# Copyright (c) 1993 - 2026 ARM Limited. All Rights Reserved.
# Use of this Software is subject to the terms and conditions of the
# applicable license agreement with ARM Limited.

# PhyVGen V 11.0.0-beta2
# ARM Version r0p0
# Creation Date: Tue Apr  7 18:06:24 2026


# Memory Configuration:
# ~~~~~~~~~~~~~~~~~~~~~
#  -activity_factor 50 -atf off -back_biasing off -bits 128 -bmux off
# -bus_notation on -check_instname on -diodes on -drive 6 -ema on -frequency
# 1.0 -instname rf128x128 -left_bus_delim "[" -mux 2 -mvt BASE -name_case lower
# -power_gating off -power_type otc -pwr_gnd_rename
# vddpe:VDDPE,vddce:VDDCE,vsse:VSSE -rcols 2 -redundancy off -retention on
# -right_bus_delim "]" -rrows 0 -ser none -site_def off -top_layer m5-m10
# -vmin_assist off -words 128 -wp_size 1 -write_mask on -write_thru off
# 

VERSION 5.8 ;
BUSBITCHARS "[]" ;
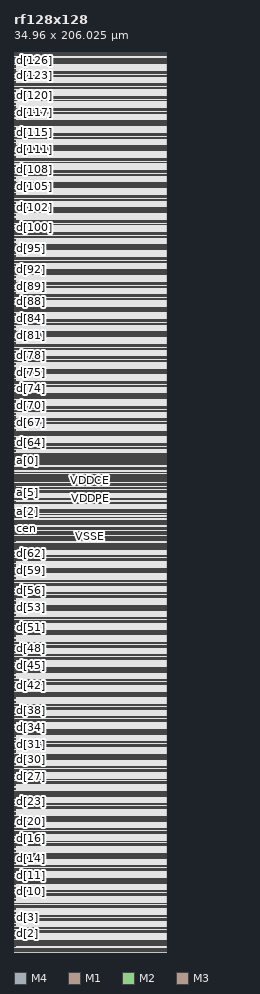
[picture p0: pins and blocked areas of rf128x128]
MACRO rf128x128
	FOREIGN rf128x128 0 0 ;
	SYMMETRY X Y ;
	SIZE 34.96 BY 206.025 ;
	CLASS BLOCK ;
	PIN VDDCE
		USE POWER ;
		DIRECTION INOUT ;
		PORT
			LAYER	M4 ;
			RECT	0 95.965 34.96 96.175 ;
		END

		PORT
			LAYER	M4 ;
			RECT	0 107.815 34.96 108.025 ;
		END

		PORT
			LAYER	M4 ;
			RECT	0 109.675 34.96 109.825 ;
		END

		PORT
			LAYER	M4 ;
			RECT	0 113.28 34.96 113.43 ;
		END

		PORT
			LAYER	M4 ;
			RECT	0 203.925 34.96 204.135 ;
		END

		PORT
			LAYER	M4 ;
			RECT	0 135.765 34.96 135.975 ;
		END

		PORT
			LAYER	M4 ;
			RECT	0 132.925 34.96 133.135 ;
		END

		PORT
			LAYER	M4 ;
			RECT	0 130.085 34.96 130.295 ;
		END

		PORT
			LAYER	M4 ;
			RECT	0 127.245 34.96 127.455 ;
		END

		PORT
			LAYER	M4 ;
			RECT	0 124.405 34.96 124.615 ;
		END

		PORT
			LAYER	M4 ;
			RECT	0 198.245 34.96 198.455 ;
		END

		PORT
			LAYER	M4 ;
			RECT	0 121.565 34.96 121.775 ;
		END

		PORT
			LAYER	M4 ;
			RECT	0 118.725 34.96 118.935 ;
		END

		PORT
			LAYER	M4 ;
			RECT	0 115.885 34.96 116.095 ;
		END

		PORT
			LAYER	M4 ;
			RECT	0 195.405 34.96 195.615 ;
		END

		PORT
			LAYER	M4 ;
			RECT	0 89.93 34.96 90.14 ;
		END

		PORT
			LAYER	M4 ;
			RECT	0 87.09 34.96 87.3 ;
		END

		PORT
			LAYER	M4 ;
			RECT	0 84.25 34.96 84.46 ;
		END

		PORT
			LAYER	M4 ;
			RECT	0 81.41 34.96 81.62 ;
		END

		PORT
			LAYER	M4 ;
			RECT	0 78.57 34.96 78.78 ;
		END

		PORT
			LAYER	M4 ;
			RECT	0 75.73 34.96 75.94 ;
		END

		PORT
			LAYER	M4 ;
			RECT	0 72.89 34.96 73.1 ;
		END

		PORT
			LAYER	M4 ;
			RECT	0 192.565 34.96 192.775 ;
		END

		PORT
			LAYER	M4 ;
			RECT	0 70.05 34.96 70.26 ;
		END

		PORT
			LAYER	M4 ;
			RECT	0 67.21 34.96 67.42 ;
		END

		PORT
			LAYER	M4 ;
			RECT	0 64.37 34.96 64.58 ;
		END

		PORT
			LAYER	M4 ;
			RECT	0 61.53 34.96 61.74 ;
		END

		PORT
			LAYER	M4 ;
			RECT	0 58.69 34.96 58.9 ;
		END

		PORT
			LAYER	M4 ;
			RECT	0 55.85 34.96 56.06 ;
		END

		PORT
			LAYER	M4 ;
			RECT	0 53.01 34.96 53.22 ;
		END

		PORT
			LAYER	M4 ;
			RECT	0 50.17 34.96 50.38 ;
		END

		PORT
			LAYER	M4 ;
			RECT	0 47.33 34.96 47.54 ;
		END

		PORT
			LAYER	M4 ;
			RECT	0 44.49 34.96 44.7 ;
		END

		PORT
			LAYER	M4 ;
			RECT	0 189.725 34.96 189.935 ;
		END

		PORT
			LAYER	M4 ;
			RECT	0 41.65 34.96 41.86 ;
		END

		PORT
			LAYER	M4 ;
			RECT	0 38.81 34.96 39.02 ;
		END

		PORT
			LAYER	M4 ;
			RECT	0 35.97 34.96 36.18 ;
		END

		PORT
			LAYER	M4 ;
			RECT	0 33.13 34.96 33.34 ;
		END

		PORT
			LAYER	M4 ;
			RECT	0 30.29 34.96 30.5 ;
		END

		PORT
			LAYER	M4 ;
			RECT	0 27.45 34.96 27.66 ;
		END

		PORT
			LAYER	M4 ;
			RECT	0 24.61 34.96 24.82 ;
		END

		PORT
			LAYER	M4 ;
			RECT	0 21.77 34.96 21.98 ;
		END

		PORT
			LAYER	M4 ;
			RECT	0 18.93 34.96 19.14 ;
		END

		PORT
			LAYER	M4 ;
			RECT	0 16.09 34.96 16.3 ;
		END

		PORT
			LAYER	M4 ;
			RECT	0 186.885 34.96 187.095 ;
		END

		PORT
			LAYER	M4 ;
			RECT	0 13.25 34.96 13.46 ;
		END

		PORT
			LAYER	M4 ;
			RECT	0 10.41 34.96 10.62 ;
		END

		PORT
			LAYER	M4 ;
			RECT	0 7.57 34.96 7.78 ;
		END

		PORT
			LAYER	M4 ;
			RECT	0 4.73 34.96 4.94 ;
		END

		PORT
			LAYER	M4 ;
			RECT	0 1.89 34.96 2.1 ;
		END

		PORT
			LAYER	M4 ;
			RECT	0 184.045 34.96 184.255 ;
		END

		PORT
			LAYER	M4 ;
			RECT	0 181.205 34.96 181.415 ;
		END

		PORT
			LAYER	M4 ;
			RECT	0 178.365 34.96 178.575 ;
		END

		PORT
			LAYER	M4 ;
			RECT	0 175.525 34.96 175.735 ;
		END

		PORT
			LAYER	M4 ;
			RECT	0 172.685 34.96 172.895 ;
		END

		PORT
			LAYER	M4 ;
			RECT	0 169.845 34.96 170.055 ;
		END

		PORT
			LAYER	M4 ;
			RECT	0 167.005 34.96 167.215 ;
		END

		PORT
			LAYER	M4 ;
			RECT	0 164.165 34.96 164.375 ;
		END

		PORT
			LAYER	M4 ;
			RECT	0 161.325 34.96 161.535 ;
		END

		PORT
			LAYER	M4 ;
			RECT	0 158.485 34.96 158.695 ;
		END

		PORT
			LAYER	M4 ;
			RECT	0 155.645 34.96 155.855 ;
		END

		PORT
			LAYER	M4 ;
			RECT	0 152.805 34.96 153.015 ;
		END

		PORT
			LAYER	M4 ;
			RECT	0 201.085 34.96 201.295 ;
		END

		PORT
			LAYER	M4 ;
			RECT	0 149.965 34.96 150.175 ;
		END

		PORT
			LAYER	M4 ;
			RECT	0 147.125 34.96 147.335 ;
		END

		PORT
			LAYER	M4 ;
			RECT	0 144.285 34.96 144.495 ;
		END

		PORT
			LAYER	M4 ;
			RECT	0 141.445 34.96 141.655 ;
		END

		PORT
			LAYER	M4 ;
			RECT	0 138.605 34.96 138.815 ;
		END

		PORT
			LAYER	M4 ;
			RECT	0 92.235 34.96 92.365 ;
		END

		PORT
			LAYER	M4 ;
			RECT	0 95.665 34.96 95.795 ;
		END

		PORT
			LAYER	M4 ;
			RECT	0 205.205 34.96 205.355 ;
		END

		PORT
			LAYER	M4 ;
			RECT	0 108.195 34.96 108.325 ;
		END

		PORT
			LAYER	M4 ;
			RECT	0 0.67 34.96 0.82 ;
		END

		PORT
			LAYER	M4 ;
			RECT	0 114.07 34.96 114.2 ;
		END

	END VDDCE

	PIN VDDPE
		USE POWER ;
		DIRECTION INOUT ;
		PORT
			LAYER	M4 ;
			RECT	0 94.255 34.96 94.405 ;
		END

		PORT
			LAYER	M4 ;
			RECT	0 94.625 34.96 94.835 ;
		END

		PORT
			LAYER	M4 ;
			RECT	0 98.15 34.96 98.36 ;
		END

		PORT
			LAYER	M4 ;
			RECT	0 98.625 34.96 98.835 ;
		END

		PORT
			LAYER	M4 ;
			RECT	0 100.04 34.96 100.25 ;
		END

		PORT
			LAYER	M4 ;
			RECT	0 101.185 34.96 101.335 ;
		END

		PORT
			LAYER	M4 ;
			RECT	0 103.6 34.96 103.81 ;
		END

		PORT
			LAYER	M4 ;
			RECT	0 105.16 34.96 105.37 ;
		END

		PORT
			LAYER	M4 ;
			RECT	0 106.02 34.96 106.23 ;
		END

		PORT
			LAYER	M4 ;
			RECT	0 109.13 34.96 109.34 ;
		END

		PORT
			LAYER	M4 ;
			RECT	0 112.11 34.96 112.32 ;
		END

		PORT
			LAYER	M4 ;
			RECT	0 112.485 34.96 112.695 ;
		END

		PORT
			LAYER	M4 ;
			RECT	0 203.345 34.96 203.555 ;
		END

		PORT
			LAYER	M4 ;
			RECT	0 135.185 34.96 135.395 ;
		END

		PORT
			LAYER	M4 ;
			RECT	0 132.345 34.96 132.555 ;
		END

		PORT
			LAYER	M4 ;
			RECT	0 129.505 34.96 129.715 ;
		END

		PORT
			LAYER	M4 ;
			RECT	0 126.665 34.96 126.875 ;
		END

		PORT
			LAYER	M4 ;
			RECT	0 123.825 34.96 124.035 ;
		END

		PORT
			LAYER	M4 ;
			RECT	0 120.985 34.96 121.195 ;
		END

		PORT
			LAYER	M4 ;
			RECT	0 118.145 34.96 118.355 ;
		END

		PORT
			LAYER	M4 ;
			RECT	0 115.305 34.96 115.515 ;
		END

		PORT
			LAYER	M4 ;
			RECT	0 197.665 34.96 197.875 ;
		END

		PORT
			LAYER	M4 ;
			RECT	0 194.825 34.96 195.035 ;
		END

		PORT
			LAYER	M4 ;
			RECT	0 90.51 34.96 90.72 ;
		END

		PORT
			LAYER	M4 ;
			RECT	0 87.67 34.96 87.88 ;
		END

		PORT
			LAYER	M4 ;
			RECT	0 84.83 34.96 85.04 ;
		END

		PORT
			LAYER	M4 ;
			RECT	0 81.99 34.96 82.2 ;
		END

		PORT
			LAYER	M4 ;
			RECT	0 79.15 34.96 79.36 ;
		END

		PORT
			LAYER	M4 ;
			RECT	0 76.31 34.96 76.52 ;
		END

		PORT
			LAYER	M4 ;
			RECT	0 73.47 34.96 73.68 ;
		END

		PORT
			LAYER	M4 ;
			RECT	0 70.63 34.96 70.84 ;
		END

		PORT
			LAYER	M4 ;
			RECT	0 67.79 34.96 68 ;
		END

		PORT
			LAYER	M4 ;
			RECT	0 191.985 34.96 192.195 ;
		END

		PORT
			LAYER	M4 ;
			RECT	0 64.95 34.96 65.16 ;
		END

		PORT
			LAYER	M4 ;
			RECT	0 62.11 34.96 62.32 ;
		END

		PORT
			LAYER	M4 ;
			RECT	0 59.27 34.96 59.48 ;
		END

		PORT
			LAYER	M4 ;
			RECT	0 56.43 34.96 56.64 ;
		END

		PORT
			LAYER	M4 ;
			RECT	0 53.59 34.96 53.8 ;
		END

		PORT
			LAYER	M4 ;
			RECT	0 50.75 34.96 50.96 ;
		END

		PORT
			LAYER	M4 ;
			RECT	0 47.91 34.96 48.12 ;
		END

		PORT
			LAYER	M4 ;
			RECT	0 45.07 34.96 45.28 ;
		END

		PORT
			LAYER	M4 ;
			RECT	0 42.23 34.96 42.44 ;
		END

		PORT
			LAYER	M4 ;
			RECT	0 39.39 34.96 39.6 ;
		END

		PORT
			LAYER	M4 ;
			RECT	0 189.145 34.96 189.355 ;
		END

		PORT
			LAYER	M4 ;
			RECT	0 36.55 34.96 36.76 ;
		END

		PORT
			LAYER	M4 ;
			RECT	0 33.71 34.96 33.92 ;
		END

		PORT
			LAYER	M4 ;
			RECT	0 30.87 34.96 31.08 ;
		END

		PORT
			LAYER	M4 ;
			RECT	0 28.03 34.96 28.24 ;
		END

		PORT
			LAYER	M4 ;
			RECT	0 25.19 34.96 25.4 ;
		END

		PORT
			LAYER	M4 ;
			RECT	0 22.35 34.96 22.56 ;
		END

		PORT
			LAYER	M4 ;
			RECT	0 19.51 34.96 19.72 ;
		END

		PORT
			LAYER	M4 ;
			RECT	0 16.67 34.96 16.88 ;
		END

		PORT
			LAYER	M4 ;
			RECT	0 13.83 34.96 14.04 ;
		END

		PORT
			LAYER	M4 ;
			RECT	0 10.99 34.96 11.2 ;
		END

		PORT
			LAYER	M4 ;
			RECT	0 186.305 34.96 186.515 ;
		END

		PORT
			LAYER	M4 ;
			RECT	0 8.15 34.96 8.36 ;
		END

		PORT
			LAYER	M4 ;
			RECT	0 5.31 34.96 5.52 ;
		END

		PORT
			LAYER	M4 ;
			RECT	0 2.47 34.96 2.68 ;
		END

		PORT
			LAYER	M4 ;
			RECT	0 183.465 34.96 183.675 ;
		END

		PORT
			LAYER	M4 ;
			RECT	0 180.625 34.96 180.835 ;
		END

		PORT
			LAYER	M4 ;
			RECT	0 177.785 34.96 177.995 ;
		END

		PORT
			LAYER	M4 ;
			RECT	0 174.945 34.96 175.155 ;
		END

		PORT
			LAYER	M4 ;
			RECT	0 172.105 34.96 172.315 ;
		END

		PORT
			LAYER	M4 ;
			RECT	0 169.265 34.96 169.475 ;
		END

		PORT
			LAYER	M4 ;
			RECT	0 166.425 34.96 166.635 ;
		END

		PORT
			LAYER	M4 ;
			RECT	0 163.585 34.96 163.795 ;
		END

		PORT
			LAYER	M4 ;
			RECT	0 160.745 34.96 160.955 ;
		END

		PORT
			LAYER	M4 ;
			RECT	0 157.905 34.96 158.115 ;
		END

		PORT
			LAYER	M4 ;
			RECT	0 155.065 34.96 155.275 ;
		END

		PORT
			LAYER	M4 ;
			RECT	0 152.225 34.96 152.435 ;
		END

		PORT
			LAYER	M4 ;
			RECT	0 149.385 34.96 149.595 ;
		END

		PORT
			LAYER	M4 ;
			RECT	0 146.545 34.96 146.755 ;
		END

		PORT
			LAYER	M4 ;
			RECT	0 143.705 34.96 143.915 ;
		END

		PORT
			LAYER	M4 ;
			RECT	0 200.505 34.96 200.715 ;
		END

		PORT
			LAYER	M4 ;
			RECT	0 140.865 34.96 141.075 ;
		END

		PORT
			LAYER	M4 ;
			RECT	0 138.025 34.96 138.235 ;
		END

		PORT
			LAYER	M4 ;
			RECT	0 205.705 34.96 205.855 ;
		END

		PORT
			LAYER	M4 ;
			RECT	0 92.655 34.96 92.785 ;
		END

		PORT
			LAYER	M4 ;
			RECT	0 97.125 34.96 97.255 ;
		END

		PORT
			LAYER	M4 ;
			RECT	0 0.17 34.96 0.32 ;
		END

		PORT
			LAYER	M4 ;
			RECT	0 105.5 34.96 105.63 ;
		END

		PORT
			LAYER	M4 ;
			RECT	0 113.65 34.96 113.78 ;
		END

	END VDDPE

	PIN VSSE
		USE GROUND ;
		DIRECTION INOUT ;
		PORT
			LAYER	M4 ;
			RECT	0 92.445 34.96 92.575 ;
		END

		PORT
			LAYER	M4 ;
			RECT	0 205.455 34.96 205.605 ;
		END

		PORT
			LAYER	M4 ;
			RECT	0 99.425 34.96 99.555 ;
		END

		PORT
			LAYER	M4 ;
			RECT	0 0.42 34.96 0.57 ;
		END

		PORT
			LAYER	M4 ;
			RECT	0 106.69 34.96 106.82 ;
		END

		PORT
			LAYER	M4 ;
			RECT	0 110.885 34.96 111.015 ;
		END

		PORT
			LAYER	M4 ;
			RECT	0 113.86 34.96 113.99 ;
		END

		PORT
			LAYER	M4 ;
			RECT	0 92.98 34.96 93.11 ;
		END

		PORT
			LAYER	M4 ;
			RECT	0 93.39 34.96 93.6 ;
		END

		PORT
			LAYER	M4 ;
			RECT	0 94.97 34.96 95.18 ;
		END

		PORT
			LAYER	M4 ;
			RECT	0 96.76 34.96 96.91 ;
		END

		PORT
			LAYER	M4 ;
			RECT	0 97.865 34.96 98.015 ;
		END

		PORT
			LAYER	M4 ;
			RECT	0 100.575 34.96 100.725 ;
		END

		PORT
			LAYER	M4 ;
			RECT	0 100.915 34.96 101.065 ;
		END

		PORT
			LAYER	M4 ;
			RECT	0 102.63 34.96 102.84 ;
		END

		PORT
			LAYER	M4 ;
			RECT	0 107.05 34.96 107.26 ;
		END

		PORT
			LAYER	M4 ;
			RECT	0 108.655 34.96 108.865 ;
		END

		PORT
			LAYER	M4 ;
			RECT	0 110.395 34.96 110.605 ;
		END

		PORT
			LAYER	M4 ;
			RECT	0 111.59 34.96 111.8 ;
		END

		PORT
			LAYER	M4 ;
			RECT	0 112.955 34.96 113.165 ;
		END

		PORT
			LAYER	M4 ;
			RECT	0 204.235 34.96 204.445 ;
		END

		PORT
			LAYER	M4 ;
			RECT	0 133.235 34.96 133.445 ;
		END

		PORT
			LAYER	M4 ;
			RECT	0 130.395 34.96 130.605 ;
		END

		PORT
			LAYER	M4 ;
			RECT	0 198.555 34.96 198.765 ;
		END

		PORT
			LAYER	M4 ;
			RECT	0 127.555 34.96 127.765 ;
		END

		PORT
			LAYER	M4 ;
			RECT	0 124.715 34.96 124.925 ;
		END

		PORT
			LAYER	M4 ;
			RECT	0 121.875 34.96 122.085 ;
		END

		PORT
			LAYER	M4 ;
			RECT	0 119.035 34.96 119.245 ;
		END

		PORT
			LAYER	M4 ;
			RECT	0 116.195 34.96 116.405 ;
		END

		PORT
			LAYER	M4 ;
			RECT	0 195.715 34.96 195.925 ;
		END

		PORT
			LAYER	M4 ;
			RECT	0 89.62 34.96 89.83 ;
		END

		PORT
			LAYER	M4 ;
			RECT	0 86.78 34.96 86.99 ;
		END

		PORT
			LAYER	M4 ;
			RECT	0 83.94 34.96 84.15 ;
		END

		PORT
			LAYER	M4 ;
			RECT	0 81.1 34.96 81.31 ;
		END

		PORT
			LAYER	M4 ;
			RECT	0 192.875 34.96 193.085 ;
		END

		PORT
			LAYER	M4 ;
			RECT	0 78.26 34.96 78.47 ;
		END

		PORT
			LAYER	M4 ;
			RECT	0 75.42 34.96 75.63 ;
		END

		PORT
			LAYER	M4 ;
			RECT	0 72.58 34.96 72.79 ;
		END

		PORT
			LAYER	M4 ;
			RECT	0 69.74 34.96 69.95 ;
		END

		PORT
			LAYER	M4 ;
			RECT	0 66.9 34.96 67.11 ;
		END

		PORT
			LAYER	M4 ;
			RECT	0 64.06 34.96 64.27 ;
		END

		PORT
			LAYER	M4 ;
			RECT	0 61.22 34.96 61.43 ;
		END

		PORT
			LAYER	M4 ;
			RECT	0 58.38 34.96 58.59 ;
		END

		PORT
			LAYER	M4 ;
			RECT	0 55.54 34.96 55.75 ;
		END

		PORT
			LAYER	M4 ;
			RECT	0 52.7 34.96 52.91 ;
		END

		PORT
			LAYER	M4 ;
			RECT	0 190.035 34.96 190.245 ;
		END

		PORT
			LAYER	M4 ;
			RECT	0 49.86 34.96 50.07 ;
		END

		PORT
			LAYER	M4 ;
			RECT	0 47.02 34.96 47.23 ;
		END

		PORT
			LAYER	M4 ;
			RECT	0 44.18 34.96 44.39 ;
		END

		PORT
			LAYER	M4 ;
			RECT	0 41.34 34.96 41.55 ;
		END

		PORT
			LAYER	M4 ;
			RECT	0 38.5 34.96 38.71 ;
		END

		PORT
			LAYER	M4 ;
			RECT	0 35.66 34.96 35.87 ;
		END

		PORT
			LAYER	M4 ;
			RECT	0 32.82 34.96 33.03 ;
		END

		PORT
			LAYER	M4 ;
			RECT	0 29.98 34.96 30.19 ;
		END

		PORT
			LAYER	M4 ;
			RECT	0 27.14 34.96 27.35 ;
		END

		PORT
			LAYER	M4 ;
			RECT	0 24.3 34.96 24.51 ;
		END

		PORT
			LAYER	M4 ;
			RECT	0 187.195 34.96 187.405 ;
		END

		PORT
			LAYER	M4 ;
			RECT	0 21.46 34.96 21.67 ;
		END

		PORT
			LAYER	M4 ;
			RECT	0 18.62 34.96 18.83 ;
		END

		PORT
			LAYER	M4 ;
			RECT	0 15.78 34.96 15.99 ;
		END

		PORT
			LAYER	M4 ;
			RECT	0 12.94 34.96 13.15 ;
		END

		PORT
			LAYER	M4 ;
			RECT	0 10.1 34.96 10.31 ;
		END

		PORT
			LAYER	M4 ;
			RECT	0 7.26 34.96 7.47 ;
		END

		PORT
			LAYER	M4 ;
			RECT	0 4.42 34.96 4.63 ;
		END

		PORT
			LAYER	M4 ;
			RECT	0 1.58 34.96 1.79 ;
		END

		PORT
			LAYER	M4 ;
			RECT	0 184.355 34.96 184.565 ;
		END

		PORT
			LAYER	M4 ;
			RECT	0 181.515 34.96 181.725 ;
		END

		PORT
			LAYER	M4 ;
			RECT	0 178.675 34.96 178.885 ;
		END

		PORT
			LAYER	M4 ;
			RECT	0 175.835 34.96 176.045 ;
		END

		PORT
			LAYER	M4 ;
			RECT	0 172.995 34.96 173.205 ;
		END

		PORT
			LAYER	M4 ;
			RECT	0 170.155 34.96 170.365 ;
		END

		PORT
			LAYER	M4 ;
			RECT	0 167.315 34.96 167.525 ;
		END

		PORT
			LAYER	M4 ;
			RECT	0 164.475 34.96 164.685 ;
		END

		PORT
			LAYER	M4 ;
			RECT	0 161.635 34.96 161.845 ;
		END

		PORT
			LAYER	M4 ;
			RECT	0 158.795 34.96 159.005 ;
		END

		PORT
			LAYER	M4 ;
			RECT	0 201.395 34.96 201.605 ;
		END

		PORT
			LAYER	M4 ;
			RECT	0 155.955 34.96 156.165 ;
		END

		PORT
			LAYER	M4 ;
			RECT	0 153.115 34.96 153.325 ;
		END

		PORT
			LAYER	M4 ;
			RECT	0 150.275 34.96 150.485 ;
		END

		PORT
			LAYER	M4 ;
			RECT	0 147.435 34.96 147.645 ;
		END

		PORT
			LAYER	M4 ;
			RECT	0 144.595 34.96 144.805 ;
		END

		PORT
			LAYER	M4 ;
			RECT	0 141.755 34.96 141.965 ;
		END

		PORT
			LAYER	M4 ;
			RECT	0 138.915 34.96 139.125 ;
		END

		PORT
			LAYER	M4 ;
			RECT	0 136.075 34.96 136.285 ;
		END

	END VSSE

	PIN a[0]
		USE SIGNAL ;
		DIRECTION INPUT ;
		SHAPE ABUTMENT ;
		PORT
			LAYER	M1 ;
			RECT	0 112.385 0.25 112.485 ;
			LAYER	M2 ;
			RECT	0 112.385 0.25 112.485 ;
			LAYER	M3 ;
			RECT	0 112.385 0.25 112.485 ;
		END

		ANTENNAGATEAREA 0.014 ;
		ANTENNADIFFAREA 0.018 ;
		ANTENNAPARTIALMETALAREA 0.025 ;
	END a[0]

	PIN a[1]
		USE SIGNAL ;
		DIRECTION INPUT ;
		SHAPE ABUTMENT ;
		PORT
			LAYER	M1 ;
			RECT	0 100.49 0.25 100.59 ;
			LAYER	M2 ;
			RECT	0 100.49 0.25 100.59 ;
			LAYER	M3 ;
			RECT	0 100.49 0.25 100.59 ;
		END

		ANTENNAGATEAREA 0.014 ;
		ANTENNADIFFAREA 0.018 ;
		ANTENNAPARTIALMETALAREA 0.025 ;
	END a[1]

	PIN a[2]
		USE SIGNAL ;
		DIRECTION INPUT ;
		SHAPE ABUTMENT ;
		PORT
			LAYER	M1 ;
			RECT	0 100.89 0.25 100.99 ;
			LAYER	M2 ;
			RECT	0 100.89 0.25 100.99 ;
			LAYER	M3 ;
			RECT	0 100.89 0.25 100.99 ;
		END

		ANTENNAGATEAREA 0.014 ;
		ANTENNADIFFAREA 0.018 ;
		ANTENNAPARTIALMETALAREA 0.025 ;
	END a[2]

	PIN a[3]
		USE SIGNAL ;
		DIRECTION INPUT ;
		SHAPE ABUTMENT ;
		PORT
			LAYER	M1 ;
			RECT	0 102.8 0.25 102.9 ;
			LAYER	M2 ;
			RECT	0 102.8 0.25 102.9 ;
			LAYER	M3 ;
			RECT	0 102.8 0.25 102.9 ;
		END

		ANTENNAGATEAREA 0.014 ;
		ANTENNADIFFAREA 0.018 ;
		ANTENNAPARTIALMETALAREA 0.025 ;
	END a[3]

	PIN a[4]
		USE SIGNAL ;
		DIRECTION INPUT ;
		SHAPE ABUTMENT ;
		PORT
			LAYER	M1 ;
			RECT	0 103.13 0.25 103.23 ;
			LAYER	M2 ;
			RECT	0 103.13 0.25 103.23 ;
			LAYER	M3 ;
			RECT	0 103.13 0.25 103.23 ;
		END

		ANTENNAGATEAREA 0.014 ;
		ANTENNADIFFAREA 0.018 ;
		ANTENNAPARTIALMETALAREA 0.025 ;
	END a[4]

	PIN a[5]
		USE SIGNAL ;
		DIRECTION INPUT ;
		SHAPE ABUTMENT ;
		PORT
			LAYER	M1 ;
			RECT	0 105.235 0.25 105.335 ;
			LAYER	M2 ;
			RECT	0 105.235 0.25 105.335 ;
			LAYER	M3 ;
			RECT	0 105.235 0.25 105.335 ;
		END

		ANTENNAGATEAREA 0.014 ;
		ANTENNADIFFAREA 0.018 ;
		ANTENNAPARTIALMETALAREA 0.025 ;
	END a[5]

	PIN a[6]
		USE SIGNAL ;
		DIRECTION INPUT ;
		SHAPE ABUTMENT ;
		PORT
			LAYER	M1 ;
			RECT	0 106.505 0.25 106.605 ;
			LAYER	M2 ;
			RECT	0 106.505 0.25 106.605 ;
			LAYER	M3 ;
			RECT	0 106.505 0.25 106.605 ;
		END

		ANTENNAGATEAREA 0.014 ;
		ANTENNADIFFAREA 0.018 ;
		ANTENNAPARTIALMETALAREA 0.025 ;
	END a[6]

	PIN cen
		USE SIGNAL ;
		DIRECTION INPUT ;
		SHAPE ABUTMENT ;
		PORT
			LAYER	M1 ;
			RECT	0 96.9 0.25 97 ;
			LAYER	M2 ;
			RECT	0 96.9 0.25 97 ;
			LAYER	M3 ;
			RECT	0 96.9 0.25 97 ;
		END

		ANTENNAGATEAREA 0.014 ;
		ANTENNADIFFAREA 0.018 ;
		ANTENNAPARTIALMETALAREA 0.025 ;
	END cen

	PIN clk
		USE SIGNAL ;
		DIRECTION INPUT ;
		SHAPE ABUTMENT ;
		PORT
			LAYER	M1 ;
			RECT	0 96.51 0.25 96.61 ;
			LAYER	M2 ;
			RECT	0 96.51 0.25 96.61 ;
			LAYER	M3 ;
			RECT	0 96.51 0.25 96.61 ;
			LAYER	M4 ;
			RECT	0 96.51 0.25 96.61 ;
		END

		ANTENNAGATEAREA 0.014 ;
		ANTENNADIFFAREA 0.018 ;
		ANTENNAPARTIALMETALAREA 0.025 ;
	END clk

	PIN d[0]
		USE SIGNAL ;
		DIRECTION INPUT ;
		SHAPE ABUTMENT ;
		PORT
			LAYER	M1 ;
			RECT	0 1.365 0.25 1.465 ;
			LAYER	M2 ;
			RECT	0 1.365 0.25 1.465 ;
			LAYER	M3 ;
			RECT	0 1.365 0.25 1.465 ;
		END

		ANTENNAGATEAREA 0.014 ;
		ANTENNADIFFAREA 0.018 ;
		ANTENNAPARTIALMETALAREA 0.025 ;
	END d[0]

	PIN d[100]
		USE SIGNAL ;
		DIRECTION INPUT ;
		SHAPE ABUTMENT ;
		PORT
			LAYER	M1 ;
			RECT	0 165.85 0.25 165.95 ;
			LAYER	M2 ;
			RECT	0 165.85 0.25 165.95 ;
			LAYER	M3 ;
			RECT	0 165.85 0.25 165.95 ;
		END

		ANTENNAGATEAREA 0.014 ;
		ANTENNADIFFAREA 0.018 ;
		ANTENNAPARTIALMETALAREA 0.025 ;
	END d[100]

	PIN d[101]
		USE SIGNAL ;
		DIRECTION INPUT ;
		SHAPE ABUTMENT ;
		PORT
			LAYER	M1 ;
			RECT	0 167.64 0.25 167.74 ;
			LAYER	M2 ;
			RECT	0 167.64 0.25 167.74 ;
			LAYER	M3 ;
			RECT	0 167.64 0.25 167.74 ;
		END

		ANTENNAGATEAREA 0.014 ;
		ANTENNADIFFAREA 0.018 ;
		ANTENNAPARTIALMETALAREA 0.025 ;
	END d[101]

	PIN d[102]
		USE SIGNAL ;
		DIRECTION INPUT ;
		SHAPE ABUTMENT ;
		PORT
			LAYER	M1 ;
			RECT	0 168.69 0.25 168.79 ;
			LAYER	M2 ;
			RECT	0 168.69 0.25 168.79 ;
			LAYER	M3 ;
			RECT	0 168.69 0.25 168.79 ;
		END

		ANTENNAGATEAREA 0.014 ;
		ANTENNADIFFAREA 0.018 ;
		ANTENNAPARTIALMETALAREA 0.025 ;
	END d[102]

	PIN d[103]
		USE SIGNAL ;
		DIRECTION INPUT ;
		SHAPE ABUTMENT ;
		PORT
			LAYER	M1 ;
			RECT	0 170.48 0.25 170.58 ;
			LAYER	M2 ;
			RECT	0 170.48 0.25 170.58 ;
			LAYER	M3 ;
			RECT	0 170.48 0.25 170.58 ;
		END

		ANTENNAGATEAREA 0.014 ;
		ANTENNADIFFAREA 0.018 ;
		ANTENNAPARTIALMETALAREA 0.025 ;
	END d[103]

	PIN d[104]
		USE SIGNAL ;
		DIRECTION INPUT ;
		SHAPE ABUTMENT ;
		PORT
			LAYER	M1 ;
			RECT	0 171.53 0.25 171.63 ;
			LAYER	M2 ;
			RECT	0 171.53 0.25 171.63 ;
			LAYER	M3 ;
			RECT	0 171.53 0.25 171.63 ;
		END

		ANTENNAGATEAREA 0.014 ;
		ANTENNADIFFAREA 0.018 ;
		ANTENNAPARTIALMETALAREA 0.025 ;
	END d[104]

	PIN d[105]
		USE SIGNAL ;
		DIRECTION INPUT ;
		SHAPE ABUTMENT ;
		PORT
			LAYER	M1 ;
			RECT	0 173.32 0.25 173.42 ;
			LAYER	M2 ;
			RECT	0 173.32 0.25 173.42 ;
			LAYER	M3 ;
			RECT	0 173.32 0.25 173.42 ;
		END

		ANTENNAGATEAREA 0.014 ;
		ANTENNADIFFAREA 0.018 ;
		ANTENNAPARTIALMETALAREA 0.025 ;
	END d[105]

	PIN d[106]
		USE SIGNAL ;
		DIRECTION INPUT ;
		SHAPE ABUTMENT ;
		PORT
			LAYER	M1 ;
			RECT	0 174.37 0.25 174.47 ;
			LAYER	M2 ;
			RECT	0 174.37 0.25 174.47 ;
			LAYER	M3 ;
			RECT	0 174.37 0.25 174.47 ;
		END

		ANTENNAGATEAREA 0.014 ;
		ANTENNADIFFAREA 0.018 ;
		ANTENNAPARTIALMETALAREA 0.025 ;
	END d[106]

	PIN d[107]
		USE SIGNAL ;
		DIRECTION INPUT ;
		SHAPE ABUTMENT ;
		PORT
			LAYER	M1 ;
			RECT	0 176.16 0.25 176.26 ;
			LAYER	M2 ;
			RECT	0 176.16 0.25 176.26 ;
			LAYER	M3 ;
			RECT	0 176.16 0.25 176.26 ;
		END

		ANTENNAGATEAREA 0.014 ;
		ANTENNADIFFAREA 0.018 ;
		ANTENNAPARTIALMETALAREA 0.025 ;
	END d[107]

	PIN d[108]
		USE SIGNAL ;
		DIRECTION INPUT ;
		SHAPE ABUTMENT ;
		PORT
			LAYER	M1 ;
			RECT	0 177.21 0.25 177.31 ;
			LAYER	M2 ;
			RECT	0 177.21 0.25 177.31 ;
			LAYER	M3 ;
			RECT	0 177.21 0.25 177.31 ;
		END

		ANTENNAGATEAREA 0.014 ;
		ANTENNADIFFAREA 0.018 ;
		ANTENNAPARTIALMETALAREA 0.025 ;
	END d[108]

	PIN d[109]
		USE SIGNAL ;
		DIRECTION INPUT ;
		SHAPE ABUTMENT ;
		PORT
			LAYER	M1 ;
			RECT	0 179 0.25 179.1 ;
			LAYER	M2 ;
			RECT	0 179 0.25 179.1 ;
			LAYER	M3 ;
			RECT	0 179 0.25 179.1 ;
		END

		ANTENNAGATEAREA 0.014 ;
		ANTENNADIFFAREA 0.018 ;
		ANTENNAPARTIALMETALAREA 0.025 ;
	END d[109]

	PIN d[10]
		USE SIGNAL ;
		DIRECTION INPUT ;
		SHAPE ABUTMENT ;
		PORT
			LAYER	M1 ;
			RECT	0 15.565 0.25 15.665 ;
			LAYER	M2 ;
			RECT	0 15.565 0.25 15.665 ;
			LAYER	M3 ;
			RECT	0 15.565 0.25 15.665 ;
		END

		ANTENNAGATEAREA 0.014 ;
		ANTENNADIFFAREA 0.018 ;
		ANTENNAPARTIALMETALAREA 0.025 ;
	END d[10]

	PIN d[110]
		USE SIGNAL ;
		DIRECTION INPUT ;
		SHAPE ABUTMENT ;
		PORT
			LAYER	M1 ;
			RECT	0 180.05 0.25 180.15 ;
			LAYER	M2 ;
			RECT	0 180.05 0.25 180.15 ;
			LAYER	M3 ;
			RECT	0 180.05 0.25 180.15 ;
		END

		ANTENNAGATEAREA 0.014 ;
		ANTENNADIFFAREA 0.018 ;
		ANTENNAPARTIALMETALAREA 0.025 ;
	END d[110]

	PIN d[111]
		USE SIGNAL ;
		DIRECTION INPUT ;
		SHAPE ABUTMENT ;
		PORT
			LAYER	M1 ;
			RECT	0 181.84 0.25 181.94 ;
			LAYER	M2 ;
			RECT	0 181.84 0.25 181.94 ;
			LAYER	M3 ;
			RECT	0 181.84 0.25 181.94 ;
		END

		ANTENNAGATEAREA 0.014 ;
		ANTENNADIFFAREA 0.018 ;
		ANTENNAPARTIALMETALAREA 0.025 ;
	END d[111]

	PIN d[112]
		USE SIGNAL ;
		DIRECTION INPUT ;
		SHAPE ABUTMENT ;
		PORT
			LAYER	M1 ;
			RECT	0 182.89 0.25 182.99 ;
			LAYER	M2 ;
			RECT	0 182.89 0.25 182.99 ;
			LAYER	M3 ;
			RECT	0 182.89 0.25 182.99 ;
		END

		ANTENNAGATEAREA 0.014 ;
		ANTENNADIFFAREA 0.018 ;
		ANTENNAPARTIALMETALAREA 0.025 ;
	END d[112]

	PIN d[113]
		USE SIGNAL ;
		DIRECTION INPUT ;
		SHAPE ABUTMENT ;
		PORT
			LAYER	M1 ;
			RECT	0 184.68 0.25 184.78 ;
			LAYER	M2 ;
			RECT	0 184.68 0.25 184.78 ;
			LAYER	M3 ;
			RECT	0 184.68 0.25 184.78 ;
		END

		ANTENNAGATEAREA 0.014 ;
		ANTENNADIFFAREA 0.018 ;
		ANTENNAPARTIALMETALAREA 0.025 ;
	END d[113]

	PIN d[114]
		USE SIGNAL ;
		DIRECTION INPUT ;
		SHAPE ABUTMENT ;
		PORT
			LAYER	M1 ;
			RECT	0 185.73 0.25 185.83 ;
			LAYER	M2 ;
			RECT	0 185.73 0.25 185.83 ;
			LAYER	M3 ;
			RECT	0 185.73 0.25 185.83 ;
		END

		ANTENNAGATEAREA 0.014 ;
		ANTENNADIFFAREA 0.018 ;
		ANTENNAPARTIALMETALAREA 0.025 ;
	END d[114]

	PIN d[115]
		USE SIGNAL ;
		DIRECTION INPUT ;
		SHAPE ABUTMENT ;
		PORT
			LAYER	M1 ;
			RECT	0 187.52 0.25 187.62 ;
			LAYER	M2 ;
			RECT	0 187.52 0.25 187.62 ;
			LAYER	M3 ;
			RECT	0 187.52 0.25 187.62 ;
		END

		ANTENNAGATEAREA 0.014 ;
		ANTENNADIFFAREA 0.018 ;
		ANTENNAPARTIALMETALAREA 0.025 ;
	END d[115]

	PIN d[116]
		USE SIGNAL ;
		DIRECTION INPUT ;
		SHAPE ABUTMENT ;
		PORT
			LAYER	M1 ;
			RECT	0 188.57 0.25 188.67 ;
			LAYER	M2 ;
			RECT	0 188.57 0.25 188.67 ;
			LAYER	M3 ;
			RECT	0 188.57 0.25 188.67 ;
		END

		ANTENNAGATEAREA 0.014 ;
		ANTENNADIFFAREA 0.018 ;
		ANTENNAPARTIALMETALAREA 0.025 ;
	END d[116]

	PIN d[117]
		USE SIGNAL ;
		DIRECTION INPUT ;
		SHAPE ABUTMENT ;
		PORT
			LAYER	M1 ;
			RECT	0 190.36 0.25 190.46 ;
			LAYER	M2 ;
			RECT	0 190.36 0.25 190.46 ;
			LAYER	M3 ;
			RECT	0 190.36 0.25 190.46 ;
		END

		ANTENNAGATEAREA 0.014 ;
		ANTENNADIFFAREA 0.018 ;
		ANTENNAPARTIALMETALAREA 0.025 ;
	END d[117]

	PIN d[118]
		USE SIGNAL ;
		DIRECTION INPUT ;
		SHAPE ABUTMENT ;
		PORT
			LAYER	M1 ;
			RECT	0 191.41 0.25 191.51 ;
			LAYER	M2 ;
			RECT	0 191.41 0.25 191.51 ;
			LAYER	M3 ;
			RECT	0 191.41 0.25 191.51 ;
		END

		ANTENNAGATEAREA 0.014 ;
		ANTENNADIFFAREA 0.018 ;
		ANTENNAPARTIALMETALAREA 0.025 ;
	END d[118]

	PIN d[119]
		USE SIGNAL ;
		DIRECTION INPUT ;
		SHAPE ABUTMENT ;
		PORT
			LAYER	M1 ;
			RECT	0 193.2 0.25 193.3 ;
			LAYER	M2 ;
			RECT	0 193.2 0.25 193.3 ;
			LAYER	M3 ;
			RECT	0 193.2 0.25 193.3 ;
		END

		ANTENNAGATEAREA 0.014 ;
		ANTENNADIFFAREA 0.018 ;
		ANTENNAPARTIALMETALAREA 0.025 ;
	END d[119]

	PIN d[11]
		USE SIGNAL ;
		DIRECTION INPUT ;
		SHAPE ABUTMENT ;
		PORT
			LAYER	M1 ;
			RECT	0 17.355 0.25 17.455 ;
			LAYER	M2 ;
			RECT	0 17.355 0.25 17.455 ;
			LAYER	M3 ;
			RECT	0 17.355 0.25 17.455 ;
		END

		ANTENNAGATEAREA 0.014 ;
		ANTENNADIFFAREA 0.018 ;
		ANTENNAPARTIALMETALAREA 0.025 ;
	END d[11]

	PIN d[120]
		USE SIGNAL ;
		DIRECTION INPUT ;
		SHAPE ABUTMENT ;
		PORT
			LAYER	M1 ;
			RECT	0 194.25 0.25 194.35 ;
			LAYER	M2 ;
			RECT	0 194.25 0.25 194.35 ;
			LAYER	M3 ;
			RECT	0 194.25 0.25 194.35 ;
		END

		ANTENNAGATEAREA 0.014 ;
		ANTENNADIFFAREA 0.018 ;
		ANTENNAPARTIALMETALAREA 0.025 ;
	END d[120]

	PIN d[121]
		USE SIGNAL ;
		DIRECTION INPUT ;
		SHAPE ABUTMENT ;
		PORT
			LAYER	M1 ;
			RECT	0 196.04 0.25 196.14 ;
			LAYER	M2 ;
			RECT	0 196.04 0.25 196.14 ;
			LAYER	M3 ;
			RECT	0 196.04 0.25 196.14 ;
		END

		ANTENNAGATEAREA 0.014 ;
		ANTENNADIFFAREA 0.018 ;
		ANTENNAPARTIALMETALAREA 0.025 ;
	END d[121]

	PIN d[122]
		USE SIGNAL ;
		DIRECTION INPUT ;
		SHAPE ABUTMENT ;
		PORT
			LAYER	M1 ;
			RECT	0 197.09 0.25 197.19 ;
			LAYER	M2 ;
			RECT	0 197.09 0.25 197.19 ;
			LAYER	M3 ;
			RECT	0 197.09 0.25 197.19 ;
		END

		ANTENNAGATEAREA 0.014 ;
		ANTENNADIFFAREA 0.018 ;
		ANTENNAPARTIALMETALAREA 0.025 ;
	END d[122]

	PIN d[123]
		USE SIGNAL ;
		DIRECTION INPUT ;
		SHAPE ABUTMENT ;
		PORT
			LAYER	M1 ;
			RECT	0 198.88 0.25 198.98 ;
			LAYER	M2 ;
			RECT	0 198.88 0.25 198.98 ;
			LAYER	M3 ;
			RECT	0 198.88 0.25 198.98 ;
		END

		ANTENNAGATEAREA 0.014 ;
		ANTENNADIFFAREA 0.018 ;
		ANTENNAPARTIALMETALAREA 0.025 ;
	END d[123]

	PIN d[124]
		USE SIGNAL ;
		DIRECTION INPUT ;
		SHAPE ABUTMENT ;
		PORT
			LAYER	M1 ;
			RECT	0 199.93 0.25 200.03 ;
			LAYER	M2 ;
			RECT	0 199.93 0.25 200.03 ;
			LAYER	M3 ;
			RECT	0 199.93 0.25 200.03 ;
		END

		ANTENNAGATEAREA 0.014 ;
		ANTENNADIFFAREA 0.018 ;
		ANTENNAPARTIALMETALAREA 0.025 ;
	END d[124]

	PIN d[125]
		USE SIGNAL ;
		DIRECTION INPUT ;
		SHAPE ABUTMENT ;
		PORT
			LAYER	M1 ;
			RECT	0 201.72 0.25 201.82 ;
			LAYER	M2 ;
			RECT	0 201.72 0.25 201.82 ;
			LAYER	M3 ;
			RECT	0 201.72 0.25 201.82 ;
		END

		ANTENNAGATEAREA 0.014 ;
		ANTENNADIFFAREA 0.018 ;
		ANTENNAPARTIALMETALAREA 0.025 ;
	END d[125]

	PIN d[126]
		USE SIGNAL ;
		DIRECTION INPUT ;
		SHAPE ABUTMENT ;
		PORT
			LAYER	M1 ;
			RECT	0 202.77 0.25 202.87 ;
			LAYER	M2 ;
			RECT	0 202.77 0.25 202.87 ;
			LAYER	M3 ;
			RECT	0 202.77 0.25 202.87 ;
		END

		ANTENNAGATEAREA 0.014 ;
		ANTENNADIFFAREA 0.018 ;
		ANTENNAPARTIALMETALAREA 0.025 ;
	END d[126]

	PIN d[127]
		USE SIGNAL ;
		DIRECTION INPUT ;
		SHAPE ABUTMENT ;
		PORT
			LAYER	M1 ;
			RECT	0 204.56 0.25 204.66 ;
			LAYER	M2 ;
			RECT	0 204.56 0.25 204.66 ;
			LAYER	M3 ;
			RECT	0 204.56 0.25 204.66 ;
		END

		ANTENNAGATEAREA 0.014 ;
		ANTENNADIFFAREA 0.018 ;
		ANTENNAPARTIALMETALAREA 0.025 ;
	END d[127]

	PIN d[12]
		USE SIGNAL ;
		DIRECTION INPUT ;
		SHAPE ABUTMENT ;
		PORT
			LAYER	M1 ;
			RECT	0 18.405 0.25 18.505 ;
			LAYER	M2 ;
			RECT	0 18.405 0.25 18.505 ;
			LAYER	M3 ;
			RECT	0 18.405 0.25 18.505 ;
		END

		ANTENNAGATEAREA 0.014 ;
		ANTENNADIFFAREA 0.018 ;
		ANTENNAPARTIALMETALAREA 0.025 ;
	END d[12]

	PIN d[13]
		USE SIGNAL ;
		DIRECTION INPUT ;
		SHAPE ABUTMENT ;
		PORT
			LAYER	M1 ;
			RECT	0 20.195 0.25 20.295 ;
			LAYER	M2 ;
			RECT	0 20.195 0.25 20.295 ;
			LAYER	M3 ;
			RECT	0 20.195 0.25 20.295 ;
		END

		ANTENNAGATEAREA 0.014 ;
		ANTENNADIFFAREA 0.018 ;
		ANTENNAPARTIALMETALAREA 0.025 ;
	END d[13]

	PIN d[14]
		USE SIGNAL ;
		DIRECTION INPUT ;
		SHAPE ABUTMENT ;
		PORT
			LAYER	M1 ;
			RECT	0 21.245 0.25 21.345 ;
			LAYER	M2 ;
			RECT	0 21.245 0.25 21.345 ;
			LAYER	M3 ;
			RECT	0 21.245 0.25 21.345 ;
		END

		ANTENNAGATEAREA 0.014 ;
		ANTENNADIFFAREA 0.018 ;
		ANTENNAPARTIALMETALAREA 0.025 ;
	END d[14]

	PIN d[15]
		USE SIGNAL ;
		DIRECTION INPUT ;
		SHAPE ABUTMENT ;
		PORT
			LAYER	M1 ;
			RECT	0 23.035 0.25 23.135 ;
			LAYER	M2 ;
			RECT	0 23.035 0.25 23.135 ;
			LAYER	M3 ;
			RECT	0 23.035 0.25 23.135 ;
		END

		ANTENNAGATEAREA 0.014 ;
		ANTENNADIFFAREA 0.018 ;
		ANTENNAPARTIALMETALAREA 0.025 ;
	END d[15]

	PIN d[16]
		USE SIGNAL ;
		DIRECTION INPUT ;
		SHAPE ABUTMENT ;
		PORT
			LAYER	M1 ;
			RECT	0 24.085 0.25 24.185 ;
			LAYER	M2 ;
			RECT	0 24.085 0.25 24.185 ;
			LAYER	M3 ;
			RECT	0 24.085 0.25 24.185 ;
		END

		ANTENNAGATEAREA 0.014 ;
		ANTENNADIFFAREA 0.018 ;
		ANTENNAPARTIALMETALAREA 0.025 ;
	END d[16]

	PIN d[17]
		USE SIGNAL ;
		DIRECTION INPUT ;
		SHAPE ABUTMENT ;
		PORT
			LAYER	M1 ;
			RECT	0 25.875 0.25 25.975 ;
			LAYER	M2 ;
			RECT	0 25.875 0.25 25.975 ;
			LAYER	M3 ;
			RECT	0 25.875 0.25 25.975 ;
		END

		ANTENNAGATEAREA 0.014 ;
		ANTENNADIFFAREA 0.018 ;
		ANTENNAPARTIALMETALAREA 0.025 ;
	END d[17]

	PIN d[18]
		USE SIGNAL ;
		DIRECTION INPUT ;
		SHAPE ABUTMENT ;
		PORT
			LAYER	M1 ;
			RECT	0 26.925 0.25 27.025 ;
			LAYER	M2 ;
			RECT	0 26.925 0.25 27.025 ;
			LAYER	M3 ;
			RECT	0 26.925 0.25 27.025 ;
		END

		ANTENNAGATEAREA 0.014 ;
		ANTENNADIFFAREA 0.018 ;
		ANTENNAPARTIALMETALAREA 0.025 ;
	END d[18]

	PIN d[19]
		USE SIGNAL ;
		DIRECTION INPUT ;
		SHAPE ABUTMENT ;
		PORT
			LAYER	M1 ;
			RECT	0 28.715 0.25 28.815 ;
			LAYER	M2 ;
			RECT	0 28.715 0.25 28.815 ;
			LAYER	M3 ;
			RECT	0 28.715 0.25 28.815 ;
		END

		ANTENNAGATEAREA 0.014 ;
		ANTENNADIFFAREA 0.018 ;
		ANTENNAPARTIALMETALAREA 0.025 ;
	END d[19]

	PIN d[1]
		USE SIGNAL ;
		DIRECTION INPUT ;
		SHAPE ABUTMENT ;
		PORT
			LAYER	M1 ;
			RECT	0 3.155 0.25 3.255 ;
			LAYER	M2 ;
			RECT	0 3.155 0.25 3.255 ;
			LAYER	M3 ;
			RECT	0 3.155 0.25 3.255 ;
		END

		ANTENNAGATEAREA 0.014 ;
		ANTENNADIFFAREA 0.018 ;
		ANTENNAPARTIALMETALAREA 0.025 ;
	END d[1]

	PIN d[20]
		USE SIGNAL ;
		DIRECTION INPUT ;
		SHAPE ABUTMENT ;
		PORT
			LAYER	M1 ;
			RECT	0 29.765 0.25 29.865 ;
			LAYER	M2 ;
			RECT	0 29.765 0.25 29.865 ;
			LAYER	M3 ;
			RECT	0 29.765 0.25 29.865 ;
		END

		ANTENNAGATEAREA 0.014 ;
		ANTENNADIFFAREA 0.018 ;
		ANTENNAPARTIALMETALAREA 0.025 ;
	END d[20]

	PIN d[21]
		USE SIGNAL ;
		DIRECTION INPUT ;
		SHAPE ABUTMENT ;
		PORT
			LAYER	M1 ;
			RECT	0 31.555 0.25 31.655 ;
			LAYER	M2 ;
			RECT	0 31.555 0.25 31.655 ;
			LAYER	M3 ;
			RECT	0 31.555 0.25 31.655 ;
		END

		ANTENNAGATEAREA 0.014 ;
		ANTENNADIFFAREA 0.018 ;
		ANTENNAPARTIALMETALAREA 0.025 ;
	END d[21]

	PIN d[22]
		USE SIGNAL ;
		DIRECTION INPUT ;
		SHAPE ABUTMENT ;
		PORT
			LAYER	M1 ;
			RECT	0 32.605 0.25 32.705 ;
			LAYER	M2 ;
			RECT	0 32.605 0.25 32.705 ;
			LAYER	M3 ;
			RECT	0 32.605 0.25 32.705 ;
		END

		ANTENNAGATEAREA 0.014 ;
		ANTENNADIFFAREA 0.018 ;
		ANTENNAPARTIALMETALAREA 0.025 ;
	END d[22]

	PIN d[23]
		USE SIGNAL ;
		DIRECTION INPUT ;
		SHAPE ABUTMENT ;
		PORT
			LAYER	M1 ;
			RECT	0 34.395 0.25 34.495 ;
			LAYER	M2 ;
			RECT	0 34.395 0.25 34.495 ;
			LAYER	M3 ;
			RECT	0 34.395 0.25 34.495 ;
		END

		ANTENNAGATEAREA 0.014 ;
		ANTENNADIFFAREA 0.018 ;
		ANTENNAPARTIALMETALAREA 0.025 ;
	END d[23]

	PIN d[24]
		USE SIGNAL ;
		DIRECTION INPUT ;
		SHAPE ABUTMENT ;
		PORT
			LAYER	M1 ;
			RECT	0 35.445 0.25 35.545 ;
			LAYER	M2 ;
			RECT	0 35.445 0.25 35.545 ;
			LAYER	M3 ;
			RECT	0 35.445 0.25 35.545 ;
		END

		ANTENNAGATEAREA 0.014 ;
		ANTENNADIFFAREA 0.018 ;
		ANTENNAPARTIALMETALAREA 0.025 ;
	END d[24]

	PIN d[25]
		USE SIGNAL ;
		DIRECTION INPUT ;
		SHAPE ABUTMENT ;
		PORT
			LAYER	M1 ;
			RECT	0 37.235 0.25 37.335 ;
			LAYER	M2 ;
			RECT	0 37.235 0.25 37.335 ;
			LAYER	M3 ;
			RECT	0 37.235 0.25 37.335 ;
		END

		ANTENNAGATEAREA 0.014 ;
		ANTENNADIFFAREA 0.018 ;
		ANTENNAPARTIALMETALAREA 0.025 ;
	END d[25]

	PIN d[26]
		USE SIGNAL ;
		DIRECTION INPUT ;
		SHAPE ABUTMENT ;
		PORT
			LAYER	M1 ;
			RECT	0 38.285 0.25 38.385 ;
			LAYER	M2 ;
			RECT	0 38.285 0.25 38.385 ;
			LAYER	M3 ;
			RECT	0 38.285 0.25 38.385 ;
		END

		ANTENNAGATEAREA 0.014 ;
		ANTENNADIFFAREA 0.018 ;
		ANTENNAPARTIALMETALAREA 0.025 ;
	END d[26]

	PIN d[27]
		USE SIGNAL ;
		DIRECTION INPUT ;
		SHAPE ABUTMENT ;
		PORT
			LAYER	M1 ;
			RECT	0 40.075 0.25 40.175 ;
			LAYER	M2 ;
			RECT	0 40.075 0.25 40.175 ;
			LAYER	M3 ;
			RECT	0 40.075 0.25 40.175 ;
		END

		ANTENNAGATEAREA 0.014 ;
		ANTENNADIFFAREA 0.018 ;
		ANTENNAPARTIALMETALAREA 0.025 ;
	END d[27]

	PIN d[28]
		USE SIGNAL ;
		DIRECTION INPUT ;
		SHAPE ABUTMENT ;
		PORT
			LAYER	M1 ;
			RECT	0 41.125 0.25 41.225 ;
			LAYER	M2 ;
			RECT	0 41.125 0.25 41.225 ;
			LAYER	M3 ;
			RECT	0 41.125 0.25 41.225 ;
		END

		ANTENNAGATEAREA 0.014 ;
		ANTENNADIFFAREA 0.018 ;
		ANTENNAPARTIALMETALAREA 0.025 ;
	END d[28]

	PIN d[29]
		USE SIGNAL ;
		DIRECTION INPUT ;
		SHAPE ABUTMENT ;
		PORT
			LAYER	M1 ;
			RECT	0 42.915 0.25 43.015 ;
			LAYER	M2 ;
			RECT	0 42.915 0.25 43.015 ;
			LAYER	M3 ;
			RECT	0 42.915 0.25 43.015 ;
		END

		ANTENNAGATEAREA 0.014 ;
		ANTENNADIFFAREA 0.018 ;
		ANTENNAPARTIALMETALAREA 0.025 ;
	END d[29]

	PIN d[2]
		USE SIGNAL ;
		DIRECTION INPUT ;
		SHAPE ABUTMENT ;
		PORT
			LAYER	M1 ;
			RECT	0 4.205 0.25 4.305 ;
			LAYER	M2 ;
			RECT	0 4.205 0.25 4.305 ;
			LAYER	M3 ;
			RECT	0 4.205 0.25 4.305 ;
		END

		ANTENNAGATEAREA 0.014 ;
		ANTENNADIFFAREA 0.018 ;
		ANTENNAPARTIALMETALAREA 0.025 ;
	END d[2]

	PIN d[30]
		USE SIGNAL ;
		DIRECTION INPUT ;
		SHAPE ABUTMENT ;
		PORT
			LAYER	M1 ;
			RECT	0 43.965 0.25 44.065 ;
			LAYER	M2 ;
			RECT	0 43.965 0.25 44.065 ;
			LAYER	M3 ;
			RECT	0 43.965 0.25 44.065 ;
		END

		ANTENNAGATEAREA 0.014 ;
		ANTENNADIFFAREA 0.018 ;
		ANTENNAPARTIALMETALAREA 0.025 ;
	END d[30]

	PIN d[31]
		USE SIGNAL ;
		DIRECTION INPUT ;
		SHAPE ABUTMENT ;
		PORT
			LAYER	M1 ;
			RECT	0 45.755 0.25 45.855 ;
			LAYER	M2 ;
			RECT	0 45.755 0.25 45.855 ;
			LAYER	M3 ;
			RECT	0 45.755 0.25 45.855 ;
		END

		ANTENNAGATEAREA 0.014 ;
		ANTENNADIFFAREA 0.018 ;
		ANTENNAPARTIALMETALAREA 0.025 ;
	END d[31]

	PIN d[32]
		USE SIGNAL ;
		DIRECTION INPUT ;
		SHAPE ABUTMENT ;
		PORT
			LAYER	M1 ;
			RECT	0 46.805 0.25 46.905 ;
			LAYER	M2 ;
			RECT	0 46.805 0.25 46.905 ;
			LAYER	M3 ;
			RECT	0 46.805 0.25 46.905 ;
		END

		ANTENNAGATEAREA 0.014 ;
		ANTENNADIFFAREA 0.018 ;
		ANTENNAPARTIALMETALAREA 0.025 ;
	END d[32]

	PIN d[33]
		USE SIGNAL ;
		DIRECTION INPUT ;
		SHAPE ABUTMENT ;
		PORT
			LAYER	M1 ;
			RECT	0 48.595 0.25 48.695 ;
			LAYER	M2 ;
			RECT	0 48.595 0.25 48.695 ;
			LAYER	M3 ;
			RECT	0 48.595 0.25 48.695 ;
		END

		ANTENNAGATEAREA 0.014 ;
		ANTENNADIFFAREA 0.018 ;
		ANTENNAPARTIALMETALAREA 0.025 ;
	END d[33]

	PIN d[34]
		USE SIGNAL ;
		DIRECTION INPUT ;
		SHAPE ABUTMENT ;
		PORT
			LAYER	M1 ;
			RECT	0 49.645 0.25 49.745 ;
			LAYER	M2 ;
			RECT	0 49.645 0.25 49.745 ;
			LAYER	M3 ;
			RECT	0 49.645 0.25 49.745 ;
		END

		ANTENNAGATEAREA 0.014 ;
		ANTENNADIFFAREA 0.018 ;
		ANTENNAPARTIALMETALAREA 0.025 ;
	END d[34]

	PIN d[35]
		USE SIGNAL ;
		DIRECTION INPUT ;
		SHAPE ABUTMENT ;
		PORT
			LAYER	M1 ;
			RECT	0 51.435 0.25 51.535 ;
			LAYER	M2 ;
			RECT	0 51.435 0.25 51.535 ;
			LAYER	M3 ;
			RECT	0 51.435 0.25 51.535 ;
		END

		ANTENNAGATEAREA 0.014 ;
		ANTENNADIFFAREA 0.018 ;
		ANTENNAPARTIALMETALAREA 0.025 ;
	END d[35]

	PIN d[36]
		USE SIGNAL ;
		DIRECTION INPUT ;
		SHAPE ABUTMENT ;
		PORT
			LAYER	M1 ;
			RECT	0 52.485 0.25 52.585 ;
			LAYER	M2 ;
			RECT	0 52.485 0.25 52.585 ;
			LAYER	M3 ;
			RECT	0 52.485 0.25 52.585 ;
		END

		ANTENNAGATEAREA 0.014 ;
		ANTENNADIFFAREA 0.018 ;
		ANTENNAPARTIALMETALAREA 0.025 ;
	END d[36]

	PIN d[37]
		USE SIGNAL ;
		DIRECTION INPUT ;
		SHAPE ABUTMENT ;
		PORT
			LAYER	M1 ;
			RECT	0 54.275 0.25 54.375 ;
			LAYER	M2 ;
			RECT	0 54.275 0.25 54.375 ;
			LAYER	M3 ;
			RECT	0 54.275 0.25 54.375 ;
		END

		ANTENNAGATEAREA 0.014 ;
		ANTENNADIFFAREA 0.018 ;
		ANTENNAPARTIALMETALAREA 0.025 ;
	END d[37]

	PIN d[38]
		USE SIGNAL ;
		DIRECTION INPUT ;
		SHAPE ABUTMENT ;
		PORT
			LAYER	M1 ;
			RECT	0 55.325 0.25 55.425 ;
			LAYER	M2 ;
			RECT	0 55.325 0.25 55.425 ;
			LAYER	M3 ;
			RECT	0 55.325 0.25 55.425 ;
		END

		ANTENNAGATEAREA 0.014 ;
		ANTENNADIFFAREA 0.018 ;
		ANTENNAPARTIALMETALAREA 0.025 ;
	END d[38]

	PIN d[39]
		USE SIGNAL ;
		DIRECTION INPUT ;
		SHAPE ABUTMENT ;
		PORT
			LAYER	M1 ;
			RECT	0 57.115 0.25 57.215 ;
			LAYER	M2 ;
			RECT	0 57.115 0.25 57.215 ;
			LAYER	M3 ;
			RECT	0 57.115 0.25 57.215 ;
		END

		ANTENNAGATEAREA 0.014 ;
		ANTENNADIFFAREA 0.018 ;
		ANTENNAPARTIALMETALAREA 0.025 ;
	END d[39]

	PIN d[3]
		USE SIGNAL ;
		DIRECTION INPUT ;
		SHAPE ABUTMENT ;
		PORT
			LAYER	M1 ;
			RECT	0 5.995 0.25 6.095 ;
			LAYER	M2 ;
			RECT	0 5.995 0.25 6.095 ;
			LAYER	M3 ;
			RECT	0 5.995 0.25 6.095 ;
		END

		ANTENNAGATEAREA 0.014 ;
		ANTENNADIFFAREA 0.018 ;
		ANTENNAPARTIALMETALAREA 0.025 ;
	END d[3]

	PIN d[40]
		USE SIGNAL ;
		DIRECTION INPUT ;
		SHAPE ABUTMENT ;
		PORT
			LAYER	M1 ;
			RECT	0 58.165 0.25 58.265 ;
			LAYER	M2 ;
			RECT	0 58.165 0.25 58.265 ;
			LAYER	M3 ;
			RECT	0 58.165 0.25 58.265 ;
		END

		ANTENNAGATEAREA 0.014 ;
		ANTENNADIFFAREA 0.018 ;
		ANTENNAPARTIALMETALAREA 0.025 ;
	END d[40]

	PIN d[41]
		USE SIGNAL ;
		DIRECTION INPUT ;
		SHAPE ABUTMENT ;
		PORT
			LAYER	M1 ;
			RECT	0 59.955 0.25 60.055 ;
			LAYER	M2 ;
			RECT	0 59.955 0.25 60.055 ;
			LAYER	M3 ;
			RECT	0 59.955 0.25 60.055 ;
		END

		ANTENNAGATEAREA 0.014 ;
		ANTENNADIFFAREA 0.018 ;
		ANTENNAPARTIALMETALAREA 0.025 ;
	END d[41]

	PIN d[42]
		USE SIGNAL ;
		DIRECTION INPUT ;
		SHAPE ABUTMENT ;
		PORT
			LAYER	M1 ;
			RECT	0 61.005 0.25 61.105 ;
			LAYER	M2 ;
			RECT	0 61.005 0.25 61.105 ;
			LAYER	M3 ;
			RECT	0 61.005 0.25 61.105 ;
		END

		ANTENNAGATEAREA 0.014 ;
		ANTENNADIFFAREA 0.018 ;
		ANTENNAPARTIALMETALAREA 0.025 ;
	END d[42]

	PIN d[43]
		USE SIGNAL ;
		DIRECTION INPUT ;
		SHAPE ABUTMENT ;
		PORT
			LAYER	M1 ;
			RECT	0 62.795 0.25 62.895 ;
			LAYER	M2 ;
			RECT	0 62.795 0.25 62.895 ;
			LAYER	M3 ;
			RECT	0 62.795 0.25 62.895 ;
		END

		ANTENNAGATEAREA 0.014 ;
		ANTENNADIFFAREA 0.018 ;
		ANTENNAPARTIALMETALAREA 0.025 ;
	END d[43]

	PIN d[44]
		USE SIGNAL ;
		DIRECTION INPUT ;
		SHAPE ABUTMENT ;
		PORT
			LAYER	M1 ;
			RECT	0 63.845 0.25 63.945 ;
			LAYER	M2 ;
			RECT	0 63.845 0.25 63.945 ;
			LAYER	M3 ;
			RECT	0 63.845 0.25 63.945 ;
		END

		ANTENNAGATEAREA 0.014 ;
		ANTENNADIFFAREA 0.018 ;
		ANTENNAPARTIALMETALAREA 0.025 ;
	END d[44]

	PIN d[45]
		USE SIGNAL ;
		DIRECTION INPUT ;
		SHAPE ABUTMENT ;
		PORT
			LAYER	M1 ;
			RECT	0 65.635 0.25 65.735 ;
			LAYER	M2 ;
			RECT	0 65.635 0.25 65.735 ;
			LAYER	M3 ;
			RECT	0 65.635 0.25 65.735 ;
		END

		ANTENNAGATEAREA 0.014 ;
		ANTENNADIFFAREA 0.018 ;
		ANTENNAPARTIALMETALAREA 0.025 ;
	END d[45]

	PIN d[46]
		USE SIGNAL ;
		DIRECTION INPUT ;
		SHAPE ABUTMENT ;
		PORT
			LAYER	M1 ;
			RECT	0 66.685 0.25 66.785 ;
			LAYER	M2 ;
			RECT	0 66.685 0.25 66.785 ;
			LAYER	M3 ;
			RECT	0 66.685 0.25 66.785 ;
		END

		ANTENNAGATEAREA 0.014 ;
		ANTENNADIFFAREA 0.018 ;
		ANTENNAPARTIALMETALAREA 0.025 ;
	END d[46]

	PIN d[47]
		USE SIGNAL ;
		DIRECTION INPUT ;
		SHAPE ABUTMENT ;
		PORT
			LAYER	M1 ;
			RECT	0 68.475 0.25 68.575 ;
			LAYER	M2 ;
			RECT	0 68.475 0.25 68.575 ;
			LAYER	M3 ;
			RECT	0 68.475 0.25 68.575 ;
		END

		ANTENNAGATEAREA 0.014 ;
		ANTENNADIFFAREA 0.018 ;
		ANTENNAPARTIALMETALAREA 0.025 ;
	END d[47]

	PIN d[48]
		USE SIGNAL ;
		DIRECTION INPUT ;
		SHAPE ABUTMENT ;
		PORT
			LAYER	M1 ;
			RECT	0 69.525 0.25 69.625 ;
			LAYER	M2 ;
			RECT	0 69.525 0.25 69.625 ;
			LAYER	M3 ;
			RECT	0 69.525 0.25 69.625 ;
		END

		ANTENNAGATEAREA 0.014 ;
		ANTENNADIFFAREA 0.018 ;
		ANTENNAPARTIALMETALAREA 0.025 ;
	END d[48]

	PIN d[49]
		USE SIGNAL ;
		DIRECTION INPUT ;
		SHAPE ABUTMENT ;
		PORT
			LAYER	M1 ;
			RECT	0 71.315 0.25 71.415 ;
			LAYER	M2 ;
			RECT	0 71.315 0.25 71.415 ;
			LAYER	M3 ;
			RECT	0 71.315 0.25 71.415 ;
		END

		ANTENNAGATEAREA 0.014 ;
		ANTENNADIFFAREA 0.018 ;
		ANTENNAPARTIALMETALAREA 0.025 ;
	END d[49]

	PIN d[4]
		USE SIGNAL ;
		DIRECTION INPUT ;
		SHAPE ABUTMENT ;
		PORT
			LAYER	M1 ;
			RECT	0 7.045 0.25 7.145 ;
			LAYER	M2 ;
			RECT	0 7.045 0.25 7.145 ;
			LAYER	M3 ;
			RECT	0 7.045 0.25 7.145 ;
		END

		ANTENNAGATEAREA 0.014 ;
		ANTENNADIFFAREA 0.018 ;
		ANTENNAPARTIALMETALAREA 0.025 ;
	END d[4]

	PIN d[50]
		USE SIGNAL ;
		DIRECTION INPUT ;
		SHAPE ABUTMENT ;
		PORT
			LAYER	M1 ;
			RECT	0 72.365 0.25 72.465 ;
			LAYER	M2 ;
			RECT	0 72.365 0.25 72.465 ;
			LAYER	M3 ;
			RECT	0 72.365 0.25 72.465 ;
		END

		ANTENNAGATEAREA 0.014 ;
		ANTENNADIFFAREA 0.018 ;
		ANTENNAPARTIALMETALAREA 0.025 ;
	END d[50]

	PIN d[51]
		USE SIGNAL ;
		DIRECTION INPUT ;
		SHAPE ABUTMENT ;
		PORT
			LAYER	M1 ;
			RECT	0 74.155 0.25 74.255 ;
			LAYER	M2 ;
			RECT	0 74.155 0.25 74.255 ;
			LAYER	M3 ;
			RECT	0 74.155 0.25 74.255 ;
		END

		ANTENNAGATEAREA 0.014 ;
		ANTENNADIFFAREA 0.018 ;
		ANTENNAPARTIALMETALAREA 0.025 ;
	END d[51]

	PIN d[52]
		USE SIGNAL ;
		DIRECTION INPUT ;
		SHAPE ABUTMENT ;
		PORT
			LAYER	M1 ;
			RECT	0 75.205 0.25 75.305 ;
			LAYER	M2 ;
			RECT	0 75.205 0.25 75.305 ;
			LAYER	M3 ;
			RECT	0 75.205 0.25 75.305 ;
		END

		ANTENNAGATEAREA 0.014 ;
		ANTENNADIFFAREA 0.018 ;
		ANTENNAPARTIALMETALAREA 0.025 ;
	END d[52]

	PIN d[53]
		USE SIGNAL ;
		DIRECTION INPUT ;
		SHAPE ABUTMENT ;
		PORT
			LAYER	M1 ;
			RECT	0 76.995 0.25 77.095 ;
			LAYER	M2 ;
			RECT	0 76.995 0.25 77.095 ;
			LAYER	M3 ;
			RECT	0 76.995 0.25 77.095 ;
		END

		ANTENNAGATEAREA 0.014 ;
		ANTENNADIFFAREA 0.018 ;
		ANTENNAPARTIALMETALAREA 0.025 ;
	END d[53]

	PIN d[54]
		USE SIGNAL ;
		DIRECTION INPUT ;
		SHAPE ABUTMENT ;
		PORT
			LAYER	M1 ;
			RECT	0 78.045 0.25 78.145 ;
			LAYER	M2 ;
			RECT	0 78.045 0.25 78.145 ;
			LAYER	M3 ;
			RECT	0 78.045 0.25 78.145 ;
		END

		ANTENNAGATEAREA 0.014 ;
		ANTENNADIFFAREA 0.018 ;
		ANTENNAPARTIALMETALAREA 0.025 ;
	END d[54]

	PIN d[55]
		USE SIGNAL ;
		DIRECTION INPUT ;
		SHAPE ABUTMENT ;
		PORT
			LAYER	M1 ;
			RECT	0 79.835 0.25 79.935 ;
			LAYER	M2 ;
			RECT	0 79.835 0.25 79.935 ;
			LAYER	M3 ;
			RECT	0 79.835 0.25 79.935 ;
		END

		ANTENNAGATEAREA 0.014 ;
		ANTENNADIFFAREA 0.018 ;
		ANTENNAPARTIALMETALAREA 0.025 ;
	END d[55]

	PIN d[56]
		USE SIGNAL ;
		DIRECTION INPUT ;
		SHAPE ABUTMENT ;
		PORT
			LAYER	M1 ;
			RECT	0 80.885 0.25 80.985 ;
			LAYER	M2 ;
			RECT	0 80.885 0.25 80.985 ;
			LAYER	M3 ;
			RECT	0 80.885 0.25 80.985 ;
		END

		ANTENNAGATEAREA 0.014 ;
		ANTENNADIFFAREA 0.018 ;
		ANTENNAPARTIALMETALAREA 0.025 ;
	END d[56]

	PIN d[57]
		USE SIGNAL ;
		DIRECTION INPUT ;
		SHAPE ABUTMENT ;
		PORT
			LAYER	M1 ;
			RECT	0 82.675 0.25 82.775 ;
			LAYER	M2 ;
			RECT	0 82.675 0.25 82.775 ;
			LAYER	M3 ;
			RECT	0 82.675 0.25 82.775 ;
		END

		ANTENNAGATEAREA 0.014 ;
		ANTENNADIFFAREA 0.018 ;
		ANTENNAPARTIALMETALAREA 0.025 ;
	END d[57]

	PIN d[58]
		USE SIGNAL ;
		DIRECTION INPUT ;
		SHAPE ABUTMENT ;
		PORT
			LAYER	M1 ;
			RECT	0 83.725 0.25 83.825 ;
			LAYER	M2 ;
			RECT	0 83.725 0.25 83.825 ;
			LAYER	M3 ;
			RECT	0 83.725 0.25 83.825 ;
		END

		ANTENNAGATEAREA 0.014 ;
		ANTENNADIFFAREA 0.018 ;
		ANTENNAPARTIALMETALAREA 0.025 ;
	END d[58]

	PIN d[59]
		USE SIGNAL ;
		DIRECTION INPUT ;
		SHAPE ABUTMENT ;
		PORT
			LAYER	M1 ;
			RECT	0 85.515 0.25 85.615 ;
			LAYER	M2 ;
			RECT	0 85.515 0.25 85.615 ;
			LAYER	M3 ;
			RECT	0 85.515 0.25 85.615 ;
		END

		ANTENNAGATEAREA 0.014 ;
		ANTENNADIFFAREA 0.018 ;
		ANTENNAPARTIALMETALAREA 0.025 ;
	END d[59]

	PIN d[5]
		USE SIGNAL ;
		DIRECTION INPUT ;
		SHAPE ABUTMENT ;
		PORT
			LAYER	M1 ;
			RECT	0 8.835 0.25 8.935 ;
			LAYER	M2 ;
			RECT	0 8.835 0.25 8.935 ;
			LAYER	M3 ;
			RECT	0 8.835 0.25 8.935 ;
		END

		ANTENNAGATEAREA 0.014 ;
		ANTENNADIFFAREA 0.018 ;
		ANTENNAPARTIALMETALAREA 0.025 ;
	END d[5]

	PIN d[60]
		USE SIGNAL ;
		DIRECTION INPUT ;
		SHAPE ABUTMENT ;
		PORT
			LAYER	M1 ;
			RECT	0 86.565 0.25 86.665 ;
			LAYER	M2 ;
			RECT	0 86.565 0.25 86.665 ;
			LAYER	M3 ;
			RECT	0 86.565 0.25 86.665 ;
		END

		ANTENNAGATEAREA 0.014 ;
		ANTENNADIFFAREA 0.018 ;
		ANTENNAPARTIALMETALAREA 0.025 ;
	END d[60]

	PIN d[61]
		USE SIGNAL ;
		DIRECTION INPUT ;
		SHAPE ABUTMENT ;
		PORT
			LAYER	M1 ;
			RECT	0 88.355 0.25 88.455 ;
			LAYER	M2 ;
			RECT	0 88.355 0.25 88.455 ;
			LAYER	M3 ;
			RECT	0 88.355 0.25 88.455 ;
		END

		ANTENNAGATEAREA 0.014 ;
		ANTENNADIFFAREA 0.018 ;
		ANTENNAPARTIALMETALAREA 0.025 ;
	END d[61]

	PIN d[62]
		USE SIGNAL ;
		DIRECTION INPUT ;
		SHAPE ABUTMENT ;
		PORT
			LAYER	M1 ;
			RECT	0 89.405 0.25 89.505 ;
			LAYER	M2 ;
			RECT	0 89.405 0.25 89.505 ;
			LAYER	M3 ;
			RECT	0 89.405 0.25 89.505 ;
		END

		ANTENNAGATEAREA 0.014 ;
		ANTENNADIFFAREA 0.018 ;
		ANTENNAPARTIALMETALAREA 0.025 ;
	END d[62]

	PIN d[63]
		USE SIGNAL ;
		DIRECTION INPUT ;
		SHAPE ABUTMENT ;
		PORT
			LAYER	M1 ;
			RECT	0 91.195 0.25 91.295 ;
			LAYER	M2 ;
			RECT	0 91.195 0.25 91.295 ;
			LAYER	M3 ;
			RECT	0 91.195 0.25 91.295 ;
		END

		ANTENNAGATEAREA 0.014 ;
		ANTENNADIFFAREA 0.018 ;
		ANTENNAPARTIALMETALAREA 0.025 ;
	END d[63]

	PIN d[64]
		USE SIGNAL ;
		DIRECTION INPUT ;
		SHAPE ABUTMENT ;
		PORT
			LAYER	M1 ;
			RECT	0 114.73 0.25 114.83 ;
			LAYER	M2 ;
			RECT	0 114.73 0.25 114.83 ;
			LAYER	M3 ;
			RECT	0 114.73 0.25 114.83 ;
		END

		ANTENNAGATEAREA 0.014 ;
		ANTENNADIFFAREA 0.018 ;
		ANTENNAPARTIALMETALAREA 0.025 ;
	END d[64]

	PIN d[65]
		USE SIGNAL ;
		DIRECTION INPUT ;
		SHAPE ABUTMENT ;
		PORT
			LAYER	M1 ;
			RECT	0 116.52 0.25 116.62 ;
			LAYER	M2 ;
			RECT	0 116.52 0.25 116.62 ;
			LAYER	M3 ;
			RECT	0 116.52 0.25 116.62 ;
		END

		ANTENNAGATEAREA 0.014 ;
		ANTENNADIFFAREA 0.018 ;
		ANTENNAPARTIALMETALAREA 0.025 ;
	END d[65]

	PIN d[66]
		USE SIGNAL ;
		DIRECTION INPUT ;
		SHAPE ABUTMENT ;
		PORT
			LAYER	M1 ;
			RECT	0 117.57 0.25 117.67 ;
			LAYER	M2 ;
			RECT	0 117.57 0.25 117.67 ;
			LAYER	M3 ;
			RECT	0 117.57 0.25 117.67 ;
		END

		ANTENNAGATEAREA 0.014 ;
		ANTENNADIFFAREA 0.018 ;
		ANTENNAPARTIALMETALAREA 0.025 ;
	END d[66]

	PIN d[67]
		USE SIGNAL ;
		DIRECTION INPUT ;
		SHAPE ABUTMENT ;
		PORT
			LAYER	M1 ;
			RECT	0 119.36 0.25 119.46 ;
			LAYER	M2 ;
			RECT	0 119.36 0.25 119.46 ;
			LAYER	M3 ;
			RECT	0 119.36 0.25 119.46 ;
		END

		ANTENNAGATEAREA 0.014 ;
		ANTENNADIFFAREA 0.018 ;
		ANTENNAPARTIALMETALAREA 0.025 ;
	END d[67]

	PIN d[68]
		USE SIGNAL ;
		DIRECTION INPUT ;
		SHAPE ABUTMENT ;
		PORT
			LAYER	M1 ;
			RECT	0 120.41 0.25 120.51 ;
			LAYER	M2 ;
			RECT	0 120.41 0.25 120.51 ;
			LAYER	M3 ;
			RECT	0 120.41 0.25 120.51 ;
		END

		ANTENNAGATEAREA 0.014 ;
		ANTENNADIFFAREA 0.018 ;
		ANTENNAPARTIALMETALAREA 0.025 ;
	END d[68]

	PIN d[69]
		USE SIGNAL ;
		DIRECTION INPUT ;
		SHAPE ABUTMENT ;
		PORT
			LAYER	M1 ;
			RECT	0 122.2 0.25 122.3 ;
			LAYER	M2 ;
			RECT	0 122.2 0.25 122.3 ;
			LAYER	M3 ;
			RECT	0 122.2 0.25 122.3 ;
		END

		ANTENNAGATEAREA 0.014 ;
		ANTENNADIFFAREA 0.018 ;
		ANTENNAPARTIALMETALAREA 0.025 ;
	END d[69]

	PIN d[6]
		USE SIGNAL ;
		DIRECTION INPUT ;
		SHAPE ABUTMENT ;
		PORT
			LAYER	M1 ;
			RECT	0 9.885 0.25 9.985 ;
			LAYER	M2 ;
			RECT	0 9.885 0.25 9.985 ;
			LAYER	M3 ;
			RECT	0 9.885 0.25 9.985 ;
		END

		ANTENNAGATEAREA 0.014 ;
		ANTENNADIFFAREA 0.018 ;
		ANTENNAPARTIALMETALAREA 0.025 ;
	END d[6]

	PIN d[70]
		USE SIGNAL ;
		DIRECTION INPUT ;
		SHAPE ABUTMENT ;
		PORT
			LAYER	M1 ;
			RECT	0 123.25 0.25 123.35 ;
			LAYER	M2 ;
			RECT	0 123.25 0.25 123.35 ;
			LAYER	M3 ;
			RECT	0 123.25 0.25 123.35 ;
		END

		ANTENNAGATEAREA 0.014 ;
		ANTENNADIFFAREA 0.018 ;
		ANTENNAPARTIALMETALAREA 0.025 ;
	END d[70]

	PIN d[71]
		USE SIGNAL ;
		DIRECTION INPUT ;
		SHAPE ABUTMENT ;
		PORT
			LAYER	M1 ;
			RECT	0 125.04 0.25 125.14 ;
			LAYER	M2 ;
			RECT	0 125.04 0.25 125.14 ;
			LAYER	M3 ;
			RECT	0 125.04 0.25 125.14 ;
		END

		ANTENNAGATEAREA 0.014 ;
		ANTENNADIFFAREA 0.018 ;
		ANTENNAPARTIALMETALAREA 0.025 ;
	END d[71]

	PIN d[72]
		USE SIGNAL ;
		DIRECTION INPUT ;
		SHAPE ABUTMENT ;
		PORT
			LAYER	M1 ;
			RECT	0 126.09 0.25 126.19 ;
			LAYER	M2 ;
			RECT	0 126.09 0.25 126.19 ;
			LAYER	M3 ;
			RECT	0 126.09 0.25 126.19 ;
		END

		ANTENNAGATEAREA 0.014 ;
		ANTENNADIFFAREA 0.018 ;
		ANTENNAPARTIALMETALAREA 0.025 ;
	END d[72]

	PIN d[73]
		USE SIGNAL ;
		DIRECTION INPUT ;
		SHAPE ABUTMENT ;
		PORT
			LAYER	M1 ;
			RECT	0 127.88 0.25 127.98 ;
			LAYER	M2 ;
			RECT	0 127.88 0.25 127.98 ;
			LAYER	M3 ;
			RECT	0 127.88 0.25 127.98 ;
		END

		ANTENNAGATEAREA 0.014 ;
		ANTENNADIFFAREA 0.018 ;
		ANTENNAPARTIALMETALAREA 0.025 ;
	END d[73]

	PIN d[74]
		USE SIGNAL ;
		DIRECTION INPUT ;
		SHAPE ABUTMENT ;
		PORT
			LAYER	M1 ;
			RECT	0 128.93 0.25 129.03 ;
			LAYER	M2 ;
			RECT	0 128.93 0.25 129.03 ;
			LAYER	M3 ;
			RECT	0 128.93 0.25 129.03 ;
		END

		ANTENNAGATEAREA 0.014 ;
		ANTENNADIFFAREA 0.018 ;
		ANTENNAPARTIALMETALAREA 0.025 ;
	END d[74]

	PIN d[75]
		USE SIGNAL ;
		DIRECTION INPUT ;
		SHAPE ABUTMENT ;
		PORT
			LAYER	M1 ;
			RECT	0 130.72 0.25 130.82 ;
			LAYER	M2 ;
			RECT	0 130.72 0.25 130.82 ;
			LAYER	M3 ;
			RECT	0 130.72 0.25 130.82 ;
		END

		ANTENNAGATEAREA 0.014 ;
		ANTENNADIFFAREA 0.018 ;
		ANTENNAPARTIALMETALAREA 0.025 ;
	END d[75]

	PIN d[76]
		USE SIGNAL ;
		DIRECTION INPUT ;
		SHAPE ABUTMENT ;
		PORT
			LAYER	M1 ;
			RECT	0 131.77 0.25 131.87 ;
			LAYER	M2 ;
			RECT	0 131.77 0.25 131.87 ;
			LAYER	M3 ;
			RECT	0 131.77 0.25 131.87 ;
		END

		ANTENNAGATEAREA 0.014 ;
		ANTENNADIFFAREA 0.018 ;
		ANTENNAPARTIALMETALAREA 0.025 ;
	END d[76]

	PIN d[77]
		USE SIGNAL ;
		DIRECTION INPUT ;
		SHAPE ABUTMENT ;
		PORT
			LAYER	M1 ;
			RECT	0 133.56 0.25 133.66 ;
			LAYER	M2 ;
			RECT	0 133.56 0.25 133.66 ;
			LAYER	M3 ;
			RECT	0 133.56 0.25 133.66 ;
		END

		ANTENNAGATEAREA 0.014 ;
		ANTENNADIFFAREA 0.018 ;
		ANTENNAPARTIALMETALAREA 0.025 ;
	END d[77]

	PIN d[78]
		USE SIGNAL ;
		DIRECTION INPUT ;
		SHAPE ABUTMENT ;
		PORT
			LAYER	M1 ;
			RECT	0 134.61 0.25 134.71 ;
			LAYER	M2 ;
			RECT	0 134.61 0.25 134.71 ;
			LAYER	M3 ;
			RECT	0 134.61 0.25 134.71 ;
		END

		ANTENNAGATEAREA 0.014 ;
		ANTENNADIFFAREA 0.018 ;
		ANTENNAPARTIALMETALAREA 0.025 ;
	END d[78]

	PIN d[79]
		USE SIGNAL ;
		DIRECTION INPUT ;
		SHAPE ABUTMENT ;
		PORT
			LAYER	M1 ;
			RECT	0 136.4 0.25 136.5 ;
			LAYER	M2 ;
			RECT	0 136.4 0.25 136.5 ;
			LAYER	M3 ;
			RECT	0 136.4 0.25 136.5 ;
		END

		ANTENNAGATEAREA 0.014 ;
		ANTENNADIFFAREA 0.018 ;
		ANTENNAPARTIALMETALAREA 0.025 ;
	END d[79]

	PIN d[7]
		USE SIGNAL ;
		DIRECTION INPUT ;
		SHAPE ABUTMENT ;
		PORT
			LAYER	M1 ;
			RECT	0 11.675 0.25 11.775 ;
			LAYER	M2 ;
			RECT	0 11.675 0.25 11.775 ;
			LAYER	M3 ;
			RECT	0 11.675 0.25 11.775 ;
		END

		ANTENNAGATEAREA 0.014 ;
		ANTENNADIFFAREA 0.018 ;
		ANTENNAPARTIALMETALAREA 0.025 ;
	END d[7]

	PIN d[80]
		USE SIGNAL ;
		DIRECTION INPUT ;
		SHAPE ABUTMENT ;
		PORT
			LAYER	M1 ;
			RECT	0 137.45 0.25 137.55 ;
			LAYER	M2 ;
			RECT	0 137.45 0.25 137.55 ;
			LAYER	M3 ;
			RECT	0 137.45 0.25 137.55 ;
		END

		ANTENNAGATEAREA 0.014 ;
		ANTENNADIFFAREA 0.018 ;
		ANTENNAPARTIALMETALAREA 0.025 ;
	END d[80]

	PIN d[81]
		USE SIGNAL ;
		DIRECTION INPUT ;
		SHAPE ABUTMENT ;
		PORT
			LAYER	M1 ;
			RECT	0 139.24 0.25 139.34 ;
			LAYER	M2 ;
			RECT	0 139.24 0.25 139.34 ;
			LAYER	M3 ;
			RECT	0 139.24 0.25 139.34 ;
		END

		ANTENNAGATEAREA 0.014 ;
		ANTENNADIFFAREA 0.018 ;
		ANTENNAPARTIALMETALAREA 0.025 ;
	END d[81]

	PIN d[82]
		USE SIGNAL ;
		DIRECTION INPUT ;
		SHAPE ABUTMENT ;
		PORT
			LAYER	M1 ;
			RECT	0 140.29 0.25 140.39 ;
			LAYER	M2 ;
			RECT	0 140.29 0.25 140.39 ;
			LAYER	M3 ;
			RECT	0 140.29 0.25 140.39 ;
		END

		ANTENNAGATEAREA 0.014 ;
		ANTENNADIFFAREA 0.018 ;
		ANTENNAPARTIALMETALAREA 0.025 ;
	END d[82]

	PIN d[83]
		USE SIGNAL ;
		DIRECTION INPUT ;
		SHAPE ABUTMENT ;
		PORT
			LAYER	M1 ;
			RECT	0 142.08 0.25 142.18 ;
			LAYER	M2 ;
			RECT	0 142.08 0.25 142.18 ;
			LAYER	M3 ;
			RECT	0 142.08 0.25 142.18 ;
		END

		ANTENNAGATEAREA 0.014 ;
		ANTENNADIFFAREA 0.018 ;
		ANTENNAPARTIALMETALAREA 0.025 ;
	END d[83]

	PIN d[84]
		USE SIGNAL ;
		DIRECTION INPUT ;
		SHAPE ABUTMENT ;
		PORT
			LAYER	M1 ;
			RECT	0 143.13 0.25 143.23 ;
			LAYER	M2 ;
			RECT	0 143.13 0.25 143.23 ;
			LAYER	M3 ;
			RECT	0 143.13 0.25 143.23 ;
		END

		ANTENNAGATEAREA 0.014 ;
		ANTENNADIFFAREA 0.018 ;
		ANTENNAPARTIALMETALAREA 0.025 ;
	END d[84]

	PIN d[85]
		USE SIGNAL ;
		DIRECTION INPUT ;
		SHAPE ABUTMENT ;
		PORT
			LAYER	M1 ;
			RECT	0 144.92 0.25 145.02 ;
			LAYER	M2 ;
			RECT	0 144.92 0.25 145.02 ;
			LAYER	M3 ;
			RECT	0 144.92 0.25 145.02 ;
		END

		ANTENNAGATEAREA 0.014 ;
		ANTENNADIFFAREA 0.018 ;
		ANTENNAPARTIALMETALAREA 0.025 ;
	END d[85]

	PIN d[86]
		USE SIGNAL ;
		DIRECTION INPUT ;
		SHAPE ABUTMENT ;
		PORT
			LAYER	M1 ;
			RECT	0 145.97 0.25 146.07 ;
			LAYER	M2 ;
			RECT	0 145.97 0.25 146.07 ;
			LAYER	M3 ;
			RECT	0 145.97 0.25 146.07 ;
		END

		ANTENNAGATEAREA 0.014 ;
		ANTENNADIFFAREA 0.018 ;
		ANTENNAPARTIALMETALAREA 0.025 ;
	END d[86]

	PIN d[87]
		USE SIGNAL ;
		DIRECTION INPUT ;
		SHAPE ABUTMENT ;
		PORT
			LAYER	M1 ;
			RECT	0 147.76 0.25 147.86 ;
			LAYER	M2 ;
			RECT	0 147.76 0.25 147.86 ;
			LAYER	M3 ;
			RECT	0 147.76 0.25 147.86 ;
		END

		ANTENNAGATEAREA 0.014 ;
		ANTENNADIFFAREA 0.018 ;
		ANTENNAPARTIALMETALAREA 0.025 ;
	END d[87]

	PIN d[88]
		USE SIGNAL ;
		DIRECTION INPUT ;
		SHAPE ABUTMENT ;
		PORT
			LAYER	M1 ;
			RECT	0 148.81 0.25 148.91 ;
			LAYER	M2 ;
			RECT	0 148.81 0.25 148.91 ;
			LAYER	M3 ;
			RECT	0 148.81 0.25 148.91 ;
		END

		ANTENNAGATEAREA 0.014 ;
		ANTENNADIFFAREA 0.018 ;
		ANTENNAPARTIALMETALAREA 0.025 ;
	END d[88]

	PIN d[89]
		USE SIGNAL ;
		DIRECTION INPUT ;
		SHAPE ABUTMENT ;
		PORT
			LAYER	M1 ;
			RECT	0 150.6 0.25 150.7 ;
			LAYER	M2 ;
			RECT	0 150.6 0.25 150.7 ;
			LAYER	M3 ;
			RECT	0 150.6 0.25 150.7 ;
		END

		ANTENNAGATEAREA 0.014 ;
		ANTENNADIFFAREA 0.018 ;
		ANTENNAPARTIALMETALAREA 0.025 ;
	END d[89]

	PIN d[8]
		USE SIGNAL ;
		DIRECTION INPUT ;
		SHAPE ABUTMENT ;
		PORT
			LAYER	M1 ;
			RECT	0 12.725 0.25 12.825 ;
			LAYER	M2 ;
			RECT	0 12.725 0.25 12.825 ;
			LAYER	M3 ;
			RECT	0 12.725 0.25 12.825 ;
		END

		ANTENNAGATEAREA 0.014 ;
		ANTENNADIFFAREA 0.018 ;
		ANTENNAPARTIALMETALAREA 0.025 ;
	END d[8]

	PIN d[90]
		USE SIGNAL ;
		DIRECTION INPUT ;
		SHAPE ABUTMENT ;
		PORT
			LAYER	M1 ;
			RECT	0 151.65 0.25 151.75 ;
			LAYER	M2 ;
			RECT	0 151.65 0.25 151.75 ;
			LAYER	M3 ;
			RECT	0 151.65 0.25 151.75 ;
		END

		ANTENNAGATEAREA 0.014 ;
		ANTENNADIFFAREA 0.018 ;
		ANTENNAPARTIALMETALAREA 0.025 ;
	END d[90]

	PIN d[91]
		USE SIGNAL ;
		DIRECTION INPUT ;
		SHAPE ABUTMENT ;
		PORT
			LAYER	M1 ;
			RECT	0 153.44 0.25 153.54 ;
			LAYER	M2 ;
			RECT	0 153.44 0.25 153.54 ;
			LAYER	M3 ;
			RECT	0 153.44 0.25 153.54 ;
		END

		ANTENNAGATEAREA 0.014 ;
		ANTENNADIFFAREA 0.018 ;
		ANTENNAPARTIALMETALAREA 0.025 ;
	END d[91]

	PIN d[92]
		USE SIGNAL ;
		DIRECTION INPUT ;
		SHAPE ABUTMENT ;
		PORT
			LAYER	M1 ;
			RECT	0 154.49 0.25 154.59 ;
			LAYER	M2 ;
			RECT	0 154.49 0.25 154.59 ;
			LAYER	M3 ;
			RECT	0 154.49 0.25 154.59 ;
		END

		ANTENNAGATEAREA 0.014 ;
		ANTENNADIFFAREA 0.018 ;
		ANTENNAPARTIALMETALAREA 0.025 ;
	END d[92]

	PIN d[93]
		USE SIGNAL ;
		DIRECTION INPUT ;
		SHAPE ABUTMENT ;
		PORT
			LAYER	M1 ;
			RECT	0 156.28 0.25 156.38 ;
			LAYER	M2 ;
			RECT	0 156.28 0.25 156.38 ;
			LAYER	M3 ;
			RECT	0 156.28 0.25 156.38 ;
		END

		ANTENNAGATEAREA 0.014 ;
		ANTENNADIFFAREA 0.018 ;
		ANTENNAPARTIALMETALAREA 0.025 ;
	END d[93]

	PIN d[94]
		USE SIGNAL ;
		DIRECTION INPUT ;
		SHAPE ABUTMENT ;
		PORT
			LAYER	M1 ;
			RECT	0 157.33 0.25 157.43 ;
			LAYER	M2 ;
			RECT	0 157.33 0.25 157.43 ;
			LAYER	M3 ;
			RECT	0 157.33 0.25 157.43 ;
		END

		ANTENNAGATEAREA 0.014 ;
		ANTENNADIFFAREA 0.018 ;
		ANTENNAPARTIALMETALAREA 0.025 ;
	END d[94]

	PIN d[95]
		USE SIGNAL ;
		DIRECTION INPUT ;
		SHAPE ABUTMENT ;
		PORT
			LAYER	M1 ;
			RECT	0 159.12 0.25 159.22 ;
			LAYER	M2 ;
			RECT	0 159.12 0.25 159.22 ;
			LAYER	M3 ;
			RECT	0 159.12 0.25 159.22 ;
		END

		ANTENNAGATEAREA 0.014 ;
		ANTENNADIFFAREA 0.018 ;
		ANTENNAPARTIALMETALAREA 0.025 ;
	END d[95]

	PIN d[96]
		USE SIGNAL ;
		DIRECTION INPUT ;
		SHAPE ABUTMENT ;
		PORT
			LAYER	M1 ;
			RECT	0 160.17 0.25 160.27 ;
			LAYER	M2 ;
			RECT	0 160.17 0.25 160.27 ;
			LAYER	M3 ;
			RECT	0 160.17 0.25 160.27 ;
		END

		ANTENNAGATEAREA 0.014 ;
		ANTENNADIFFAREA 0.018 ;
		ANTENNAPARTIALMETALAREA 0.025 ;
	END d[96]

	PIN d[97]
		USE SIGNAL ;
		DIRECTION INPUT ;
		SHAPE ABUTMENT ;
		PORT
			LAYER	M1 ;
			RECT	0 161.96 0.25 162.06 ;
			LAYER	M2 ;
			RECT	0 161.96 0.25 162.06 ;
			LAYER	M3 ;
			RECT	0 161.96 0.25 162.06 ;
		END

		ANTENNAGATEAREA 0.014 ;
		ANTENNADIFFAREA 0.018 ;
		ANTENNAPARTIALMETALAREA 0.025 ;
	END d[97]

	PIN d[98]
		USE SIGNAL ;
		DIRECTION INPUT ;
		SHAPE ABUTMENT ;
		PORT
			LAYER	M1 ;
			RECT	0 163.01 0.25 163.11 ;
			LAYER	M2 ;
			RECT	0 163.01 0.25 163.11 ;
			LAYER	M3 ;
			RECT	0 163.01 0.25 163.11 ;
		END

		ANTENNAGATEAREA 0.014 ;
		ANTENNADIFFAREA 0.018 ;
		ANTENNAPARTIALMETALAREA 0.025 ;
	END d[98]

	PIN d[99]
		USE SIGNAL ;
		DIRECTION INPUT ;
		SHAPE ABUTMENT ;
		PORT
			LAYER	M1 ;
			RECT	0 164.8 0.25 164.9 ;
			LAYER	M2 ;
			RECT	0 164.8 0.25 164.9 ;
			LAYER	M3 ;
			RECT	0 164.8 0.25 164.9 ;
		END

		ANTENNAGATEAREA 0.014 ;
		ANTENNADIFFAREA 0.018 ;
		ANTENNAPARTIALMETALAREA 0.025 ;
	END d[99]

	PIN d[9]
		USE SIGNAL ;
		DIRECTION INPUT ;
		SHAPE ABUTMENT ;
		PORT
			LAYER	M1 ;
			RECT	0 14.515 0.25 14.615 ;
			LAYER	M2 ;
			RECT	0 14.515 0.25 14.615 ;
			LAYER	M3 ;
			RECT	0 14.515 0.25 14.615 ;
		END

		ANTENNAGATEAREA 0.014 ;
		ANTENNADIFFAREA 0.018 ;
		ANTENNAPARTIALMETALAREA 0.025 ;
	END d[9]

	PIN ema[0]
		USE SIGNAL ;
		DIRECTION INPUT ;
		SHAPE ABUTMENT ;
		PORT
			LAYER	M1 ;
			RECT	0 106.105 0.25 106.205 ;
			LAYER	M2 ;
			RECT	0 106.105 0.25 106.205 ;
			LAYER	M3 ;
			RECT	0 106.105 0.25 106.205 ;
		END

		ANTENNAGATEAREA 0.014 ;
		ANTENNADIFFAREA 0.018 ;
		ANTENNAPARTIALMETALAREA 0.025 ;
	END ema[0]

	PIN ema[1]
		USE SIGNAL ;
		DIRECTION INPUT ;
		SHAPE ABUTMENT ;
		PORT
			LAYER	M1 ;
			RECT	0 105.905 0.25 106.005 ;
			LAYER	M2 ;
			RECT	0 105.905 0.25 106.005 ;
			LAYER	M3 ;
			RECT	0 105.905 0.25 106.005 ;
		END

		ANTENNAGATEAREA 0.014 ;
		ANTENNADIFFAREA 0.018 ;
		ANTENNAPARTIALMETALAREA 0.025 ;
	END ema[1]

	PIN ema[2]
		USE SIGNAL ;
		DIRECTION INPUT ;
		SHAPE ABUTMENT ;
		PORT
			LAYER	M1 ;
			RECT	0 105.705 0.25 105.805 ;
			LAYER	M2 ;
			RECT	0 105.705 0.25 105.805 ;
			LAYER	M3 ;
			RECT	0 105.705 0.25 105.805 ;
		END

		ANTENNAGATEAREA 0.014 ;
		ANTENNADIFFAREA 0.018 ;
		ANTENNAPARTIALMETALAREA 0.025 ;
	END ema[2]

	PIN emas
		USE SIGNAL ;
		DIRECTION INPUT ;
		SHAPE ABUTMENT ;
		PORT
			LAYER	M1 ;
			RECT	0 112.76 0.25 112.86 ;
			LAYER	M2 ;
			RECT	0 112.76 0.25 112.86 ;
			LAYER	M3 ;
			RECT	0 112.76 0.25 112.86 ;
		END

		ANTENNAGATEAREA 0.014 ;
		ANTENNADIFFAREA 0.018 ;
		ANTENNAPARTIALMETALAREA 0.025 ;
	END emas

	PIN emaw[0]
		USE SIGNAL ;
		DIRECTION INPUT ;
		SHAPE ABUTMENT ;
		PORT
			LAYER	M2 ;
			RECT	0 99.695 0.25 99.795 ;
			LAYER	M3 ;
			RECT	0 99.695 0.25 99.795 ;
		END

		ANTENNAGATEAREA 0.014 ;
		ANTENNADIFFAREA 0.018 ;
		ANTENNAPARTIALMETALAREA 0.025 ;
	END emaw[0]

	PIN emaw[1]
		USE SIGNAL ;
		DIRECTION INPUT ;
		SHAPE ABUTMENT ;
		PORT
			LAYER	M1 ;
			RECT	0 99.89 0.25 99.99 ;
			LAYER	M2 ;
			RECT	0 99.89 0.25 99.99 ;
			LAYER	M3 ;
			RECT	0 99.89 0.25 99.99 ;
		END

		ANTENNAGATEAREA 0.014 ;
		ANTENNADIFFAREA 0.018 ;
		ANTENNAPARTIALMETALAREA 0.025 ;
	END emaw[1]

	PIN gwen
		USE SIGNAL ;
		DIRECTION INPUT ;
		SHAPE ABUTMENT ;
		PORT
			LAYER	M1 ;
			RECT	0 98.025 0.25 98.125 ;
			LAYER	M2 ;
			RECT	0 98.025 0.25 98.125 ;
			LAYER	M3 ;
			RECT	0 98.025 0.25 98.125 ;
		END

		ANTENNAGATEAREA 0.014 ;
		ANTENNADIFFAREA 0.018 ;
		ANTENNAPARTIALMETALAREA 0.025 ;
	END gwen

	PIN q[0]
		USE SIGNAL ;
		DIRECTION OUTPUT ;
		SHAPE ABUTMENT ;
		PORT
			LAYER	M1 ;
			RECT	0 1.995 0.25 2.095 ;
			LAYER	M2 ;
			RECT	0 1.995 0.25 2.095 ;
			LAYER	M3 ;
			RECT	0 1.995 0.25 2.095 ;
		END

		ANTENNADIFFAREA 0.018 ;
		ANTENNAPARTIALMETALAREA 0.025 ;
	END q[0]

	PIN q[100]
		USE SIGNAL ;
		DIRECTION OUTPUT ;
		SHAPE ABUTMENT ;
		PORT
			LAYER	M1 ;
			RECT	0 166.48 0.25 166.58 ;
			LAYER	M2 ;
			RECT	0 166.48 0.25 166.58 ;
			LAYER	M3 ;
			RECT	0 166.48 0.25 166.58 ;
		END

		ANTENNADIFFAREA 0.018 ;
		ANTENNAPARTIALMETALAREA 0.025 ;
	END q[100]

	PIN q[101]
		USE SIGNAL ;
		DIRECTION OUTPUT ;
		SHAPE ABUTMENT ;
		PORT
			LAYER	M1 ;
			RECT	0 167.01 0.25 167.11 ;
			LAYER	M2 ;
			RECT	0 167.01 0.25 167.11 ;
			LAYER	M3 ;
			RECT	0 167.01 0.25 167.11 ;
		END

		ANTENNADIFFAREA 0.018 ;
		ANTENNAPARTIALMETALAREA 0.025 ;
	END q[101]

	PIN q[102]
		USE SIGNAL ;
		DIRECTION OUTPUT ;
		SHAPE ABUTMENT ;
		PORT
			LAYER	M1 ;
			RECT	0 169.32 0.25 169.42 ;
			LAYER	M2 ;
			RECT	0 169.32 0.25 169.42 ;
			LAYER	M3 ;
			RECT	0 169.32 0.25 169.42 ;
		END

		ANTENNADIFFAREA 0.018 ;
		ANTENNAPARTIALMETALAREA 0.025 ;
	END q[102]

	PIN q[103]
		USE SIGNAL ;
		DIRECTION OUTPUT ;
		SHAPE ABUTMENT ;
		PORT
			LAYER	M1 ;
			RECT	0 169.85 0.25 169.95 ;
			LAYER	M2 ;
			RECT	0 169.85 0.25 169.95 ;
			LAYER	M3 ;
			RECT	0 169.85 0.25 169.95 ;
		END

		ANTENNADIFFAREA 0.018 ;
		ANTENNAPARTIALMETALAREA 0.025 ;
	END q[103]

	PIN q[104]
		USE SIGNAL ;
		DIRECTION OUTPUT ;
		SHAPE ABUTMENT ;
		PORT
			LAYER	M1 ;
			RECT	0 172.16 0.25 172.26 ;
			LAYER	M2 ;
			RECT	0 172.16 0.25 172.26 ;
			LAYER	M3 ;
			RECT	0 172.16 0.25 172.26 ;
		END

		ANTENNADIFFAREA 0.018 ;
		ANTENNAPARTIALMETALAREA 0.025 ;
	END q[104]

	PIN q[105]
		USE SIGNAL ;
		DIRECTION OUTPUT ;
		SHAPE ABUTMENT ;
		PORT
			LAYER	M1 ;
			RECT	0 172.69 0.25 172.79 ;
			LAYER	M2 ;
			RECT	0 172.69 0.25 172.79 ;
			LAYER	M3 ;
			RECT	0 172.69 0.25 172.79 ;
		END

		ANTENNADIFFAREA 0.018 ;
		ANTENNAPARTIALMETALAREA 0.025 ;
	END q[105]

	PIN q[106]
		USE SIGNAL ;
		DIRECTION OUTPUT ;
		SHAPE ABUTMENT ;
		PORT
			LAYER	M1 ;
			RECT	0 175 0.25 175.1 ;
			LAYER	M2 ;
			RECT	0 175 0.25 175.1 ;
			LAYER	M3 ;
			RECT	0 175 0.25 175.1 ;
		END

		ANTENNADIFFAREA 0.018 ;
		ANTENNAPARTIALMETALAREA 0.025 ;
	END q[106]

	PIN q[107]
		USE SIGNAL ;
		DIRECTION OUTPUT ;
		SHAPE ABUTMENT ;
		PORT
			LAYER	M1 ;
			RECT	0 175.53 0.25 175.63 ;
			LAYER	M2 ;
			RECT	0 175.53 0.25 175.63 ;
			LAYER	M3 ;
			RECT	0 175.53 0.25 175.63 ;
		END

		ANTENNADIFFAREA 0.018 ;
		ANTENNAPARTIALMETALAREA 0.025 ;
	END q[107]

	PIN q[108]
		USE SIGNAL ;
		DIRECTION OUTPUT ;
		SHAPE ABUTMENT ;
		PORT
			LAYER	M1 ;
			RECT	0 177.84 0.25 177.94 ;
			LAYER	M2 ;
			RECT	0 177.84 0.25 177.94 ;
			LAYER	M3 ;
			RECT	0 177.84 0.25 177.94 ;
		END

		ANTENNADIFFAREA 0.018 ;
		ANTENNAPARTIALMETALAREA 0.025 ;
	END q[108]

	PIN q[109]
		USE SIGNAL ;
		DIRECTION OUTPUT ;
		SHAPE ABUTMENT ;
		PORT
			LAYER	M1 ;
			RECT	0 178.37 0.25 178.47 ;
			LAYER	M2 ;
			RECT	0 178.37 0.25 178.47 ;
			LAYER	M3 ;
			RECT	0 178.37 0.25 178.47 ;
		END

		ANTENNADIFFAREA 0.018 ;
		ANTENNAPARTIALMETALAREA 0.025 ;
	END q[109]

	PIN q[10]
		USE SIGNAL ;
		DIRECTION OUTPUT ;
		SHAPE ABUTMENT ;
		PORT
			LAYER	M1 ;
			RECT	0 16.195 0.25 16.295 ;
			LAYER	M2 ;
			RECT	0 16.195 0.25 16.295 ;
			LAYER	M3 ;
			RECT	0 16.195 0.25 16.295 ;
		END

		ANTENNADIFFAREA 0.018 ;
		ANTENNAPARTIALMETALAREA 0.025 ;
	END q[10]

	PIN q[110]
		USE SIGNAL ;
		DIRECTION OUTPUT ;
		SHAPE ABUTMENT ;
		PORT
			LAYER	M1 ;
			RECT	0 180.68 0.25 180.78 ;
			LAYER	M2 ;
			RECT	0 180.68 0.25 180.78 ;
			LAYER	M3 ;
			RECT	0 180.68 0.25 180.78 ;
		END

		ANTENNADIFFAREA 0.018 ;
		ANTENNAPARTIALMETALAREA 0.025 ;
	END q[110]

	PIN q[111]
		USE SIGNAL ;
		DIRECTION OUTPUT ;
		SHAPE ABUTMENT ;
		PORT
			LAYER	M1 ;
			RECT	0 181.21 0.25 181.31 ;
			LAYER	M2 ;
			RECT	0 181.21 0.25 181.31 ;
			LAYER	M3 ;
			RECT	0 181.21 0.25 181.31 ;
		END

		ANTENNADIFFAREA 0.018 ;
		ANTENNAPARTIALMETALAREA 0.025 ;
	END q[111]

	PIN q[112]
		USE SIGNAL ;
		DIRECTION OUTPUT ;
		SHAPE ABUTMENT ;
		PORT
			LAYER	M1 ;
			RECT	0 183.52 0.25 183.62 ;
			LAYER	M2 ;
			RECT	0 183.52 0.25 183.62 ;
			LAYER	M3 ;
			RECT	0 183.52 0.25 183.62 ;
		END

		ANTENNADIFFAREA 0.018 ;
		ANTENNAPARTIALMETALAREA 0.025 ;
	END q[112]

	PIN q[113]
		USE SIGNAL ;
		DIRECTION OUTPUT ;
		SHAPE ABUTMENT ;
		PORT
			LAYER	M1 ;
			RECT	0 184.05 0.25 184.15 ;
			LAYER	M2 ;
			RECT	0 184.05 0.25 184.15 ;
			LAYER	M3 ;
			RECT	0 184.05 0.25 184.15 ;
		END

		ANTENNADIFFAREA 0.018 ;
		ANTENNAPARTIALMETALAREA 0.025 ;
	END q[113]

	PIN q[114]
		USE SIGNAL ;
		DIRECTION OUTPUT ;
		SHAPE ABUTMENT ;
		PORT
			LAYER	M1 ;
			RECT	0 186.36 0.25 186.46 ;
			LAYER	M2 ;
			RECT	0 186.36 0.25 186.46 ;
			LAYER	M3 ;
			RECT	0 186.36 0.25 186.46 ;
		END

		ANTENNADIFFAREA 0.018 ;
		ANTENNAPARTIALMETALAREA 0.025 ;
	END q[114]

	PIN q[115]
		USE SIGNAL ;
		DIRECTION OUTPUT ;
		SHAPE ABUTMENT ;
		PORT
			LAYER	M1 ;
			RECT	0 186.89 0.25 186.99 ;
			LAYER	M2 ;
			RECT	0 186.89 0.25 186.99 ;
			LAYER	M3 ;
			RECT	0 186.89 0.25 186.99 ;
		END

		ANTENNADIFFAREA 0.018 ;
		ANTENNAPARTIALMETALAREA 0.025 ;
	END q[115]

	PIN q[116]
		USE SIGNAL ;
		DIRECTION OUTPUT ;
		SHAPE ABUTMENT ;
		PORT
			LAYER	M1 ;
			RECT	0 189.2 0.25 189.3 ;
			LAYER	M2 ;
			RECT	0 189.2 0.25 189.3 ;
			LAYER	M3 ;
			RECT	0 189.2 0.25 189.3 ;
		END

		ANTENNADIFFAREA 0.018 ;
		ANTENNAPARTIALMETALAREA 0.025 ;
	END q[116]

	PIN q[117]
		USE SIGNAL ;
		DIRECTION OUTPUT ;
		SHAPE ABUTMENT ;
		PORT
			LAYER	M1 ;
			RECT	0 189.73 0.25 189.83 ;
			LAYER	M2 ;
			RECT	0 189.73 0.25 189.83 ;
			LAYER	M3 ;
			RECT	0 189.73 0.25 189.83 ;
		END

		ANTENNADIFFAREA 0.018 ;
		ANTENNAPARTIALMETALAREA 0.025 ;
	END q[117]

	PIN q[118]
		USE SIGNAL ;
		DIRECTION OUTPUT ;
		SHAPE ABUTMENT ;
		PORT
			LAYER	M1 ;
			RECT	0 192.04 0.25 192.14 ;
			LAYER	M2 ;
			RECT	0 192.04 0.25 192.14 ;
			LAYER	M3 ;
			RECT	0 192.04 0.25 192.14 ;
		END

		ANTENNADIFFAREA 0.018 ;
		ANTENNAPARTIALMETALAREA 0.025 ;
	END q[118]

	PIN q[119]
		USE SIGNAL ;
		DIRECTION OUTPUT ;
		SHAPE ABUTMENT ;
		PORT
			LAYER	M1 ;
			RECT	0 192.57 0.25 192.67 ;
			LAYER	M2 ;
			RECT	0 192.57 0.25 192.67 ;
			LAYER	M3 ;
			RECT	0 192.57 0.25 192.67 ;
		END

		ANTENNADIFFAREA 0.018 ;
		ANTENNAPARTIALMETALAREA 0.025 ;
	END q[119]

	PIN q[11]
		USE SIGNAL ;
		DIRECTION OUTPUT ;
		SHAPE ABUTMENT ;
		PORT
			LAYER	M1 ;
			RECT	0 16.725 0.25 16.825 ;
			LAYER	M2 ;
			RECT	0 16.725 0.25 16.825 ;
			LAYER	M3 ;
			RECT	0 16.725 0.25 16.825 ;
		END

		ANTENNADIFFAREA 0.018 ;
		ANTENNAPARTIALMETALAREA 0.025 ;
	END q[11]

	PIN q[120]
		USE SIGNAL ;
		DIRECTION OUTPUT ;
		SHAPE ABUTMENT ;
		PORT
			LAYER	M1 ;
			RECT	0 194.88 0.25 194.98 ;
			LAYER	M2 ;
			RECT	0 194.88 0.25 194.98 ;
			LAYER	M3 ;
			RECT	0 194.88 0.25 194.98 ;
		END

		ANTENNADIFFAREA 0.018 ;
		ANTENNAPARTIALMETALAREA 0.025 ;
	END q[120]

	PIN q[121]
		USE SIGNAL ;
		DIRECTION OUTPUT ;
		SHAPE ABUTMENT ;
		PORT
			LAYER	M1 ;
			RECT	0 195.41 0.25 195.51 ;
			LAYER	M2 ;
			RECT	0 195.41 0.25 195.51 ;
			LAYER	M3 ;
			RECT	0 195.41 0.25 195.51 ;
		END

		ANTENNADIFFAREA 0.018 ;
		ANTENNAPARTIALMETALAREA 0.025 ;
	END q[121]

	PIN q[122]
		USE SIGNAL ;
		DIRECTION OUTPUT ;
		SHAPE ABUTMENT ;
		PORT
			LAYER	M1 ;
			RECT	0 197.72 0.25 197.82 ;
			LAYER	M2 ;
			RECT	0 197.72 0.25 197.82 ;
			LAYER	M3 ;
			RECT	0 197.72 0.25 197.82 ;
		END

		ANTENNADIFFAREA 0.018 ;
		ANTENNAPARTIALMETALAREA 0.025 ;
	END q[122]

	PIN q[123]
		USE SIGNAL ;
		DIRECTION OUTPUT ;
		SHAPE ABUTMENT ;
		PORT
			LAYER	M1 ;
			RECT	0 198.25 0.25 198.35 ;
			LAYER	M2 ;
			RECT	0 198.25 0.25 198.35 ;
			LAYER	M3 ;
			RECT	0 198.25 0.25 198.35 ;
		END

		ANTENNADIFFAREA 0.018 ;
		ANTENNAPARTIALMETALAREA 0.025 ;
	END q[123]

	PIN q[124]
		USE SIGNAL ;
		DIRECTION OUTPUT ;
		SHAPE ABUTMENT ;
		PORT
			LAYER	M1 ;
			RECT	0 200.56 0.25 200.66 ;
			LAYER	M2 ;
			RECT	0 200.56 0.25 200.66 ;
			LAYER	M3 ;
			RECT	0 200.56 0.25 200.66 ;
		END

		ANTENNADIFFAREA 0.018 ;
		ANTENNAPARTIALMETALAREA 0.025 ;
	END q[124]

	PIN q[125]
		USE SIGNAL ;
		DIRECTION OUTPUT ;
		SHAPE ABUTMENT ;
		PORT
			LAYER	M1 ;
			RECT	0 201.09 0.25 201.19 ;
			LAYER	M2 ;
			RECT	0 201.09 0.25 201.19 ;
			LAYER	M3 ;
			RECT	0 201.09 0.25 201.19 ;
		END

		ANTENNADIFFAREA 0.018 ;
		ANTENNAPARTIALMETALAREA 0.025 ;
	END q[125]

	PIN q[126]
		USE SIGNAL ;
		DIRECTION OUTPUT ;
		SHAPE ABUTMENT ;
		PORT
			LAYER	M1 ;
			RECT	0 203.4 0.25 203.5 ;
			LAYER	M2 ;
			RECT	0 203.4 0.25 203.5 ;
			LAYER	M3 ;
			RECT	0 203.4 0.25 203.5 ;
		END

		ANTENNADIFFAREA 0.018 ;
		ANTENNAPARTIALMETALAREA 0.025 ;
	END q[126]

	PIN q[127]
		USE SIGNAL ;
		DIRECTION OUTPUT ;
		SHAPE ABUTMENT ;
		PORT
			LAYER	M1 ;
			RECT	0 203.93 0.25 204.03 ;
			LAYER	M2 ;
			RECT	0 203.93 0.25 204.03 ;
			LAYER	M3 ;
			RECT	0 203.93 0.25 204.03 ;
		END

		ANTENNADIFFAREA 0.018 ;
		ANTENNAPARTIALMETALAREA 0.025 ;
	END q[127]

	PIN q[12]
		USE SIGNAL ;
		DIRECTION OUTPUT ;
		SHAPE ABUTMENT ;
		PORT
			LAYER	M1 ;
			RECT	0 19.035 0.25 19.135 ;
			LAYER	M2 ;
			RECT	0 19.035 0.25 19.135 ;
			LAYER	M3 ;
			RECT	0 19.035 0.25 19.135 ;
		END

		ANTENNADIFFAREA 0.018 ;
		ANTENNAPARTIALMETALAREA 0.025 ;
	END q[12]

	PIN q[13]
		USE SIGNAL ;
		DIRECTION OUTPUT ;
		SHAPE ABUTMENT ;
		PORT
			LAYER	M1 ;
			RECT	0 19.565 0.25 19.665 ;
			LAYER	M2 ;
			RECT	0 19.565 0.25 19.665 ;
			LAYER	M3 ;
			RECT	0 19.565 0.25 19.665 ;
		END

		ANTENNADIFFAREA 0.018 ;
		ANTENNAPARTIALMETALAREA 0.025 ;
	END q[13]

	PIN q[14]
		USE SIGNAL ;
		DIRECTION OUTPUT ;
		SHAPE ABUTMENT ;
		PORT
			LAYER	M1 ;
			RECT	0 21.875 0.25 21.975 ;
			LAYER	M2 ;
			RECT	0 21.875 0.25 21.975 ;
			LAYER	M3 ;
			RECT	0 21.875 0.25 21.975 ;
		END

		ANTENNADIFFAREA 0.018 ;
		ANTENNAPARTIALMETALAREA 0.025 ;
	END q[14]

	PIN q[15]
		USE SIGNAL ;
		DIRECTION OUTPUT ;
		SHAPE ABUTMENT ;
		PORT
			LAYER	M1 ;
			RECT	0 22.405 0.25 22.505 ;
			LAYER	M2 ;
			RECT	0 22.405 0.25 22.505 ;
			LAYER	M3 ;
			RECT	0 22.405 0.25 22.505 ;
		END

		ANTENNADIFFAREA 0.018 ;
		ANTENNAPARTIALMETALAREA 0.025 ;
	END q[15]

	PIN q[16]
		USE SIGNAL ;
		DIRECTION OUTPUT ;
		SHAPE ABUTMENT ;
		PORT
			LAYER	M1 ;
			RECT	0 24.715 0.25 24.815 ;
			LAYER	M2 ;
			RECT	0 24.715 0.25 24.815 ;
			LAYER	M3 ;
			RECT	0 24.715 0.25 24.815 ;
		END

		ANTENNADIFFAREA 0.018 ;
		ANTENNAPARTIALMETALAREA 0.025 ;
	END q[16]

	PIN q[17]
		USE SIGNAL ;
		DIRECTION OUTPUT ;
		SHAPE ABUTMENT ;
		PORT
			LAYER	M1 ;
			RECT	0 25.245 0.25 25.345 ;
			LAYER	M2 ;
			RECT	0 25.245 0.25 25.345 ;
			LAYER	M3 ;
			RECT	0 25.245 0.25 25.345 ;
		END

		ANTENNADIFFAREA 0.018 ;
		ANTENNAPARTIALMETALAREA 0.025 ;
	END q[17]

	PIN q[18]
		USE SIGNAL ;
		DIRECTION OUTPUT ;
		SHAPE ABUTMENT ;
		PORT
			LAYER	M1 ;
			RECT	0 27.555 0.25 27.655 ;
			LAYER	M2 ;
			RECT	0 27.555 0.25 27.655 ;
			LAYER	M3 ;
			RECT	0 27.555 0.25 27.655 ;
		END

		ANTENNADIFFAREA 0.018 ;
		ANTENNAPARTIALMETALAREA 0.025 ;
	END q[18]

	PIN q[19]
		USE SIGNAL ;
		DIRECTION OUTPUT ;
		SHAPE ABUTMENT ;
		PORT
			LAYER	M1 ;
			RECT	0 28.085 0.25 28.185 ;
			LAYER	M2 ;
			RECT	0 28.085 0.25 28.185 ;
			LAYER	M3 ;
			RECT	0 28.085 0.25 28.185 ;
		END

		ANTENNADIFFAREA 0.018 ;
		ANTENNAPARTIALMETALAREA 0.025 ;
	END q[19]

	PIN q[1]
		USE SIGNAL ;
		DIRECTION OUTPUT ;
		SHAPE ABUTMENT ;
		PORT
			LAYER	M1 ;
			RECT	0 2.525 0.25 2.625 ;
			LAYER	M2 ;
			RECT	0 2.525 0.25 2.625 ;
			LAYER	M3 ;
			RECT	0 2.525 0.25 2.625 ;
		END

		ANTENNADIFFAREA 0.018 ;
		ANTENNAPARTIALMETALAREA 0.025 ;
	END q[1]

	PIN q[20]
		USE SIGNAL ;
		DIRECTION OUTPUT ;
		SHAPE ABUTMENT ;
		PORT
			LAYER	M1 ;
			RECT	0 30.395 0.25 30.495 ;
			LAYER	M2 ;
			RECT	0 30.395 0.25 30.495 ;
			LAYER	M3 ;
			RECT	0 30.395 0.25 30.495 ;
		END

		ANTENNADIFFAREA 0.018 ;
		ANTENNAPARTIALMETALAREA 0.025 ;
	END q[20]

	PIN q[21]
		USE SIGNAL ;
		DIRECTION OUTPUT ;
		SHAPE ABUTMENT ;
		PORT
			LAYER	M1 ;
			RECT	0 30.925 0.25 31.025 ;
			LAYER	M2 ;
			RECT	0 30.925 0.25 31.025 ;
			LAYER	M3 ;
			RECT	0 30.925 0.25 31.025 ;
		END

		ANTENNADIFFAREA 0.018 ;
		ANTENNAPARTIALMETALAREA 0.025 ;
	END q[21]

	PIN q[22]
		USE SIGNAL ;
		DIRECTION OUTPUT ;
		SHAPE ABUTMENT ;
		PORT
			LAYER	M1 ;
			RECT	0 33.235 0.25 33.335 ;
			LAYER	M2 ;
			RECT	0 33.235 0.25 33.335 ;
			LAYER	M3 ;
			RECT	0 33.235 0.25 33.335 ;
		END

		ANTENNADIFFAREA 0.018 ;
		ANTENNAPARTIALMETALAREA 0.025 ;
	END q[22]

	PIN q[23]
		USE SIGNAL ;
		DIRECTION OUTPUT ;
		SHAPE ABUTMENT ;
		PORT
			LAYER	M1 ;
			RECT	0 33.765 0.25 33.865 ;
			LAYER	M2 ;
			RECT	0 33.765 0.25 33.865 ;
			LAYER	M3 ;
			RECT	0 33.765 0.25 33.865 ;
		END

		ANTENNADIFFAREA 0.018 ;
		ANTENNAPARTIALMETALAREA 0.025 ;
	END q[23]

	PIN q[24]
		USE SIGNAL ;
		DIRECTION OUTPUT ;
		SHAPE ABUTMENT ;
		PORT
			LAYER	M1 ;
			RECT	0 36.075 0.25 36.175 ;
			LAYER	M2 ;
			RECT	0 36.075 0.25 36.175 ;
			LAYER	M3 ;
			RECT	0 36.075 0.25 36.175 ;
		END

		ANTENNADIFFAREA 0.018 ;
		ANTENNAPARTIALMETALAREA 0.025 ;
	END q[24]

	PIN q[25]
		USE SIGNAL ;
		DIRECTION OUTPUT ;
		SHAPE ABUTMENT ;
		PORT
			LAYER	M1 ;
			RECT	0 36.605 0.25 36.705 ;
			LAYER	M2 ;
			RECT	0 36.605 0.25 36.705 ;
			LAYER	M3 ;
			RECT	0 36.605 0.25 36.705 ;
		END

		ANTENNADIFFAREA 0.018 ;
		ANTENNAPARTIALMETALAREA 0.025 ;
	END q[25]

	PIN q[26]
		USE SIGNAL ;
		DIRECTION OUTPUT ;
		SHAPE ABUTMENT ;
		PORT
			LAYER	M1 ;
			RECT	0 38.915 0.25 39.015 ;
			LAYER	M2 ;
			RECT	0 38.915 0.25 39.015 ;
			LAYER	M3 ;
			RECT	0 38.915 0.25 39.015 ;
		END

		ANTENNADIFFAREA 0.018 ;
		ANTENNAPARTIALMETALAREA 0.025 ;
	END q[26]

	PIN q[27]
		USE SIGNAL ;
		DIRECTION OUTPUT ;
		SHAPE ABUTMENT ;
		PORT
			LAYER	M1 ;
			RECT	0 39.445 0.25 39.545 ;
			LAYER	M2 ;
			RECT	0 39.445 0.25 39.545 ;
			LAYER	M3 ;
			RECT	0 39.445 0.25 39.545 ;
		END

		ANTENNADIFFAREA 0.018 ;
		ANTENNAPARTIALMETALAREA 0.025 ;
	END q[27]

	PIN q[28]
		USE SIGNAL ;
		DIRECTION OUTPUT ;
		SHAPE ABUTMENT ;
		PORT
			LAYER	M1 ;
			RECT	0 41.755 0.25 41.855 ;
			LAYER	M2 ;
			RECT	0 41.755 0.25 41.855 ;
			LAYER	M3 ;
			RECT	0 41.755 0.25 41.855 ;
		END

		ANTENNADIFFAREA 0.018 ;
		ANTENNAPARTIALMETALAREA 0.025 ;
	END q[28]

	PIN q[29]
		USE SIGNAL ;
		DIRECTION OUTPUT ;
		SHAPE ABUTMENT ;
		PORT
			LAYER	M1 ;
			RECT	0 42.285 0.25 42.385 ;
			LAYER	M2 ;
			RECT	0 42.285 0.25 42.385 ;
			LAYER	M3 ;
			RECT	0 42.285 0.25 42.385 ;
		END

		ANTENNADIFFAREA 0.018 ;
		ANTENNAPARTIALMETALAREA 0.025 ;
	END q[29]

	PIN q[2]
		USE SIGNAL ;
		DIRECTION OUTPUT ;
		SHAPE ABUTMENT ;
		PORT
			LAYER	M1 ;
			RECT	0 4.835 0.25 4.935 ;
			LAYER	M2 ;
			RECT	0 4.835 0.25 4.935 ;
			LAYER	M3 ;
			RECT	0 4.835 0.25 4.935 ;
		END

		ANTENNADIFFAREA 0.018 ;
		ANTENNAPARTIALMETALAREA 0.025 ;
	END q[2]

	PIN q[30]
		USE SIGNAL ;
		DIRECTION OUTPUT ;
		SHAPE ABUTMENT ;
		PORT
			LAYER	M1 ;
			RECT	0 44.595 0.25 44.695 ;
			LAYER	M2 ;
			RECT	0 44.595 0.25 44.695 ;
			LAYER	M3 ;
			RECT	0 44.595 0.25 44.695 ;
		END

		ANTENNADIFFAREA 0.018 ;
		ANTENNAPARTIALMETALAREA 0.025 ;
	END q[30]

	PIN q[31]
		USE SIGNAL ;
		DIRECTION OUTPUT ;
		SHAPE ABUTMENT ;
		PORT
			LAYER	M1 ;
			RECT	0 45.125 0.25 45.225 ;
			LAYER	M2 ;
			RECT	0 45.125 0.25 45.225 ;
			LAYER	M3 ;
			RECT	0 45.125 0.25 45.225 ;
		END

		ANTENNADIFFAREA 0.018 ;
		ANTENNAPARTIALMETALAREA 0.025 ;
	END q[31]

	PIN q[32]
		USE SIGNAL ;
		DIRECTION OUTPUT ;
		SHAPE ABUTMENT ;
		PORT
			LAYER	M1 ;
			RECT	0 47.435 0.25 47.535 ;
			LAYER	M2 ;
			RECT	0 47.435 0.25 47.535 ;
			LAYER	M3 ;
			RECT	0 47.435 0.25 47.535 ;
		END

		ANTENNADIFFAREA 0.018 ;
		ANTENNAPARTIALMETALAREA 0.025 ;
	END q[32]

	PIN q[33]
		USE SIGNAL ;
		DIRECTION OUTPUT ;
		SHAPE ABUTMENT ;
		PORT
			LAYER	M1 ;
			RECT	0 47.965 0.25 48.065 ;
			LAYER	M2 ;
			RECT	0 47.965 0.25 48.065 ;
			LAYER	M3 ;
			RECT	0 47.965 0.25 48.065 ;
		END

		ANTENNADIFFAREA 0.018 ;
		ANTENNAPARTIALMETALAREA 0.025 ;
	END q[33]

	PIN q[34]
		USE SIGNAL ;
		DIRECTION OUTPUT ;
		SHAPE ABUTMENT ;
		PORT
			LAYER	M1 ;
			RECT	0 50.275 0.25 50.375 ;
			LAYER	M2 ;
			RECT	0 50.275 0.25 50.375 ;
			LAYER	M3 ;
			RECT	0 50.275 0.25 50.375 ;
		END

		ANTENNADIFFAREA 0.018 ;
		ANTENNAPARTIALMETALAREA 0.025 ;
	END q[34]

	PIN q[35]
		USE SIGNAL ;
		DIRECTION OUTPUT ;
		SHAPE ABUTMENT ;
		PORT
			LAYER	M1 ;
			RECT	0 50.805 0.25 50.905 ;
			LAYER	M2 ;
			RECT	0 50.805 0.25 50.905 ;
			LAYER	M3 ;
			RECT	0 50.805 0.25 50.905 ;
		END

		ANTENNADIFFAREA 0.018 ;
		ANTENNAPARTIALMETALAREA 0.025 ;
	END q[35]

	PIN q[36]
		USE SIGNAL ;
		DIRECTION OUTPUT ;
		SHAPE ABUTMENT ;
		PORT
			LAYER	M1 ;
			RECT	0 53.115 0.25 53.215 ;
			LAYER	M2 ;
			RECT	0 53.115 0.25 53.215 ;
			LAYER	M3 ;
			RECT	0 53.115 0.25 53.215 ;
		END

		ANTENNADIFFAREA 0.018 ;
		ANTENNAPARTIALMETALAREA 0.025 ;
	END q[36]

	PIN q[37]
		USE SIGNAL ;
		DIRECTION OUTPUT ;
		SHAPE ABUTMENT ;
		PORT
			LAYER	M1 ;
			RECT	0 53.645 0.25 53.745 ;
			LAYER	M2 ;
			RECT	0 53.645 0.25 53.745 ;
			LAYER	M3 ;
			RECT	0 53.645 0.25 53.745 ;
		END

		ANTENNADIFFAREA 0.018 ;
		ANTENNAPARTIALMETALAREA 0.025 ;
	END q[37]

	PIN q[38]
		USE SIGNAL ;
		DIRECTION OUTPUT ;
		SHAPE ABUTMENT ;
		PORT
			LAYER	M1 ;
			RECT	0 55.955 0.25 56.055 ;
			LAYER	M2 ;
			RECT	0 55.955 0.25 56.055 ;
			LAYER	M3 ;
			RECT	0 55.955 0.25 56.055 ;
		END

		ANTENNADIFFAREA 0.018 ;
		ANTENNAPARTIALMETALAREA 0.025 ;
	END q[38]

	PIN q[39]
		USE SIGNAL ;
		DIRECTION OUTPUT ;
		SHAPE ABUTMENT ;
		PORT
			LAYER	M1 ;
			RECT	0 56.485 0.25 56.585 ;
			LAYER	M2 ;
			RECT	0 56.485 0.25 56.585 ;
			LAYER	M3 ;
			RECT	0 56.485 0.25 56.585 ;
		END

		ANTENNADIFFAREA 0.018 ;
		ANTENNAPARTIALMETALAREA 0.025 ;
	END q[39]

	PIN q[3]
		USE SIGNAL ;
		DIRECTION OUTPUT ;
		SHAPE ABUTMENT ;
		PORT
			LAYER	M1 ;
			RECT	0 5.365 0.25 5.465 ;
			LAYER	M2 ;
			RECT	0 5.365 0.25 5.465 ;
			LAYER	M3 ;
			RECT	0 5.365 0.25 5.465 ;
		END

		ANTENNADIFFAREA 0.018 ;
		ANTENNAPARTIALMETALAREA 0.025 ;
	END q[3]

	PIN q[40]
		USE SIGNAL ;
		DIRECTION OUTPUT ;
		SHAPE ABUTMENT ;
		PORT
			LAYER	M1 ;
			RECT	0 58.795 0.25 58.895 ;
			LAYER	M2 ;
			RECT	0 58.795 0.25 58.895 ;
			LAYER	M3 ;
			RECT	0 58.795 0.25 58.895 ;
		END

		ANTENNADIFFAREA 0.018 ;
		ANTENNAPARTIALMETALAREA 0.025 ;
	END q[40]

	PIN q[41]
		USE SIGNAL ;
		DIRECTION OUTPUT ;
		SHAPE ABUTMENT ;
		PORT
			LAYER	M1 ;
			RECT	0 59.325 0.25 59.425 ;
			LAYER	M2 ;
			RECT	0 59.325 0.25 59.425 ;
			LAYER	M3 ;
			RECT	0 59.325 0.25 59.425 ;
		END

		ANTENNADIFFAREA 0.018 ;
		ANTENNAPARTIALMETALAREA 0.025 ;
	END q[41]

	PIN q[42]
		USE SIGNAL ;
		DIRECTION OUTPUT ;
		SHAPE ABUTMENT ;
		PORT
			LAYER	M1 ;
			RECT	0 61.635 0.25 61.735 ;
			LAYER	M2 ;
			RECT	0 61.635 0.25 61.735 ;
			LAYER	M3 ;
			RECT	0 61.635 0.25 61.735 ;
		END

		ANTENNADIFFAREA 0.018 ;
		ANTENNAPARTIALMETALAREA 0.025 ;
	END q[42]

	PIN q[43]
		USE SIGNAL ;
		DIRECTION OUTPUT ;
		SHAPE ABUTMENT ;
		PORT
			LAYER	M1 ;
			RECT	0 62.165 0.25 62.265 ;
			LAYER	M2 ;
			RECT	0 62.165 0.25 62.265 ;
			LAYER	M3 ;
			RECT	0 62.165 0.25 62.265 ;
		END

		ANTENNADIFFAREA 0.018 ;
		ANTENNAPARTIALMETALAREA 0.025 ;
	END q[43]

	PIN q[44]
		USE SIGNAL ;
		DIRECTION OUTPUT ;
		SHAPE ABUTMENT ;
		PORT
			LAYER	M1 ;
			RECT	0 64.475 0.25 64.575 ;
			LAYER	M2 ;
			RECT	0 64.475 0.25 64.575 ;
			LAYER	M3 ;
			RECT	0 64.475 0.25 64.575 ;
		END

		ANTENNADIFFAREA 0.018 ;
		ANTENNAPARTIALMETALAREA 0.025 ;
	END q[44]

	PIN q[45]
		USE SIGNAL ;
		DIRECTION OUTPUT ;
		SHAPE ABUTMENT ;
		PORT
			LAYER	M1 ;
			RECT	0 65.005 0.25 65.105 ;
			LAYER	M2 ;
			RECT	0 65.005 0.25 65.105 ;
			LAYER	M3 ;
			RECT	0 65.005 0.25 65.105 ;
		END

		ANTENNADIFFAREA 0.018 ;
		ANTENNAPARTIALMETALAREA 0.025 ;
	END q[45]

	PIN q[46]
		USE SIGNAL ;
		DIRECTION OUTPUT ;
		SHAPE ABUTMENT ;
		PORT
			LAYER	M1 ;
			RECT	0 67.315 0.25 67.415 ;
			LAYER	M2 ;
			RECT	0 67.315 0.25 67.415 ;
			LAYER	M3 ;
			RECT	0 67.315 0.25 67.415 ;
		END

		ANTENNADIFFAREA 0.018 ;
		ANTENNAPARTIALMETALAREA 0.025 ;
	END q[46]

	PIN q[47]
		USE SIGNAL ;
		DIRECTION OUTPUT ;
		SHAPE ABUTMENT ;
		PORT
			LAYER	M1 ;
			RECT	0 67.845 0.25 67.945 ;
			LAYER	M2 ;
			RECT	0 67.845 0.25 67.945 ;
			LAYER	M3 ;
			RECT	0 67.845 0.25 67.945 ;
		END

		ANTENNADIFFAREA 0.018 ;
		ANTENNAPARTIALMETALAREA 0.025 ;
	END q[47]

	PIN q[48]
		USE SIGNAL ;
		DIRECTION OUTPUT ;
		SHAPE ABUTMENT ;
		PORT
			LAYER	M1 ;
			RECT	0 70.155 0.25 70.255 ;
			LAYER	M2 ;
			RECT	0 70.155 0.25 70.255 ;
			LAYER	M3 ;
			RECT	0 70.155 0.25 70.255 ;
		END

		ANTENNADIFFAREA 0.018 ;
		ANTENNAPARTIALMETALAREA 0.025 ;
	END q[48]

	PIN q[49]
		USE SIGNAL ;
		DIRECTION OUTPUT ;
		SHAPE ABUTMENT ;
		PORT
			LAYER	M1 ;
			RECT	0 70.685 0.25 70.785 ;
			LAYER	M2 ;
			RECT	0 70.685 0.25 70.785 ;
			LAYER	M3 ;
			RECT	0 70.685 0.25 70.785 ;
		END

		ANTENNADIFFAREA 0.018 ;
		ANTENNAPARTIALMETALAREA 0.025 ;
	END q[49]

	PIN q[4]
		USE SIGNAL ;
		DIRECTION OUTPUT ;
		SHAPE ABUTMENT ;
		PORT
			LAYER	M1 ;
			RECT	0 7.675 0.25 7.775 ;
			LAYER	M2 ;
			RECT	0 7.675 0.25 7.775 ;
			LAYER	M3 ;
			RECT	0 7.675 0.25 7.775 ;
		END

		ANTENNADIFFAREA 0.018 ;
		ANTENNAPARTIALMETALAREA 0.025 ;
	END q[4]

	PIN q[50]
		USE SIGNAL ;
		DIRECTION OUTPUT ;
		SHAPE ABUTMENT ;
		PORT
			LAYER	M1 ;
			RECT	0 72.995 0.25 73.095 ;
			LAYER	M2 ;
			RECT	0 72.995 0.25 73.095 ;
			LAYER	M3 ;
			RECT	0 72.995 0.25 73.095 ;
		END

		ANTENNADIFFAREA 0.018 ;
		ANTENNAPARTIALMETALAREA 0.025 ;
	END q[50]

	PIN q[51]
		USE SIGNAL ;
		DIRECTION OUTPUT ;
		SHAPE ABUTMENT ;
		PORT
			LAYER	M1 ;
			RECT	0 73.525 0.25 73.625 ;
			LAYER	M2 ;
			RECT	0 73.525 0.25 73.625 ;
			LAYER	M3 ;
			RECT	0 73.525 0.25 73.625 ;
		END

		ANTENNADIFFAREA 0.018 ;
		ANTENNAPARTIALMETALAREA 0.025 ;
	END q[51]

	PIN q[52]
		USE SIGNAL ;
		DIRECTION OUTPUT ;
		SHAPE ABUTMENT ;
		PORT
			LAYER	M1 ;
			RECT	0 75.835 0.25 75.935 ;
			LAYER	M2 ;
			RECT	0 75.835 0.25 75.935 ;
			LAYER	M3 ;
			RECT	0 75.835 0.25 75.935 ;
		END

		ANTENNADIFFAREA 0.018 ;
		ANTENNAPARTIALMETALAREA 0.025 ;
	END q[52]

	PIN q[53]
		USE SIGNAL ;
		DIRECTION OUTPUT ;
		SHAPE ABUTMENT ;
		PORT
			LAYER	M1 ;
			RECT	0 76.365 0.25 76.465 ;
			LAYER	M2 ;
			RECT	0 76.365 0.25 76.465 ;
			LAYER	M3 ;
			RECT	0 76.365 0.25 76.465 ;
		END

		ANTENNADIFFAREA 0.018 ;
		ANTENNAPARTIALMETALAREA 0.025 ;
	END q[53]

	PIN q[54]
		USE SIGNAL ;
		DIRECTION OUTPUT ;
		SHAPE ABUTMENT ;
		PORT
			LAYER	M1 ;
			RECT	0 78.675 0.25 78.775 ;
			LAYER	M2 ;
			RECT	0 78.675 0.25 78.775 ;
			LAYER	M3 ;
			RECT	0 78.675 0.25 78.775 ;
		END

		ANTENNADIFFAREA 0.018 ;
		ANTENNAPARTIALMETALAREA 0.025 ;
	END q[54]

	PIN q[55]
		USE SIGNAL ;
		DIRECTION OUTPUT ;
		SHAPE ABUTMENT ;
		PORT
			LAYER	M1 ;
			RECT	0 79.205 0.25 79.305 ;
			LAYER	M2 ;
			RECT	0 79.205 0.25 79.305 ;
			LAYER	M3 ;
			RECT	0 79.205 0.25 79.305 ;
		END

		ANTENNADIFFAREA 0.018 ;
		ANTENNAPARTIALMETALAREA 0.025 ;
	END q[55]

	PIN q[56]
		USE SIGNAL ;
		DIRECTION OUTPUT ;
		SHAPE ABUTMENT ;
		PORT
			LAYER	M1 ;
			RECT	0 81.515 0.25 81.615 ;
			LAYER	M2 ;
			RECT	0 81.515 0.25 81.615 ;
			LAYER	M3 ;
			RECT	0 81.515 0.25 81.615 ;
		END

		ANTENNADIFFAREA 0.018 ;
		ANTENNAPARTIALMETALAREA 0.025 ;
	END q[56]

	PIN q[57]
		USE SIGNAL ;
		DIRECTION OUTPUT ;
		SHAPE ABUTMENT ;
		PORT
			LAYER	M1 ;
			RECT	0 82.045 0.25 82.145 ;
			LAYER	M2 ;
			RECT	0 82.045 0.25 82.145 ;
			LAYER	M3 ;
			RECT	0 82.045 0.25 82.145 ;
		END

		ANTENNADIFFAREA 0.018 ;
		ANTENNAPARTIALMETALAREA 0.025 ;
	END q[57]

	PIN q[58]
		USE SIGNAL ;
		DIRECTION OUTPUT ;
		SHAPE ABUTMENT ;
		PORT
			LAYER	M1 ;
			RECT	0 84.355 0.25 84.455 ;
			LAYER	M2 ;
			RECT	0 84.355 0.25 84.455 ;
			LAYER	M3 ;
			RECT	0 84.355 0.25 84.455 ;
		END

		ANTENNADIFFAREA 0.018 ;
		ANTENNAPARTIALMETALAREA 0.025 ;
	END q[58]

	PIN q[59]
		USE SIGNAL ;
		DIRECTION OUTPUT ;
		SHAPE ABUTMENT ;
		PORT
			LAYER	M1 ;
			RECT	0 84.885 0.25 84.985 ;
			LAYER	M2 ;
			RECT	0 84.885 0.25 84.985 ;
			LAYER	M3 ;
			RECT	0 84.885 0.25 84.985 ;
		END

		ANTENNADIFFAREA 0.018 ;
		ANTENNAPARTIALMETALAREA 0.025 ;
	END q[59]

	PIN q[5]
		USE SIGNAL ;
		DIRECTION OUTPUT ;
		SHAPE ABUTMENT ;
		PORT
			LAYER	M1 ;
			RECT	0 8.205 0.25 8.305 ;
			LAYER	M2 ;
			RECT	0 8.205 0.25 8.305 ;
			LAYER	M3 ;
			RECT	0 8.205 0.25 8.305 ;
		END

		ANTENNADIFFAREA 0.018 ;
		ANTENNAPARTIALMETALAREA 0.025 ;
	END q[5]

	PIN q[60]
		USE SIGNAL ;
		DIRECTION OUTPUT ;
		SHAPE ABUTMENT ;
		PORT
			LAYER	M1 ;
			RECT	0 87.195 0.25 87.295 ;
			LAYER	M2 ;
			RECT	0 87.195 0.25 87.295 ;
			LAYER	M3 ;
			RECT	0 87.195 0.25 87.295 ;
		END

		ANTENNADIFFAREA 0.018 ;
		ANTENNAPARTIALMETALAREA 0.025 ;
	END q[60]

	PIN q[61]
		USE SIGNAL ;
		DIRECTION OUTPUT ;
		SHAPE ABUTMENT ;
		PORT
			LAYER	M1 ;
			RECT	0 87.725 0.25 87.825 ;
			LAYER	M2 ;
			RECT	0 87.725 0.25 87.825 ;
			LAYER	M3 ;
			RECT	0 87.725 0.25 87.825 ;
		END

		ANTENNADIFFAREA 0.018 ;
		ANTENNAPARTIALMETALAREA 0.025 ;
	END q[61]

	PIN q[62]
		USE SIGNAL ;
		DIRECTION OUTPUT ;
		SHAPE ABUTMENT ;
		PORT
			LAYER	M1 ;
			RECT	0 90.035 0.25 90.135 ;
			LAYER	M2 ;
			RECT	0 90.035 0.25 90.135 ;
			LAYER	M3 ;
			RECT	0 90.035 0.25 90.135 ;
		END

		ANTENNADIFFAREA 0.018 ;
		ANTENNAPARTIALMETALAREA 0.025 ;
	END q[62]

	PIN q[63]
		USE SIGNAL ;
		DIRECTION OUTPUT ;
		SHAPE ABUTMENT ;
		PORT
			LAYER	M1 ;
			RECT	0 90.565 0.25 90.665 ;
			LAYER	M2 ;
			RECT	0 90.565 0.25 90.665 ;
			LAYER	M3 ;
			RECT	0 90.565 0.25 90.665 ;
		END

		ANTENNADIFFAREA 0.018 ;
		ANTENNAPARTIALMETALAREA 0.025 ;
	END q[63]

	PIN q[64]
		USE SIGNAL ;
		DIRECTION OUTPUT ;
		SHAPE ABUTMENT ;
		PORT
			LAYER	M1 ;
			RECT	0 115.36 0.25 115.46 ;
			LAYER	M2 ;
			RECT	0 115.36 0.25 115.46 ;
			LAYER	M3 ;
			RECT	0 115.36 0.25 115.46 ;
		END

		ANTENNADIFFAREA 0.018 ;
		ANTENNAPARTIALMETALAREA 0.025 ;
	END q[64]

	PIN q[65]
		USE SIGNAL ;
		DIRECTION OUTPUT ;
		SHAPE ABUTMENT ;
		PORT
			LAYER	M1 ;
			RECT	0 115.89 0.25 115.99 ;
			LAYER	M2 ;
			RECT	0 115.89 0.25 115.99 ;
			LAYER	M3 ;
			RECT	0 115.89 0.25 115.99 ;
		END

		ANTENNADIFFAREA 0.018 ;
		ANTENNAPARTIALMETALAREA 0.025 ;
	END q[65]

	PIN q[66]
		USE SIGNAL ;
		DIRECTION OUTPUT ;
		SHAPE ABUTMENT ;
		PORT
			LAYER	M1 ;
			RECT	0 118.2 0.25 118.3 ;
			LAYER	M2 ;
			RECT	0 118.2 0.25 118.3 ;
			LAYER	M3 ;
			RECT	0 118.2 0.25 118.3 ;
		END

		ANTENNADIFFAREA 0.018 ;
		ANTENNAPARTIALMETALAREA 0.025 ;
	END q[66]

	PIN q[67]
		USE SIGNAL ;
		DIRECTION OUTPUT ;
		SHAPE ABUTMENT ;
		PORT
			LAYER	M1 ;
			RECT	0 118.73 0.25 118.83 ;
			LAYER	M2 ;
			RECT	0 118.73 0.25 118.83 ;
			LAYER	M3 ;
			RECT	0 118.73 0.25 118.83 ;
		END

		ANTENNADIFFAREA 0.018 ;
		ANTENNAPARTIALMETALAREA 0.025 ;
	END q[67]

	PIN q[68]
		USE SIGNAL ;
		DIRECTION OUTPUT ;
		SHAPE ABUTMENT ;
		PORT
			LAYER	M1 ;
			RECT	0 121.04 0.25 121.14 ;
			LAYER	M2 ;
			RECT	0 121.04 0.25 121.14 ;
			LAYER	M3 ;
			RECT	0 121.04 0.25 121.14 ;
		END

		ANTENNADIFFAREA 0.018 ;
		ANTENNAPARTIALMETALAREA 0.025 ;
	END q[68]

	PIN q[69]
		USE SIGNAL ;
		DIRECTION OUTPUT ;
		SHAPE ABUTMENT ;
		PORT
			LAYER	M1 ;
			RECT	0 121.57 0.25 121.67 ;
			LAYER	M2 ;
			RECT	0 121.57 0.25 121.67 ;
			LAYER	M3 ;
			RECT	0 121.57 0.25 121.67 ;
		END

		ANTENNADIFFAREA 0.018 ;
		ANTENNAPARTIALMETALAREA 0.025 ;
	END q[69]

	PIN q[6]
		USE SIGNAL ;
		DIRECTION OUTPUT ;
		SHAPE ABUTMENT ;
		PORT
			LAYER	M1 ;
			RECT	0 10.515 0.25 10.615 ;
			LAYER	M2 ;
			RECT	0 10.515 0.25 10.615 ;
			LAYER	M3 ;
			RECT	0 10.515 0.25 10.615 ;
		END

		ANTENNADIFFAREA 0.018 ;
		ANTENNAPARTIALMETALAREA 0.025 ;
	END q[6]

	PIN q[70]
		USE SIGNAL ;
		DIRECTION OUTPUT ;
		SHAPE ABUTMENT ;
		PORT
			LAYER	M1 ;
			RECT	0 123.88 0.25 123.98 ;
			LAYER	M2 ;
			RECT	0 123.88 0.25 123.98 ;
			LAYER	M3 ;
			RECT	0 123.88 0.25 123.98 ;
		END

		ANTENNADIFFAREA 0.018 ;
		ANTENNAPARTIALMETALAREA 0.025 ;
	END q[70]

	PIN q[71]
		USE SIGNAL ;
		DIRECTION OUTPUT ;
		SHAPE ABUTMENT ;
		PORT
			LAYER	M1 ;
			RECT	0 124.41 0.25 124.51 ;
			LAYER	M2 ;
			RECT	0 124.41 0.25 124.51 ;
			LAYER	M3 ;
			RECT	0 124.41 0.25 124.51 ;
		END

		ANTENNADIFFAREA 0.018 ;
		ANTENNAPARTIALMETALAREA 0.025 ;
	END q[71]

	PIN q[72]
		USE SIGNAL ;
		DIRECTION OUTPUT ;
		SHAPE ABUTMENT ;
		PORT
			LAYER	M1 ;
			RECT	0 126.72 0.25 126.82 ;
			LAYER	M2 ;
			RECT	0 126.72 0.25 126.82 ;
			LAYER	M3 ;
			RECT	0 126.72 0.25 126.82 ;
		END

		ANTENNADIFFAREA 0.018 ;
		ANTENNAPARTIALMETALAREA 0.025 ;
	END q[72]

	PIN q[73]
		USE SIGNAL ;
		DIRECTION OUTPUT ;
		SHAPE ABUTMENT ;
		PORT
			LAYER	M1 ;
			RECT	0 127.25 0.25 127.35 ;
			LAYER	M2 ;
			RECT	0 127.25 0.25 127.35 ;
			LAYER	M3 ;
			RECT	0 127.25 0.25 127.35 ;
		END

		ANTENNADIFFAREA 0.018 ;
		ANTENNAPARTIALMETALAREA 0.025 ;
	END q[73]

	PIN q[74]
		USE SIGNAL ;
		DIRECTION OUTPUT ;
		SHAPE ABUTMENT ;
		PORT
			LAYER	M1 ;
			RECT	0 129.56 0.25 129.66 ;
			LAYER	M2 ;
			RECT	0 129.56 0.25 129.66 ;
			LAYER	M3 ;
			RECT	0 129.56 0.25 129.66 ;
		END

		ANTENNADIFFAREA 0.018 ;
		ANTENNAPARTIALMETALAREA 0.025 ;
	END q[74]

	PIN q[75]
		USE SIGNAL ;
		DIRECTION OUTPUT ;
		SHAPE ABUTMENT ;
		PORT
			LAYER	M1 ;
			RECT	0 130.09 0.25 130.19 ;
			LAYER	M2 ;
			RECT	0 130.09 0.25 130.19 ;
			LAYER	M3 ;
			RECT	0 130.09 0.25 130.19 ;
		END

		ANTENNADIFFAREA 0.018 ;
		ANTENNAPARTIALMETALAREA 0.025 ;
	END q[75]

	PIN q[76]
		USE SIGNAL ;
		DIRECTION OUTPUT ;
		SHAPE ABUTMENT ;
		PORT
			LAYER	M1 ;
			RECT	0 132.4 0.25 132.5 ;
			LAYER	M2 ;
			RECT	0 132.4 0.25 132.5 ;
			LAYER	M3 ;
			RECT	0 132.4 0.25 132.5 ;
		END

		ANTENNADIFFAREA 0.018 ;
		ANTENNAPARTIALMETALAREA 0.025 ;
	END q[76]

	PIN q[77]
		USE SIGNAL ;
		DIRECTION OUTPUT ;
		SHAPE ABUTMENT ;
		PORT
			LAYER	M1 ;
			RECT	0 132.93 0.25 133.03 ;
			LAYER	M2 ;
			RECT	0 132.93 0.25 133.03 ;
			LAYER	M3 ;
			RECT	0 132.93 0.25 133.03 ;
		END

		ANTENNADIFFAREA 0.018 ;
		ANTENNAPARTIALMETALAREA 0.025 ;
	END q[77]

	PIN q[78]
		USE SIGNAL ;
		DIRECTION OUTPUT ;
		SHAPE ABUTMENT ;
		PORT
			LAYER	M1 ;
			RECT	0 135.24 0.25 135.34 ;
			LAYER	M2 ;
			RECT	0 135.24 0.25 135.34 ;
			LAYER	M3 ;
			RECT	0 135.24 0.25 135.34 ;
		END

		ANTENNADIFFAREA 0.018 ;
		ANTENNAPARTIALMETALAREA 0.025 ;
	END q[78]

	PIN q[79]
		USE SIGNAL ;
		DIRECTION OUTPUT ;
		SHAPE ABUTMENT ;
		PORT
			LAYER	M1 ;
			RECT	0 135.77 0.25 135.87 ;
			LAYER	M2 ;
			RECT	0 135.77 0.25 135.87 ;
			LAYER	M3 ;
			RECT	0 135.77 0.25 135.87 ;
		END

		ANTENNADIFFAREA 0.018 ;
		ANTENNAPARTIALMETALAREA 0.025 ;
	END q[79]

	PIN q[7]
		USE SIGNAL ;
		DIRECTION OUTPUT ;
		SHAPE ABUTMENT ;
		PORT
			LAYER	M1 ;
			RECT	0 11.045 0.25 11.145 ;
			LAYER	M2 ;
			RECT	0 11.045 0.25 11.145 ;
			LAYER	M3 ;
			RECT	0 11.045 0.25 11.145 ;
		END

		ANTENNADIFFAREA 0.018 ;
		ANTENNAPARTIALMETALAREA 0.025 ;
	END q[7]

	PIN q[80]
		USE SIGNAL ;
		DIRECTION OUTPUT ;
		SHAPE ABUTMENT ;
		PORT
			LAYER	M1 ;
			RECT	0 138.08 0.25 138.18 ;
			LAYER	M2 ;
			RECT	0 138.08 0.25 138.18 ;
			LAYER	M3 ;
			RECT	0 138.08 0.25 138.18 ;
		END

		ANTENNADIFFAREA 0.018 ;
		ANTENNAPARTIALMETALAREA 0.025 ;
	END q[80]

	PIN q[81]
		USE SIGNAL ;
		DIRECTION OUTPUT ;
		SHAPE ABUTMENT ;
		PORT
			LAYER	M1 ;
			RECT	0 138.61 0.25 138.71 ;
			LAYER	M2 ;
			RECT	0 138.61 0.25 138.71 ;
			LAYER	M3 ;
			RECT	0 138.61 0.25 138.71 ;
		END

		ANTENNADIFFAREA 0.018 ;
		ANTENNAPARTIALMETALAREA 0.025 ;
	END q[81]

	PIN q[82]
		USE SIGNAL ;
		DIRECTION OUTPUT ;
		SHAPE ABUTMENT ;
		PORT
			LAYER	M1 ;
			RECT	0 140.92 0.25 141.02 ;
			LAYER	M2 ;
			RECT	0 140.92 0.25 141.02 ;
			LAYER	M3 ;
			RECT	0 140.92 0.25 141.02 ;
		END

		ANTENNADIFFAREA 0.018 ;
		ANTENNAPARTIALMETALAREA 0.025 ;
	END q[82]

	PIN q[83]
		USE SIGNAL ;
		DIRECTION OUTPUT ;
		SHAPE ABUTMENT ;
		PORT
			LAYER	M1 ;
			RECT	0 141.45 0.25 141.55 ;
			LAYER	M2 ;
			RECT	0 141.45 0.25 141.55 ;
			LAYER	M3 ;
			RECT	0 141.45 0.25 141.55 ;
		END

		ANTENNADIFFAREA 0.018 ;
		ANTENNAPARTIALMETALAREA 0.025 ;
	END q[83]

	PIN q[84]
		USE SIGNAL ;
		DIRECTION OUTPUT ;
		SHAPE ABUTMENT ;
		PORT
			LAYER	M1 ;
			RECT	0 143.76 0.25 143.86 ;
			LAYER	M2 ;
			RECT	0 143.76 0.25 143.86 ;
			LAYER	M3 ;
			RECT	0 143.76 0.25 143.86 ;
		END

		ANTENNADIFFAREA 0.018 ;
		ANTENNAPARTIALMETALAREA 0.025 ;
	END q[84]

	PIN q[85]
		USE SIGNAL ;
		DIRECTION OUTPUT ;
		SHAPE ABUTMENT ;
		PORT
			LAYER	M1 ;
			RECT	0 144.29 0.25 144.39 ;
			LAYER	M2 ;
			RECT	0 144.29 0.25 144.39 ;
			LAYER	M3 ;
			RECT	0 144.29 0.25 144.39 ;
		END

		ANTENNADIFFAREA 0.018 ;
		ANTENNAPARTIALMETALAREA 0.025 ;
	END q[85]

	PIN q[86]
		USE SIGNAL ;
		DIRECTION OUTPUT ;
		SHAPE ABUTMENT ;
		PORT
			LAYER	M1 ;
			RECT	0 146.6 0.25 146.7 ;
			LAYER	M2 ;
			RECT	0 146.6 0.25 146.7 ;
			LAYER	M3 ;
			RECT	0 146.6 0.25 146.7 ;
		END

		ANTENNADIFFAREA 0.018 ;
		ANTENNAPARTIALMETALAREA 0.025 ;
	END q[86]

	PIN q[87]
		USE SIGNAL ;
		DIRECTION OUTPUT ;
		SHAPE ABUTMENT ;
		PORT
			LAYER	M1 ;
			RECT	0 147.13 0.25 147.23 ;
			LAYER	M2 ;
			RECT	0 147.13 0.25 147.23 ;
			LAYER	M3 ;
			RECT	0 147.13 0.25 147.23 ;
		END

		ANTENNADIFFAREA 0.018 ;
		ANTENNAPARTIALMETALAREA 0.025 ;
	END q[87]

	PIN q[88]
		USE SIGNAL ;
		DIRECTION OUTPUT ;
		SHAPE ABUTMENT ;
		PORT
			LAYER	M1 ;
			RECT	0 149.44 0.25 149.54 ;
			LAYER	M2 ;
			RECT	0 149.44 0.25 149.54 ;
			LAYER	M3 ;
			RECT	0 149.44 0.25 149.54 ;
		END

		ANTENNADIFFAREA 0.018 ;
		ANTENNAPARTIALMETALAREA 0.025 ;
	END q[88]

	PIN q[89]
		USE SIGNAL ;
		DIRECTION OUTPUT ;
		SHAPE ABUTMENT ;
		PORT
			LAYER	M1 ;
			RECT	0 149.97 0.25 150.07 ;
			LAYER	M2 ;
			RECT	0 149.97 0.25 150.07 ;
			LAYER	M3 ;
			RECT	0 149.97 0.25 150.07 ;
		END

		ANTENNADIFFAREA 0.018 ;
		ANTENNAPARTIALMETALAREA 0.025 ;
	END q[89]

	PIN q[8]
		USE SIGNAL ;
		DIRECTION OUTPUT ;
		SHAPE ABUTMENT ;
		PORT
			LAYER	M1 ;
			RECT	0 13.355 0.25 13.455 ;
			LAYER	M2 ;
			RECT	0 13.355 0.25 13.455 ;
			LAYER	M3 ;
			RECT	0 13.355 0.25 13.455 ;
		END

		ANTENNADIFFAREA 0.018 ;
		ANTENNAPARTIALMETALAREA 0.025 ;
	END q[8]

	PIN q[90]
		USE SIGNAL ;
		DIRECTION OUTPUT ;
		SHAPE ABUTMENT ;
		PORT
			LAYER	M1 ;
			RECT	0 152.28 0.25 152.38 ;
			LAYER	M2 ;
			RECT	0 152.28 0.25 152.38 ;
			LAYER	M3 ;
			RECT	0 152.28 0.25 152.38 ;
		END

		ANTENNADIFFAREA 0.018 ;
		ANTENNAPARTIALMETALAREA 0.025 ;
	END q[90]

	PIN q[91]
		USE SIGNAL ;
		DIRECTION OUTPUT ;
		SHAPE ABUTMENT ;
		PORT
			LAYER	M1 ;
			RECT	0 152.81 0.25 152.91 ;
			LAYER	M2 ;
			RECT	0 152.81 0.25 152.91 ;
			LAYER	M3 ;
			RECT	0 152.81 0.25 152.91 ;
		END

		ANTENNADIFFAREA 0.018 ;
		ANTENNAPARTIALMETALAREA 0.025 ;
	END q[91]

	PIN q[92]
		USE SIGNAL ;
		DIRECTION OUTPUT ;
		SHAPE ABUTMENT ;
		PORT
			LAYER	M1 ;
			RECT	0 155.12 0.25 155.22 ;
			LAYER	M2 ;
			RECT	0 155.12 0.25 155.22 ;
			LAYER	M3 ;
			RECT	0 155.12 0.25 155.22 ;
		END

		ANTENNADIFFAREA 0.018 ;
		ANTENNAPARTIALMETALAREA 0.025 ;
	END q[92]

	PIN q[93]
		USE SIGNAL ;
		DIRECTION OUTPUT ;
		SHAPE ABUTMENT ;
		PORT
			LAYER	M1 ;
			RECT	0 155.65 0.25 155.75 ;
			LAYER	M2 ;
			RECT	0 155.65 0.25 155.75 ;
			LAYER	M3 ;
			RECT	0 155.65 0.25 155.75 ;
		END

		ANTENNADIFFAREA 0.018 ;
		ANTENNAPARTIALMETALAREA 0.025 ;
	END q[93]

	PIN q[94]
		USE SIGNAL ;
		DIRECTION OUTPUT ;
		SHAPE ABUTMENT ;
		PORT
			LAYER	M1 ;
			RECT	0 157.96 0.25 158.06 ;
			LAYER	M2 ;
			RECT	0 157.96 0.25 158.06 ;
			LAYER	M3 ;
			RECT	0 157.96 0.25 158.06 ;
		END

		ANTENNADIFFAREA 0.018 ;
		ANTENNAPARTIALMETALAREA 0.025 ;
	END q[94]

	PIN q[95]
		USE SIGNAL ;
		DIRECTION OUTPUT ;
		SHAPE ABUTMENT ;
		PORT
			LAYER	M1 ;
			RECT	0 158.49 0.25 158.59 ;
			LAYER	M2 ;
			RECT	0 158.49 0.25 158.59 ;
			LAYER	M3 ;
			RECT	0 158.49 0.25 158.59 ;
		END

		ANTENNADIFFAREA 0.018 ;
		ANTENNAPARTIALMETALAREA 0.025 ;
	END q[95]

	PIN q[96]
		USE SIGNAL ;
		DIRECTION OUTPUT ;
		SHAPE ABUTMENT ;
		PORT
			LAYER	M1 ;
			RECT	0 160.8 0.25 160.9 ;
			LAYER	M2 ;
			RECT	0 160.8 0.25 160.9 ;
			LAYER	M3 ;
			RECT	0 160.8 0.25 160.9 ;
		END

		ANTENNADIFFAREA 0.018 ;
		ANTENNAPARTIALMETALAREA 0.025 ;
	END q[96]

	PIN q[97]
		USE SIGNAL ;
		DIRECTION OUTPUT ;
		SHAPE ABUTMENT ;
		PORT
			LAYER	M1 ;
			RECT	0 161.33 0.25 161.43 ;
			LAYER	M2 ;
			RECT	0 161.33 0.25 161.43 ;
			LAYER	M3 ;
			RECT	0 161.33 0.25 161.43 ;
		END

		ANTENNADIFFAREA 0.018 ;
		ANTENNAPARTIALMETALAREA 0.025 ;
	END q[97]

	PIN q[98]
		USE SIGNAL ;
		DIRECTION OUTPUT ;
		SHAPE ABUTMENT ;
		PORT
			LAYER	M1 ;
			RECT	0 163.64 0.25 163.74 ;
			LAYER	M2 ;
			RECT	0 163.64 0.25 163.74 ;
			LAYER	M3 ;
			RECT	0 163.64 0.25 163.74 ;
		END

		ANTENNADIFFAREA 0.018 ;
		ANTENNAPARTIALMETALAREA 0.025 ;
	END q[98]

	PIN q[99]
		USE SIGNAL ;
		DIRECTION OUTPUT ;
		SHAPE ABUTMENT ;
		PORT
			LAYER	M1 ;
			RECT	0 164.17 0.25 164.27 ;
			LAYER	M2 ;
			RECT	0 164.17 0.25 164.27 ;
			LAYER	M3 ;
			RECT	0 164.17 0.25 164.27 ;
		END

		ANTENNADIFFAREA 0.018 ;
		ANTENNAPARTIALMETALAREA 0.025 ;
	END q[99]

	PIN q[9]
		USE SIGNAL ;
		DIRECTION OUTPUT ;
		SHAPE ABUTMENT ;
		PORT
			LAYER	M1 ;
			RECT	0 13.885 0.25 13.985 ;
			LAYER	M2 ;
			RECT	0 13.885 0.25 13.985 ;
			LAYER	M3 ;
			RECT	0 13.885 0.25 13.985 ;
		END

		ANTENNADIFFAREA 0.018 ;
		ANTENNAPARTIALMETALAREA 0.025 ;
	END q[9]

	PIN ret1n
		USE SIGNAL ;
		DIRECTION INPUT ;
		SHAPE ABUTMENT ;
		PORT
			LAYER	M1 ;
			RECT	0 94.065 0.25 94.165 ;
			LAYER	M2 ;
			RECT	0 94.065 0.25 94.165 ;
			LAYER	M3 ;
			RECT	0 94.065 0.25 94.165 ;
		END

		ANTENNAGATEAREA 0.014 ;
		ANTENNADIFFAREA 0.018 ;
		ANTENNAPARTIALMETALAREA 0.025 ;
	END ret1n

	PIN wen[0]
		USE SIGNAL ;
		DIRECTION INPUT ;
		SHAPE ABUTMENT ;
		PORT
			LAYER	M1 ;
			RECT	0 1.165 0.25 1.265 ;
			LAYER	M2 ;
			RECT	0 1.165 0.25 1.265 ;
			LAYER	M3 ;
			RECT	0 1.165 0.25 1.265 ;
		END

		ANTENNAGATEAREA 0.014 ;
		ANTENNADIFFAREA 0.018 ;
		ANTENNAPARTIALMETALAREA 0.025 ;
	END wen[0]

	PIN wen[100]
		USE SIGNAL ;
		DIRECTION INPUT ;
		SHAPE ABUTMENT ;
		PORT
			LAYER	M1 ;
			RECT	0 165.65 0.25 165.75 ;
			LAYER	M2 ;
			RECT	0 165.65 0.25 165.75 ;
			LAYER	M3 ;
			RECT	0 165.65 0.25 165.75 ;
		END

		ANTENNAGATEAREA 0.014 ;
		ANTENNADIFFAREA 0.018 ;
		ANTENNAPARTIALMETALAREA 0.025 ;
	END wen[100]

	PIN wen[101]
		USE SIGNAL ;
		DIRECTION INPUT ;
		SHAPE ABUTMENT ;
		PORT
			LAYER	M1 ;
			RECT	0 167.84 0.25 167.94 ;
			LAYER	M2 ;
			RECT	0 167.84 0.25 167.94 ;
			LAYER	M3 ;
			RECT	0 167.84 0.25 167.94 ;
		END

		ANTENNAGATEAREA 0.014 ;
		ANTENNADIFFAREA 0.018 ;
		ANTENNAPARTIALMETALAREA 0.025 ;
	END wen[101]

	PIN wen[102]
		USE SIGNAL ;
		DIRECTION INPUT ;
		SHAPE ABUTMENT ;
		PORT
			LAYER	M1 ;
			RECT	0 168.49 0.25 168.59 ;
			LAYER	M2 ;
			RECT	0 168.49 0.25 168.59 ;
			LAYER	M3 ;
			RECT	0 168.49 0.25 168.59 ;
		END

		ANTENNAGATEAREA 0.014 ;
		ANTENNADIFFAREA 0.018 ;
		ANTENNAPARTIALMETALAREA 0.025 ;
	END wen[102]

	PIN wen[103]
		USE SIGNAL ;
		DIRECTION INPUT ;
		SHAPE ABUTMENT ;
		PORT
			LAYER	M1 ;
			RECT	0 170.68 0.25 170.78 ;
			LAYER	M2 ;
			RECT	0 170.68 0.25 170.78 ;
			LAYER	M3 ;
			RECT	0 170.68 0.25 170.78 ;
		END

		ANTENNAGATEAREA 0.014 ;
		ANTENNADIFFAREA 0.018 ;
		ANTENNAPARTIALMETALAREA 0.025 ;
	END wen[103]

	PIN wen[104]
		USE SIGNAL ;
		DIRECTION INPUT ;
		SHAPE ABUTMENT ;
		PORT
			LAYER	M1 ;
			RECT	0 171.33 0.25 171.43 ;
			LAYER	M2 ;
			RECT	0 171.33 0.25 171.43 ;
			LAYER	M3 ;
			RECT	0 171.33 0.25 171.43 ;
		END

		ANTENNAGATEAREA 0.014 ;
		ANTENNADIFFAREA 0.018 ;
		ANTENNAPARTIALMETALAREA 0.025 ;
	END wen[104]

	PIN wen[105]
		USE SIGNAL ;
		DIRECTION INPUT ;
		SHAPE ABUTMENT ;
		PORT
			LAYER	M1 ;
			RECT	0 173.52 0.25 173.62 ;
			LAYER	M2 ;
			RECT	0 173.52 0.25 173.62 ;
			LAYER	M3 ;
			RECT	0 173.52 0.25 173.62 ;
		END

		ANTENNAGATEAREA 0.014 ;
		ANTENNADIFFAREA 0.018 ;
		ANTENNAPARTIALMETALAREA 0.025 ;
	END wen[105]

	PIN wen[106]
		USE SIGNAL ;
		DIRECTION INPUT ;
		SHAPE ABUTMENT ;
		PORT
			LAYER	M1 ;
			RECT	0 174.17 0.25 174.27 ;
			LAYER	M2 ;
			RECT	0 174.17 0.25 174.27 ;
			LAYER	M3 ;
			RECT	0 174.17 0.25 174.27 ;
		END

		ANTENNAGATEAREA 0.014 ;
		ANTENNADIFFAREA 0.018 ;
		ANTENNAPARTIALMETALAREA 0.025 ;
	END wen[106]

	PIN wen[107]
		USE SIGNAL ;
		DIRECTION INPUT ;
		SHAPE ABUTMENT ;
		PORT
			LAYER	M1 ;
			RECT	0 176.36 0.25 176.46 ;
			LAYER	M2 ;
			RECT	0 176.36 0.25 176.46 ;
			LAYER	M3 ;
			RECT	0 176.36 0.25 176.46 ;
		END

		ANTENNAGATEAREA 0.014 ;
		ANTENNADIFFAREA 0.018 ;
		ANTENNAPARTIALMETALAREA 0.025 ;
	END wen[107]

	PIN wen[108]
		USE SIGNAL ;
		DIRECTION INPUT ;
		SHAPE ABUTMENT ;
		PORT
			LAYER	M1 ;
			RECT	0 177.01 0.25 177.11 ;
			LAYER	M2 ;
			RECT	0 177.01 0.25 177.11 ;
			LAYER	M3 ;
			RECT	0 177.01 0.25 177.11 ;
		END

		ANTENNAGATEAREA 0.014 ;
		ANTENNADIFFAREA 0.018 ;
		ANTENNAPARTIALMETALAREA 0.025 ;
	END wen[108]

	PIN wen[109]
		USE SIGNAL ;
		DIRECTION INPUT ;
		SHAPE ABUTMENT ;
		PORT
			LAYER	M1 ;
			RECT	0 179.2 0.25 179.3 ;
			LAYER	M2 ;
			RECT	0 179.2 0.25 179.3 ;
			LAYER	M3 ;
			RECT	0 179.2 0.25 179.3 ;
		END

		ANTENNAGATEAREA 0.014 ;
		ANTENNADIFFAREA 0.018 ;
		ANTENNAPARTIALMETALAREA 0.025 ;
	END wen[109]

	PIN wen[10]
		USE SIGNAL ;
		DIRECTION INPUT ;
		SHAPE ABUTMENT ;
		PORT
			LAYER	M1 ;
			RECT	0 15.365 0.25 15.465 ;
			LAYER	M2 ;
			RECT	0 15.365 0.25 15.465 ;
			LAYER	M3 ;
			RECT	0 15.365 0.25 15.465 ;
		END

		ANTENNAGATEAREA 0.014 ;
		ANTENNADIFFAREA 0.018 ;
		ANTENNAPARTIALMETALAREA 0.025 ;
	END wen[10]

	PIN wen[110]
		USE SIGNAL ;
		DIRECTION INPUT ;
		SHAPE ABUTMENT ;
		PORT
			LAYER	M1 ;
			RECT	0 179.85 0.25 179.95 ;
			LAYER	M2 ;
			RECT	0 179.85 0.25 179.95 ;
			LAYER	M3 ;
			RECT	0 179.85 0.25 179.95 ;
		END

		ANTENNAGATEAREA 0.014 ;
		ANTENNADIFFAREA 0.018 ;
		ANTENNAPARTIALMETALAREA 0.025 ;
	END wen[110]

	PIN wen[111]
		USE SIGNAL ;
		DIRECTION INPUT ;
		SHAPE ABUTMENT ;
		PORT
			LAYER	M1 ;
			RECT	0 182.04 0.25 182.14 ;
			LAYER	M2 ;
			RECT	0 182.04 0.25 182.14 ;
			LAYER	M3 ;
			RECT	0 182.04 0.25 182.14 ;
		END

		ANTENNAGATEAREA 0.014 ;
		ANTENNADIFFAREA 0.018 ;
		ANTENNAPARTIALMETALAREA 0.025 ;
	END wen[111]

	PIN wen[112]
		USE SIGNAL ;
		DIRECTION INPUT ;
		SHAPE ABUTMENT ;
		PORT
			LAYER	M1 ;
			RECT	0 182.69 0.25 182.79 ;
			LAYER	M2 ;
			RECT	0 182.69 0.25 182.79 ;
			LAYER	M3 ;
			RECT	0 182.69 0.25 182.79 ;
		END

		ANTENNAGATEAREA 0.014 ;
		ANTENNADIFFAREA 0.018 ;
		ANTENNAPARTIALMETALAREA 0.025 ;
	END wen[112]

	PIN wen[113]
		USE SIGNAL ;
		DIRECTION INPUT ;
		SHAPE ABUTMENT ;
		PORT
			LAYER	M1 ;
			RECT	0 184.88 0.25 184.98 ;
			LAYER	M2 ;
			RECT	0 184.88 0.25 184.98 ;
			LAYER	M3 ;
			RECT	0 184.88 0.25 184.98 ;
		END

		ANTENNAGATEAREA 0.014 ;
		ANTENNADIFFAREA 0.018 ;
		ANTENNAPARTIALMETALAREA 0.025 ;
	END wen[113]

	PIN wen[114]
		USE SIGNAL ;
		DIRECTION INPUT ;
		SHAPE ABUTMENT ;
		PORT
			LAYER	M1 ;
			RECT	0 185.53 0.25 185.63 ;
			LAYER	M2 ;
			RECT	0 185.53 0.25 185.63 ;
			LAYER	M3 ;
			RECT	0 185.53 0.25 185.63 ;
		END

		ANTENNAGATEAREA 0.014 ;
		ANTENNADIFFAREA 0.018 ;
		ANTENNAPARTIALMETALAREA 0.025 ;
	END wen[114]

	PIN wen[115]
		USE SIGNAL ;
		DIRECTION INPUT ;
		SHAPE ABUTMENT ;
		PORT
			LAYER	M1 ;
			RECT	0 187.72 0.25 187.82 ;
			LAYER	M2 ;
			RECT	0 187.72 0.25 187.82 ;
			LAYER	M3 ;
			RECT	0 187.72 0.25 187.82 ;
		END

		ANTENNAGATEAREA 0.014 ;
		ANTENNADIFFAREA 0.018 ;
		ANTENNAPARTIALMETALAREA 0.025 ;
	END wen[115]

	PIN wen[116]
		USE SIGNAL ;
		DIRECTION INPUT ;
		SHAPE ABUTMENT ;
		PORT
			LAYER	M1 ;
			RECT	0 188.37 0.25 188.47 ;
			LAYER	M2 ;
			RECT	0 188.37 0.25 188.47 ;
			LAYER	M3 ;
			RECT	0 188.37 0.25 188.47 ;
		END

		ANTENNAGATEAREA 0.014 ;
		ANTENNADIFFAREA 0.018 ;
		ANTENNAPARTIALMETALAREA 0.025 ;
	END wen[116]

	PIN wen[117]
		USE SIGNAL ;
		DIRECTION INPUT ;
		SHAPE ABUTMENT ;
		PORT
			LAYER	M1 ;
			RECT	0 190.56 0.25 190.66 ;
			LAYER	M2 ;
			RECT	0 190.56 0.25 190.66 ;
			LAYER	M3 ;
			RECT	0 190.56 0.25 190.66 ;
		END

		ANTENNAGATEAREA 0.014 ;
		ANTENNADIFFAREA 0.018 ;
		ANTENNAPARTIALMETALAREA 0.025 ;
	END wen[117]

	PIN wen[118]
		USE SIGNAL ;
		DIRECTION INPUT ;
		SHAPE ABUTMENT ;
		PORT
			LAYER	M1 ;
			RECT	0 191.21 0.25 191.31 ;
			LAYER	M2 ;
			RECT	0 191.21 0.25 191.31 ;
			LAYER	M3 ;
			RECT	0 191.21 0.25 191.31 ;
		END

		ANTENNAGATEAREA 0.014 ;
		ANTENNADIFFAREA 0.018 ;
		ANTENNAPARTIALMETALAREA 0.025 ;
	END wen[118]

	PIN wen[119]
		USE SIGNAL ;
		DIRECTION INPUT ;
		SHAPE ABUTMENT ;
		PORT
			LAYER	M1 ;
			RECT	0 193.4 0.25 193.5 ;
			LAYER	M2 ;
			RECT	0 193.4 0.25 193.5 ;
			LAYER	M3 ;
			RECT	0 193.4 0.25 193.5 ;
		END

		ANTENNAGATEAREA 0.014 ;
		ANTENNADIFFAREA 0.018 ;
		ANTENNAPARTIALMETALAREA 0.025 ;
	END wen[119]

	PIN wen[11]
		USE SIGNAL ;
		DIRECTION INPUT ;
		SHAPE ABUTMENT ;
		PORT
			LAYER	M1 ;
			RECT	0 17.555 0.25 17.655 ;
			LAYER	M2 ;
			RECT	0 17.555 0.25 17.655 ;
			LAYER	M3 ;
			RECT	0 17.555 0.25 17.655 ;
		END

		ANTENNAGATEAREA 0.014 ;
		ANTENNADIFFAREA 0.018 ;
		ANTENNAPARTIALMETALAREA 0.025 ;
	END wen[11]

	PIN wen[120]
		USE SIGNAL ;
		DIRECTION INPUT ;
		SHAPE ABUTMENT ;
		PORT
			LAYER	M1 ;
			RECT	0 194.05 0.25 194.15 ;
			LAYER	M2 ;
			RECT	0 194.05 0.25 194.15 ;
			LAYER	M3 ;
			RECT	0 194.05 0.25 194.15 ;
		END

		ANTENNAGATEAREA 0.014 ;
		ANTENNADIFFAREA 0.018 ;
		ANTENNAPARTIALMETALAREA 0.025 ;
	END wen[120]

	PIN wen[121]
		USE SIGNAL ;
		DIRECTION INPUT ;
		SHAPE ABUTMENT ;
		PORT
			LAYER	M1 ;
			RECT	0 196.24 0.25 196.34 ;
			LAYER	M2 ;
			RECT	0 196.24 0.25 196.34 ;
			LAYER	M3 ;
			RECT	0 196.24 0.25 196.34 ;
		END

		ANTENNAGATEAREA 0.014 ;
		ANTENNADIFFAREA 0.018 ;
		ANTENNAPARTIALMETALAREA 0.025 ;
	END wen[121]

	PIN wen[122]
		USE SIGNAL ;
		DIRECTION INPUT ;
		SHAPE ABUTMENT ;
		PORT
			LAYER	M1 ;
			RECT	0 196.89 0.25 196.99 ;
			LAYER	M2 ;
			RECT	0 196.89 0.25 196.99 ;
			LAYER	M3 ;
			RECT	0 196.89 0.25 196.99 ;
		END

		ANTENNAGATEAREA 0.014 ;
		ANTENNADIFFAREA 0.018 ;
		ANTENNAPARTIALMETALAREA 0.025 ;
	END wen[122]

	PIN wen[123]
		USE SIGNAL ;
		DIRECTION INPUT ;
		SHAPE ABUTMENT ;
		PORT
			LAYER	M1 ;
			RECT	0 199.08 0.25 199.18 ;
			LAYER	M2 ;
			RECT	0 199.08 0.25 199.18 ;
			LAYER	M3 ;
			RECT	0 199.08 0.25 199.18 ;
		END

		ANTENNAGATEAREA 0.014 ;
		ANTENNADIFFAREA 0.018 ;
		ANTENNAPARTIALMETALAREA 0.025 ;
	END wen[123]

	PIN wen[124]
		USE SIGNAL ;
		DIRECTION INPUT ;
		SHAPE ABUTMENT ;
		PORT
			LAYER	M1 ;
			RECT	0 199.73 0.25 199.83 ;
			LAYER	M2 ;
			RECT	0 199.73 0.25 199.83 ;
			LAYER	M3 ;
			RECT	0 199.73 0.25 199.83 ;
		END

		ANTENNAGATEAREA 0.014 ;
		ANTENNADIFFAREA 0.018 ;
		ANTENNAPARTIALMETALAREA 0.025 ;
	END wen[124]

	PIN wen[125]
		USE SIGNAL ;
		DIRECTION INPUT ;
		SHAPE ABUTMENT ;
		PORT
			LAYER	M1 ;
			RECT	0 201.92 0.25 202.02 ;
			LAYER	M2 ;
			RECT	0 201.92 0.25 202.02 ;
			LAYER	M3 ;
			RECT	0 201.92 0.25 202.02 ;
		END

		ANTENNAGATEAREA 0.014 ;
		ANTENNADIFFAREA 0.018 ;
		ANTENNAPARTIALMETALAREA 0.025 ;
	END wen[125]

	PIN wen[126]
		USE SIGNAL ;
		DIRECTION INPUT ;
		SHAPE ABUTMENT ;
		PORT
			LAYER	M1 ;
			RECT	0 202.57 0.25 202.67 ;
			LAYER	M2 ;
			RECT	0 202.57 0.25 202.67 ;
			LAYER	M3 ;
			RECT	0 202.57 0.25 202.67 ;
		END

		ANTENNAGATEAREA 0.014 ;
		ANTENNADIFFAREA 0.018 ;
		ANTENNAPARTIALMETALAREA 0.025 ;
	END wen[126]

	PIN wen[127]
		USE SIGNAL ;
		DIRECTION INPUT ;
		SHAPE ABUTMENT ;
		PORT
			LAYER	M1 ;
			RECT	0 204.76 0.25 204.86 ;
			LAYER	M2 ;
			RECT	0 204.76 0.25 204.86 ;
			LAYER	M3 ;
			RECT	0 204.76 0.25 204.86 ;
		END

		ANTENNAGATEAREA 0.014 ;
		ANTENNADIFFAREA 0.018 ;
		ANTENNAPARTIALMETALAREA 0.025 ;
	END wen[127]

	PIN wen[12]
		USE SIGNAL ;
		DIRECTION INPUT ;
		SHAPE ABUTMENT ;
		PORT
			LAYER	M1 ;
			RECT	0 18.205 0.25 18.305 ;
			LAYER	M2 ;
			RECT	0 18.205 0.25 18.305 ;
			LAYER	M3 ;
			RECT	0 18.205 0.25 18.305 ;
		END

		ANTENNAGATEAREA 0.014 ;
		ANTENNADIFFAREA 0.018 ;
		ANTENNAPARTIALMETALAREA 0.025 ;
	END wen[12]

	PIN wen[13]
		USE SIGNAL ;
		DIRECTION INPUT ;
		SHAPE ABUTMENT ;
		PORT
			LAYER	M1 ;
			RECT	0 20.395 0.25 20.495 ;
			LAYER	M2 ;
			RECT	0 20.395 0.25 20.495 ;
			LAYER	M3 ;
			RECT	0 20.395 0.25 20.495 ;
		END

		ANTENNAGATEAREA 0.014 ;
		ANTENNADIFFAREA 0.018 ;
		ANTENNAPARTIALMETALAREA 0.025 ;
	END wen[13]

	PIN wen[14]
		USE SIGNAL ;
		DIRECTION INPUT ;
		SHAPE ABUTMENT ;
		PORT
			LAYER	M1 ;
			RECT	0 21.045 0.25 21.145 ;
			LAYER	M2 ;
			RECT	0 21.045 0.25 21.145 ;
			LAYER	M3 ;
			RECT	0 21.045 0.25 21.145 ;
		END

		ANTENNAGATEAREA 0.014 ;
		ANTENNADIFFAREA 0.018 ;
		ANTENNAPARTIALMETALAREA 0.025 ;
	END wen[14]

	PIN wen[15]
		USE SIGNAL ;
		DIRECTION INPUT ;
		SHAPE ABUTMENT ;
		PORT
			LAYER	M1 ;
			RECT	0 23.235 0.25 23.335 ;
			LAYER	M2 ;
			RECT	0 23.235 0.25 23.335 ;
			LAYER	M3 ;
			RECT	0 23.235 0.25 23.335 ;
		END

		ANTENNAGATEAREA 0.014 ;
		ANTENNADIFFAREA 0.018 ;
		ANTENNAPARTIALMETALAREA 0.025 ;
	END wen[15]

	PIN wen[16]
		USE SIGNAL ;
		DIRECTION INPUT ;
		SHAPE ABUTMENT ;
		PORT
			LAYER	M1 ;
			RECT	0 23.885 0.25 23.985 ;
			LAYER	M2 ;
			RECT	0 23.885 0.25 23.985 ;
			LAYER	M3 ;
			RECT	0 23.885 0.25 23.985 ;
		END

		ANTENNAGATEAREA 0.014 ;
		ANTENNADIFFAREA 0.018 ;
		ANTENNAPARTIALMETALAREA 0.025 ;
	END wen[16]

	PIN wen[17]
		USE SIGNAL ;
		DIRECTION INPUT ;
		SHAPE ABUTMENT ;
		PORT
			LAYER	M1 ;
			RECT	0 26.075 0.25 26.175 ;
			LAYER	M2 ;
			RECT	0 26.075 0.25 26.175 ;
			LAYER	M3 ;
			RECT	0 26.075 0.25 26.175 ;
		END

		ANTENNAGATEAREA 0.014 ;
		ANTENNADIFFAREA 0.018 ;
		ANTENNAPARTIALMETALAREA 0.025 ;
	END wen[17]

	PIN wen[18]
		USE SIGNAL ;
		DIRECTION INPUT ;
		SHAPE ABUTMENT ;
		PORT
			LAYER	M1 ;
			RECT	0 26.725 0.25 26.825 ;
			LAYER	M2 ;
			RECT	0 26.725 0.25 26.825 ;
			LAYER	M3 ;
			RECT	0 26.725 0.25 26.825 ;
		END

		ANTENNAGATEAREA 0.014 ;
		ANTENNADIFFAREA 0.018 ;
		ANTENNAPARTIALMETALAREA 0.025 ;
	END wen[18]

	PIN wen[19]
		USE SIGNAL ;
		DIRECTION INPUT ;
		SHAPE ABUTMENT ;
		PORT
			LAYER	M1 ;
			RECT	0 28.915 0.25 29.015 ;
			LAYER	M2 ;
			RECT	0 28.915 0.25 29.015 ;
			LAYER	M3 ;
			RECT	0 28.915 0.25 29.015 ;
		END

		ANTENNAGATEAREA 0.014 ;
		ANTENNADIFFAREA 0.018 ;
		ANTENNAPARTIALMETALAREA 0.025 ;
	END wen[19]

	PIN wen[1]
		USE SIGNAL ;
		DIRECTION INPUT ;
		SHAPE ABUTMENT ;
		PORT
			LAYER	M1 ;
			RECT	0 3.355 0.25 3.455 ;
			LAYER	M2 ;
			RECT	0 3.355 0.25 3.455 ;
			LAYER	M3 ;
			RECT	0 3.355 0.25 3.455 ;
		END

		ANTENNAGATEAREA 0.014 ;
		ANTENNADIFFAREA 0.018 ;
		ANTENNAPARTIALMETALAREA 0.025 ;
	END wen[1]

	PIN wen[20]
		USE SIGNAL ;
		DIRECTION INPUT ;
		SHAPE ABUTMENT ;
		PORT
			LAYER	M1 ;
			RECT	0 29.565 0.25 29.665 ;
			LAYER	M2 ;
			RECT	0 29.565 0.25 29.665 ;
			LAYER	M3 ;
			RECT	0 29.565 0.25 29.665 ;
		END

		ANTENNAGATEAREA 0.014 ;
		ANTENNADIFFAREA 0.018 ;
		ANTENNAPARTIALMETALAREA 0.025 ;
	END wen[20]

	PIN wen[21]
		USE SIGNAL ;
		DIRECTION INPUT ;
		SHAPE ABUTMENT ;
		PORT
			LAYER	M1 ;
			RECT	0 31.755 0.25 31.855 ;
			LAYER	M2 ;
			RECT	0 31.755 0.25 31.855 ;
			LAYER	M3 ;
			RECT	0 31.755 0.25 31.855 ;
		END

		ANTENNAGATEAREA 0.014 ;
		ANTENNADIFFAREA 0.018 ;
		ANTENNAPARTIALMETALAREA 0.025 ;
	END wen[21]

	PIN wen[22]
		USE SIGNAL ;
		DIRECTION INPUT ;
		SHAPE ABUTMENT ;
		PORT
			LAYER	M1 ;
			RECT	0 32.405 0.25 32.505 ;
			LAYER	M2 ;
			RECT	0 32.405 0.25 32.505 ;
			LAYER	M3 ;
			RECT	0 32.405 0.25 32.505 ;
		END

		ANTENNAGATEAREA 0.014 ;
		ANTENNADIFFAREA 0.018 ;
		ANTENNAPARTIALMETALAREA 0.025 ;
	END wen[22]

	PIN wen[23]
		USE SIGNAL ;
		DIRECTION INPUT ;
		SHAPE ABUTMENT ;
		PORT
			LAYER	M1 ;
			RECT	0 34.595 0.25 34.695 ;
			LAYER	M2 ;
			RECT	0 34.595 0.25 34.695 ;
			LAYER	M3 ;
			RECT	0 34.595 0.25 34.695 ;
		END

		ANTENNAGATEAREA 0.014 ;
		ANTENNADIFFAREA 0.018 ;
		ANTENNAPARTIALMETALAREA 0.025 ;
	END wen[23]

	PIN wen[24]
		USE SIGNAL ;
		DIRECTION INPUT ;
		SHAPE ABUTMENT ;
		PORT
			LAYER	M1 ;
			RECT	0 35.245 0.25 35.345 ;
			LAYER	M2 ;
			RECT	0 35.245 0.25 35.345 ;
			LAYER	M3 ;
			RECT	0 35.245 0.25 35.345 ;
		END

		ANTENNAGATEAREA 0.014 ;
		ANTENNADIFFAREA 0.018 ;
		ANTENNAPARTIALMETALAREA 0.025 ;
	END wen[24]

	PIN wen[25]
		USE SIGNAL ;
		DIRECTION INPUT ;
		SHAPE ABUTMENT ;
		PORT
			LAYER	M1 ;
			RECT	0 37.435 0.25 37.535 ;
			LAYER	M2 ;
			RECT	0 37.435 0.25 37.535 ;
			LAYER	M3 ;
			RECT	0 37.435 0.25 37.535 ;
		END

		ANTENNAGATEAREA 0.014 ;
		ANTENNADIFFAREA 0.018 ;
		ANTENNAPARTIALMETALAREA 0.025 ;
	END wen[25]

	PIN wen[26]
		USE SIGNAL ;
		DIRECTION INPUT ;
		SHAPE ABUTMENT ;
		PORT
			LAYER	M1 ;
			RECT	0 38.085 0.25 38.185 ;
			LAYER	M2 ;
			RECT	0 38.085 0.25 38.185 ;
			LAYER	M3 ;
			RECT	0 38.085 0.25 38.185 ;
		END

		ANTENNAGATEAREA 0.014 ;
		ANTENNADIFFAREA 0.018 ;
		ANTENNAPARTIALMETALAREA 0.025 ;
	END wen[26]

	PIN wen[27]
		USE SIGNAL ;
		DIRECTION INPUT ;
		SHAPE ABUTMENT ;
		PORT
			LAYER	M1 ;
			RECT	0 40.275 0.25 40.375 ;
			LAYER	M2 ;
			RECT	0 40.275 0.25 40.375 ;
			LAYER	M3 ;
			RECT	0 40.275 0.25 40.375 ;
		END

		ANTENNAGATEAREA 0.014 ;
		ANTENNADIFFAREA 0.018 ;
		ANTENNAPARTIALMETALAREA 0.025 ;
	END wen[27]

	PIN wen[28]
		USE SIGNAL ;
		DIRECTION INPUT ;
		SHAPE ABUTMENT ;
		PORT
			LAYER	M1 ;
			RECT	0 40.925 0.25 41.025 ;
			LAYER	M2 ;
			RECT	0 40.925 0.25 41.025 ;
			LAYER	M3 ;
			RECT	0 40.925 0.25 41.025 ;
		END

		ANTENNAGATEAREA 0.014 ;
		ANTENNADIFFAREA 0.018 ;
		ANTENNAPARTIALMETALAREA 0.025 ;
	END wen[28]

	PIN wen[29]
		USE SIGNAL ;
		DIRECTION INPUT ;
		SHAPE ABUTMENT ;
		PORT
			LAYER	M1 ;
			RECT	0 43.115 0.25 43.215 ;
			LAYER	M2 ;
			RECT	0 43.115 0.25 43.215 ;
			LAYER	M3 ;
			RECT	0 43.115 0.25 43.215 ;
		END

		ANTENNAGATEAREA 0.014 ;
		ANTENNADIFFAREA 0.018 ;
		ANTENNAPARTIALMETALAREA 0.025 ;
	END wen[29]

	PIN wen[2]
		USE SIGNAL ;
		DIRECTION INPUT ;
		SHAPE ABUTMENT ;
		PORT
			LAYER	M1 ;
			RECT	0 4.005 0.25 4.105 ;
			LAYER	M2 ;
			RECT	0 4.005 0.25 4.105 ;
			LAYER	M3 ;
			RECT	0 4.005 0.25 4.105 ;
		END

		ANTENNAGATEAREA 0.014 ;
		ANTENNADIFFAREA 0.018 ;
		ANTENNAPARTIALMETALAREA 0.025 ;
	END wen[2]

	PIN wen[30]
		USE SIGNAL ;
		DIRECTION INPUT ;
		SHAPE ABUTMENT ;
		PORT
			LAYER	M1 ;
			RECT	0 43.765 0.25 43.865 ;
			LAYER	M2 ;
			RECT	0 43.765 0.25 43.865 ;
			LAYER	M3 ;
			RECT	0 43.765 0.25 43.865 ;
		END

		ANTENNAGATEAREA 0.014 ;
		ANTENNADIFFAREA 0.018 ;
		ANTENNAPARTIALMETALAREA 0.025 ;
	END wen[30]

	PIN wen[31]
		USE SIGNAL ;
		DIRECTION INPUT ;
		SHAPE ABUTMENT ;
		PORT
			LAYER	M1 ;
			RECT	0 45.955 0.25 46.055 ;
			LAYER	M2 ;
			RECT	0 45.955 0.25 46.055 ;
			LAYER	M3 ;
			RECT	0 45.955 0.25 46.055 ;
		END

		ANTENNAGATEAREA 0.014 ;
		ANTENNADIFFAREA 0.018 ;
		ANTENNAPARTIALMETALAREA 0.025 ;
	END wen[31]

	PIN wen[32]
		USE SIGNAL ;
		DIRECTION INPUT ;
		SHAPE ABUTMENT ;
		PORT
			LAYER	M1 ;
			RECT	0 46.605 0.25 46.705 ;
			LAYER	M2 ;
			RECT	0 46.605 0.25 46.705 ;
			LAYER	M3 ;
			RECT	0 46.605 0.25 46.705 ;
		END

		ANTENNAGATEAREA 0.014 ;
		ANTENNADIFFAREA 0.018 ;
		ANTENNAPARTIALMETALAREA 0.025 ;
	END wen[32]

	PIN wen[33]
		USE SIGNAL ;
		DIRECTION INPUT ;
		SHAPE ABUTMENT ;
		PORT
			LAYER	M1 ;
			RECT	0 48.795 0.25 48.895 ;
			LAYER	M2 ;
			RECT	0 48.795 0.25 48.895 ;
			LAYER	M3 ;
			RECT	0 48.795 0.25 48.895 ;
		END

		ANTENNAGATEAREA 0.014 ;
		ANTENNADIFFAREA 0.018 ;
		ANTENNAPARTIALMETALAREA 0.025 ;
	END wen[33]

	PIN wen[34]
		USE SIGNAL ;
		DIRECTION INPUT ;
		SHAPE ABUTMENT ;
		PORT
			LAYER	M1 ;
			RECT	0 49.445 0.25 49.545 ;
			LAYER	M2 ;
			RECT	0 49.445 0.25 49.545 ;
			LAYER	M3 ;
			RECT	0 49.445 0.25 49.545 ;
		END

		ANTENNAGATEAREA 0.014 ;
		ANTENNADIFFAREA 0.018 ;
		ANTENNAPARTIALMETALAREA 0.025 ;
	END wen[34]

	PIN wen[35]
		USE SIGNAL ;
		DIRECTION INPUT ;
		SHAPE ABUTMENT ;
		PORT
			LAYER	M1 ;
			RECT	0 51.635 0.25 51.735 ;
			LAYER	M2 ;
			RECT	0 51.635 0.25 51.735 ;
			LAYER	M3 ;
			RECT	0 51.635 0.25 51.735 ;
		END

		ANTENNAGATEAREA 0.014 ;
		ANTENNADIFFAREA 0.018 ;
		ANTENNAPARTIALMETALAREA 0.025 ;
	END wen[35]

	PIN wen[36]
		USE SIGNAL ;
		DIRECTION INPUT ;
		SHAPE ABUTMENT ;
		PORT
			LAYER	M1 ;
			RECT	0 52.285 0.25 52.385 ;
			LAYER	M2 ;
			RECT	0 52.285 0.25 52.385 ;
			LAYER	M3 ;
			RECT	0 52.285 0.25 52.385 ;
		END

		ANTENNAGATEAREA 0.014 ;
		ANTENNADIFFAREA 0.018 ;
		ANTENNAPARTIALMETALAREA 0.025 ;
	END wen[36]

	PIN wen[37]
		USE SIGNAL ;
		DIRECTION INPUT ;
		SHAPE ABUTMENT ;
		PORT
			LAYER	M1 ;
			RECT	0 54.475 0.25 54.575 ;
			LAYER	M2 ;
			RECT	0 54.475 0.25 54.575 ;
			LAYER	M3 ;
			RECT	0 54.475 0.25 54.575 ;
		END

		ANTENNAGATEAREA 0.014 ;
		ANTENNADIFFAREA 0.018 ;
		ANTENNAPARTIALMETALAREA 0.025 ;
	END wen[37]

	PIN wen[38]
		USE SIGNAL ;
		DIRECTION INPUT ;
		SHAPE ABUTMENT ;
		PORT
			LAYER	M1 ;
			RECT	0 55.125 0.25 55.225 ;
			LAYER	M2 ;
			RECT	0 55.125 0.25 55.225 ;
			LAYER	M3 ;
			RECT	0 55.125 0.25 55.225 ;
		END

		ANTENNAGATEAREA 0.014 ;
		ANTENNADIFFAREA 0.018 ;
		ANTENNAPARTIALMETALAREA 0.025 ;
	END wen[38]

	PIN wen[39]
		USE SIGNAL ;
		DIRECTION INPUT ;
		SHAPE ABUTMENT ;
		PORT
			LAYER	M1 ;
			RECT	0 57.315 0.25 57.415 ;
			LAYER	M2 ;
			RECT	0 57.315 0.25 57.415 ;
			LAYER	M3 ;
			RECT	0 57.315 0.25 57.415 ;
		END

		ANTENNAGATEAREA 0.014 ;
		ANTENNADIFFAREA 0.018 ;
		ANTENNAPARTIALMETALAREA 0.025 ;
	END wen[39]

	PIN wen[3]
		USE SIGNAL ;
		DIRECTION INPUT ;
		SHAPE ABUTMENT ;
		PORT
			LAYER	M1 ;
			RECT	0 6.195 0.25 6.295 ;
			LAYER	M2 ;
			RECT	0 6.195 0.25 6.295 ;
			LAYER	M3 ;
			RECT	0 6.195 0.25 6.295 ;
		END

		ANTENNAGATEAREA 0.014 ;
		ANTENNADIFFAREA 0.018 ;
		ANTENNAPARTIALMETALAREA 0.025 ;
	END wen[3]

	PIN wen[40]
		USE SIGNAL ;
		DIRECTION INPUT ;
		SHAPE ABUTMENT ;
		PORT
			LAYER	M1 ;
			RECT	0 57.965 0.25 58.065 ;
			LAYER	M2 ;
			RECT	0 57.965 0.25 58.065 ;
			LAYER	M3 ;
			RECT	0 57.965 0.25 58.065 ;
		END

		ANTENNAGATEAREA 0.014 ;
		ANTENNADIFFAREA 0.018 ;
		ANTENNAPARTIALMETALAREA 0.025 ;
	END wen[40]

	PIN wen[41]
		USE SIGNAL ;
		DIRECTION INPUT ;
		SHAPE ABUTMENT ;
		PORT
			LAYER	M1 ;
			RECT	0 60.155 0.25 60.255 ;
			LAYER	M2 ;
			RECT	0 60.155 0.25 60.255 ;
			LAYER	M3 ;
			RECT	0 60.155 0.25 60.255 ;
		END

		ANTENNAGATEAREA 0.014 ;
		ANTENNADIFFAREA 0.018 ;
		ANTENNAPARTIALMETALAREA 0.025 ;
	END wen[41]

	PIN wen[42]
		USE SIGNAL ;
		DIRECTION INPUT ;
		SHAPE ABUTMENT ;
		PORT
			LAYER	M1 ;
			RECT	0 60.805 0.25 60.905 ;
			LAYER	M2 ;
			RECT	0 60.805 0.25 60.905 ;
			LAYER	M3 ;
			RECT	0 60.805 0.25 60.905 ;
		END

		ANTENNAGATEAREA 0.014 ;
		ANTENNADIFFAREA 0.018 ;
		ANTENNAPARTIALMETALAREA 0.025 ;
	END wen[42]

	PIN wen[43]
		USE SIGNAL ;
		DIRECTION INPUT ;
		SHAPE ABUTMENT ;
		PORT
			LAYER	M1 ;
			RECT	0 62.995 0.25 63.095 ;
			LAYER	M2 ;
			RECT	0 62.995 0.25 63.095 ;
			LAYER	M3 ;
			RECT	0 62.995 0.25 63.095 ;
		END

		ANTENNAGATEAREA 0.014 ;
		ANTENNADIFFAREA 0.018 ;
		ANTENNAPARTIALMETALAREA 0.025 ;
	END wen[43]

	PIN wen[44]
		USE SIGNAL ;
		DIRECTION INPUT ;
		SHAPE ABUTMENT ;
		PORT
			LAYER	M1 ;
			RECT	0 63.645 0.25 63.745 ;
			LAYER	M2 ;
			RECT	0 63.645 0.25 63.745 ;
			LAYER	M3 ;
			RECT	0 63.645 0.25 63.745 ;
		END

		ANTENNAGATEAREA 0.014 ;
		ANTENNADIFFAREA 0.018 ;
		ANTENNAPARTIALMETALAREA 0.025 ;
	END wen[44]

	PIN wen[45]
		USE SIGNAL ;
		DIRECTION INPUT ;
		SHAPE ABUTMENT ;
		PORT
			LAYER	M1 ;
			RECT	0 65.835 0.25 65.935 ;
			LAYER	M2 ;
			RECT	0 65.835 0.25 65.935 ;
			LAYER	M3 ;
			RECT	0 65.835 0.25 65.935 ;
		END

		ANTENNAGATEAREA 0.014 ;
		ANTENNADIFFAREA 0.018 ;
		ANTENNAPARTIALMETALAREA 0.025 ;
	END wen[45]

	PIN wen[46]
		USE SIGNAL ;
		DIRECTION INPUT ;
		SHAPE ABUTMENT ;
		PORT
			LAYER	M1 ;
			RECT	0 66.485 0.25 66.585 ;
			LAYER	M2 ;
			RECT	0 66.485 0.25 66.585 ;
			LAYER	M3 ;
			RECT	0 66.485 0.25 66.585 ;
		END

		ANTENNAGATEAREA 0.014 ;
		ANTENNADIFFAREA 0.018 ;
		ANTENNAPARTIALMETALAREA 0.025 ;
	END wen[46]

	PIN wen[47]
		USE SIGNAL ;
		DIRECTION INPUT ;
		SHAPE ABUTMENT ;
		PORT
			LAYER	M1 ;
			RECT	0 68.675 0.25 68.775 ;
			LAYER	M2 ;
			RECT	0 68.675 0.25 68.775 ;
			LAYER	M3 ;
			RECT	0 68.675 0.25 68.775 ;
		END

		ANTENNAGATEAREA 0.014 ;
		ANTENNADIFFAREA 0.018 ;
		ANTENNAPARTIALMETALAREA 0.025 ;
	END wen[47]

	PIN wen[48]
		USE SIGNAL ;
		DIRECTION INPUT ;
		SHAPE ABUTMENT ;
		PORT
			LAYER	M1 ;
			RECT	0 69.325 0.25 69.425 ;
			LAYER	M2 ;
			RECT	0 69.325 0.25 69.425 ;
			LAYER	M3 ;
			RECT	0 69.325 0.25 69.425 ;
		END

		ANTENNAGATEAREA 0.014 ;
		ANTENNADIFFAREA 0.018 ;
		ANTENNAPARTIALMETALAREA 0.025 ;
	END wen[48]

	PIN wen[49]
		USE SIGNAL ;
		DIRECTION INPUT ;
		SHAPE ABUTMENT ;
		PORT
			LAYER	M1 ;
			RECT	0 71.515 0.25 71.615 ;
			LAYER	M2 ;
			RECT	0 71.515 0.25 71.615 ;
			LAYER	M3 ;
			RECT	0 71.515 0.25 71.615 ;
		END

		ANTENNAGATEAREA 0.014 ;
		ANTENNADIFFAREA 0.018 ;
		ANTENNAPARTIALMETALAREA 0.025 ;
	END wen[49]

	PIN wen[4]
		USE SIGNAL ;
		DIRECTION INPUT ;
		SHAPE ABUTMENT ;
		PORT
			LAYER	M1 ;
			RECT	0 6.845 0.25 6.945 ;
			LAYER	M2 ;
			RECT	0 6.845 0.25 6.945 ;
			LAYER	M3 ;
			RECT	0 6.845 0.25 6.945 ;
		END

		ANTENNAGATEAREA 0.014 ;
		ANTENNADIFFAREA 0.018 ;
		ANTENNAPARTIALMETALAREA 0.025 ;
	END wen[4]

	PIN wen[50]
		USE SIGNAL ;
		DIRECTION INPUT ;
		SHAPE ABUTMENT ;
		PORT
			LAYER	M1 ;
			RECT	0 72.165 0.25 72.265 ;
			LAYER	M2 ;
			RECT	0 72.165 0.25 72.265 ;
			LAYER	M3 ;
			RECT	0 72.165 0.25 72.265 ;
		END

		ANTENNAGATEAREA 0.014 ;
		ANTENNADIFFAREA 0.018 ;
		ANTENNAPARTIALMETALAREA 0.025 ;
	END wen[50]

	PIN wen[51]
		USE SIGNAL ;
		DIRECTION INPUT ;
		SHAPE ABUTMENT ;
		PORT
			LAYER	M1 ;
			RECT	0 74.355 0.25 74.455 ;
			LAYER	M2 ;
			RECT	0 74.355 0.25 74.455 ;
			LAYER	M3 ;
			RECT	0 74.355 0.25 74.455 ;
		END

		ANTENNAGATEAREA 0.014 ;
		ANTENNADIFFAREA 0.018 ;
		ANTENNAPARTIALMETALAREA 0.025 ;
	END wen[51]

	PIN wen[52]
		USE SIGNAL ;
		DIRECTION INPUT ;
		SHAPE ABUTMENT ;
		PORT
			LAYER	M1 ;
			RECT	0 75.005 0.25 75.105 ;
			LAYER	M2 ;
			RECT	0 75.005 0.25 75.105 ;
			LAYER	M3 ;
			RECT	0 75.005 0.25 75.105 ;
		END

		ANTENNAGATEAREA 0.014 ;
		ANTENNADIFFAREA 0.018 ;
		ANTENNAPARTIALMETALAREA 0.025 ;
	END wen[52]

	PIN wen[53]
		USE SIGNAL ;
		DIRECTION INPUT ;
		SHAPE ABUTMENT ;
		PORT
			LAYER	M1 ;
			RECT	0 77.195 0.25 77.295 ;
			LAYER	M2 ;
			RECT	0 77.195 0.25 77.295 ;
			LAYER	M3 ;
			RECT	0 77.195 0.25 77.295 ;
		END

		ANTENNAGATEAREA 0.014 ;
		ANTENNADIFFAREA 0.018 ;
		ANTENNAPARTIALMETALAREA 0.025 ;
	END wen[53]

	PIN wen[54]
		USE SIGNAL ;
		DIRECTION INPUT ;
		SHAPE ABUTMENT ;
		PORT
			LAYER	M1 ;
			RECT	0 77.845 0.25 77.945 ;
			LAYER	M2 ;
			RECT	0 77.845 0.25 77.945 ;
			LAYER	M3 ;
			RECT	0 77.845 0.25 77.945 ;
		END

		ANTENNAGATEAREA 0.014 ;
		ANTENNADIFFAREA 0.018 ;
		ANTENNAPARTIALMETALAREA 0.025 ;
	END wen[54]

	PIN wen[55]
		USE SIGNAL ;
		DIRECTION INPUT ;
		SHAPE ABUTMENT ;
		PORT
			LAYER	M1 ;
			RECT	0 80.035 0.25 80.135 ;
			LAYER	M2 ;
			RECT	0 80.035 0.25 80.135 ;
			LAYER	M3 ;
			RECT	0 80.035 0.25 80.135 ;
		END

		ANTENNAGATEAREA 0.014 ;
		ANTENNADIFFAREA 0.018 ;
		ANTENNAPARTIALMETALAREA 0.025 ;
	END wen[55]

	PIN wen[56]
		USE SIGNAL ;
		DIRECTION INPUT ;
		SHAPE ABUTMENT ;
		PORT
			LAYER	M1 ;
			RECT	0 80.685 0.25 80.785 ;
			LAYER	M2 ;
			RECT	0 80.685 0.25 80.785 ;
			LAYER	M3 ;
			RECT	0 80.685 0.25 80.785 ;
		END

		ANTENNAGATEAREA 0.014 ;
		ANTENNADIFFAREA 0.018 ;
		ANTENNAPARTIALMETALAREA 0.025 ;
	END wen[56]

	PIN wen[57]
		USE SIGNAL ;
		DIRECTION INPUT ;
		SHAPE ABUTMENT ;
		PORT
			LAYER	M1 ;
			RECT	0 82.875 0.25 82.975 ;
			LAYER	M2 ;
			RECT	0 82.875 0.25 82.975 ;
			LAYER	M3 ;
			RECT	0 82.875 0.25 82.975 ;
		END

		ANTENNAGATEAREA 0.014 ;
		ANTENNADIFFAREA 0.018 ;
		ANTENNAPARTIALMETALAREA 0.025 ;
	END wen[57]

	PIN wen[58]
		USE SIGNAL ;
		DIRECTION INPUT ;
		SHAPE ABUTMENT ;
		PORT
			LAYER	M1 ;
			RECT	0 83.525 0.25 83.625 ;
			LAYER	M2 ;
			RECT	0 83.525 0.25 83.625 ;
			LAYER	M3 ;
			RECT	0 83.525 0.25 83.625 ;
		END

		ANTENNAGATEAREA 0.014 ;
		ANTENNADIFFAREA 0.018 ;
		ANTENNAPARTIALMETALAREA 0.025 ;
	END wen[58]

	PIN wen[59]
		USE SIGNAL ;
		DIRECTION INPUT ;
		SHAPE ABUTMENT ;
		PORT
			LAYER	M1 ;
			RECT	0 85.715 0.25 85.815 ;
			LAYER	M2 ;
			RECT	0 85.715 0.25 85.815 ;
			LAYER	M3 ;
			RECT	0 85.715 0.25 85.815 ;
		END

		ANTENNAGATEAREA 0.014 ;
		ANTENNADIFFAREA 0.018 ;
		ANTENNAPARTIALMETALAREA 0.025 ;
	END wen[59]

	PIN wen[5]
		USE SIGNAL ;
		DIRECTION INPUT ;
		SHAPE ABUTMENT ;
		PORT
			LAYER	M1 ;
			RECT	0 9.035 0.25 9.135 ;
			LAYER	M2 ;
			RECT	0 9.035 0.25 9.135 ;
			LAYER	M3 ;
			RECT	0 9.035 0.25 9.135 ;
		END

		ANTENNAGATEAREA 0.014 ;
		ANTENNADIFFAREA 0.018 ;
		ANTENNAPARTIALMETALAREA 0.025 ;
	END wen[5]

	PIN wen[60]
		USE SIGNAL ;
		DIRECTION INPUT ;
		SHAPE ABUTMENT ;
		PORT
			LAYER	M1 ;
			RECT	0 86.365 0.25 86.465 ;
			LAYER	M2 ;
			RECT	0 86.365 0.25 86.465 ;
			LAYER	M3 ;
			RECT	0 86.365 0.25 86.465 ;
		END

		ANTENNAGATEAREA 0.014 ;
		ANTENNADIFFAREA 0.018 ;
		ANTENNAPARTIALMETALAREA 0.025 ;
	END wen[60]

	PIN wen[61]
		USE SIGNAL ;
		DIRECTION INPUT ;
		SHAPE ABUTMENT ;
		PORT
			LAYER	M1 ;
			RECT	0 88.555 0.25 88.655 ;
			LAYER	M2 ;
			RECT	0 88.555 0.25 88.655 ;
			LAYER	M3 ;
			RECT	0 88.555 0.25 88.655 ;
		END

		ANTENNAGATEAREA 0.014 ;
		ANTENNADIFFAREA 0.018 ;
		ANTENNAPARTIALMETALAREA 0.025 ;
	END wen[61]

	PIN wen[62]
		USE SIGNAL ;
		DIRECTION INPUT ;
		SHAPE ABUTMENT ;
		PORT
			LAYER	M1 ;
			RECT	0 89.205 0.25 89.305 ;
			LAYER	M2 ;
			RECT	0 89.205 0.25 89.305 ;
			LAYER	M3 ;
			RECT	0 89.205 0.25 89.305 ;
		END

		ANTENNAGATEAREA 0.014 ;
		ANTENNADIFFAREA 0.018 ;
		ANTENNAPARTIALMETALAREA 0.025 ;
	END wen[62]

	PIN wen[63]
		USE SIGNAL ;
		DIRECTION INPUT ;
		SHAPE ABUTMENT ;
		PORT
			LAYER	M1 ;
			RECT	0 91.395 0.25 91.495 ;
			LAYER	M2 ;
			RECT	0 91.395 0.25 91.495 ;
			LAYER	M3 ;
			RECT	0 91.395 0.25 91.495 ;
		END

		ANTENNAGATEAREA 0.014 ;
		ANTENNADIFFAREA 0.018 ;
		ANTENNAPARTIALMETALAREA 0.025 ;
	END wen[63]

	PIN wen[64]
		USE SIGNAL ;
		DIRECTION INPUT ;
		SHAPE ABUTMENT ;
		PORT
			LAYER	M1 ;
			RECT	0 114.53 0.25 114.63 ;
			LAYER	M2 ;
			RECT	0 114.53 0.25 114.63 ;
			LAYER	M3 ;
			RECT	0 114.53 0.25 114.63 ;
		END

		ANTENNAGATEAREA 0.014 ;
		ANTENNADIFFAREA 0.018 ;
		ANTENNAPARTIALMETALAREA 0.025 ;
	END wen[64]

	PIN wen[65]
		USE SIGNAL ;
		DIRECTION INPUT ;
		SHAPE ABUTMENT ;
		PORT
			LAYER	M1 ;
			RECT	0 116.72 0.25 116.82 ;
			LAYER	M2 ;
			RECT	0 116.72 0.25 116.82 ;
			LAYER	M3 ;
			RECT	0 116.72 0.25 116.82 ;
		END

		ANTENNAGATEAREA 0.014 ;
		ANTENNADIFFAREA 0.018 ;
		ANTENNAPARTIALMETALAREA 0.025 ;
	END wen[65]

	PIN wen[66]
		USE SIGNAL ;
		DIRECTION INPUT ;
		SHAPE ABUTMENT ;
		PORT
			LAYER	M1 ;
			RECT	0 117.37 0.25 117.47 ;
			LAYER	M2 ;
			RECT	0 117.37 0.25 117.47 ;
			LAYER	M3 ;
			RECT	0 117.37 0.25 117.47 ;
		END

		ANTENNAGATEAREA 0.014 ;
		ANTENNADIFFAREA 0.018 ;
		ANTENNAPARTIALMETALAREA 0.025 ;
	END wen[66]

	PIN wen[67]
		USE SIGNAL ;
		DIRECTION INPUT ;
		SHAPE ABUTMENT ;
		PORT
			LAYER	M1 ;
			RECT	0 119.56 0.25 119.66 ;
			LAYER	M2 ;
			RECT	0 119.56 0.25 119.66 ;
			LAYER	M3 ;
			RECT	0 119.56 0.25 119.66 ;
		END

		ANTENNAGATEAREA 0.014 ;
		ANTENNADIFFAREA 0.018 ;
		ANTENNAPARTIALMETALAREA 0.025 ;
	END wen[67]

	PIN wen[68]
		USE SIGNAL ;
		DIRECTION INPUT ;
		SHAPE ABUTMENT ;
		PORT
			LAYER	M1 ;
			RECT	0 120.21 0.25 120.31 ;
			LAYER	M2 ;
			RECT	0 120.21 0.25 120.31 ;
			LAYER	M3 ;
			RECT	0 120.21 0.25 120.31 ;
		END

		ANTENNAGATEAREA 0.014 ;
		ANTENNADIFFAREA 0.018 ;
		ANTENNAPARTIALMETALAREA 0.025 ;
	END wen[68]

	PIN wen[69]
		USE SIGNAL ;
		DIRECTION INPUT ;
		SHAPE ABUTMENT ;
		PORT
			LAYER	M1 ;
			RECT	0 122.4 0.25 122.5 ;
			LAYER	M2 ;
			RECT	0 122.4 0.25 122.5 ;
			LAYER	M3 ;
			RECT	0 122.4 0.25 122.5 ;
		END

		ANTENNAGATEAREA 0.014 ;
		ANTENNADIFFAREA 0.018 ;
		ANTENNAPARTIALMETALAREA 0.025 ;
	END wen[69]

	PIN wen[6]
		USE SIGNAL ;
		DIRECTION INPUT ;
		SHAPE ABUTMENT ;
		PORT
			LAYER	M1 ;
			RECT	0 9.685 0.25 9.785 ;
			LAYER	M2 ;
			RECT	0 9.685 0.25 9.785 ;
			LAYER	M3 ;
			RECT	0 9.685 0.25 9.785 ;
		END

		ANTENNAGATEAREA 0.014 ;
		ANTENNADIFFAREA 0.018 ;
		ANTENNAPARTIALMETALAREA 0.025 ;
	END wen[6]

	PIN wen[70]
		USE SIGNAL ;
		DIRECTION INPUT ;
		SHAPE ABUTMENT ;
		PORT
			LAYER	M1 ;
			RECT	0 123.05 0.25 123.15 ;
			LAYER	M2 ;
			RECT	0 123.05 0.25 123.15 ;
			LAYER	M3 ;
			RECT	0 123.05 0.25 123.15 ;
		END

		ANTENNAGATEAREA 0.014 ;
		ANTENNADIFFAREA 0.018 ;
		ANTENNAPARTIALMETALAREA 0.025 ;
	END wen[70]

	PIN wen[71]
		USE SIGNAL ;
		DIRECTION INPUT ;
		SHAPE ABUTMENT ;
		PORT
			LAYER	M1 ;
			RECT	0 125.24 0.25 125.34 ;
			LAYER	M2 ;
			RECT	0 125.24 0.25 125.34 ;
			LAYER	M3 ;
			RECT	0 125.24 0.25 125.34 ;
		END

		ANTENNAGATEAREA 0.014 ;
		ANTENNADIFFAREA 0.018 ;
		ANTENNAPARTIALMETALAREA 0.025 ;
	END wen[71]

	PIN wen[72]
		USE SIGNAL ;
		DIRECTION INPUT ;
		SHAPE ABUTMENT ;
		PORT
			LAYER	M1 ;
			RECT	0 125.89 0.25 125.99 ;
			LAYER	M2 ;
			RECT	0 125.89 0.25 125.99 ;
			LAYER	M3 ;
			RECT	0 125.89 0.25 125.99 ;
		END

		ANTENNAGATEAREA 0.014 ;
		ANTENNADIFFAREA 0.018 ;
		ANTENNAPARTIALMETALAREA 0.025 ;
	END wen[72]

	PIN wen[73]
		USE SIGNAL ;
		DIRECTION INPUT ;
		SHAPE ABUTMENT ;
		PORT
			LAYER	M1 ;
			RECT	0 128.08 0.25 128.18 ;
			LAYER	M2 ;
			RECT	0 128.08 0.25 128.18 ;
			LAYER	M3 ;
			RECT	0 128.08 0.25 128.18 ;
		END

		ANTENNAGATEAREA 0.014 ;
		ANTENNADIFFAREA 0.018 ;
		ANTENNAPARTIALMETALAREA 0.025 ;
	END wen[73]

	PIN wen[74]
		USE SIGNAL ;
		DIRECTION INPUT ;
		SHAPE ABUTMENT ;
		PORT
			LAYER	M1 ;
			RECT	0 128.73 0.25 128.83 ;
			LAYER	M2 ;
			RECT	0 128.73 0.25 128.83 ;
			LAYER	M3 ;
			RECT	0 128.73 0.25 128.83 ;
		END

		ANTENNAGATEAREA 0.014 ;
		ANTENNADIFFAREA 0.018 ;
		ANTENNAPARTIALMETALAREA 0.025 ;
	END wen[74]

	PIN wen[75]
		USE SIGNAL ;
		DIRECTION INPUT ;
		SHAPE ABUTMENT ;
		PORT
			LAYER	M1 ;
			RECT	0 130.92 0.25 131.02 ;
			LAYER	M2 ;
			RECT	0 130.92 0.25 131.02 ;
			LAYER	M3 ;
			RECT	0 130.92 0.25 131.02 ;
		END

		ANTENNAGATEAREA 0.014 ;
		ANTENNADIFFAREA 0.018 ;
		ANTENNAPARTIALMETALAREA 0.025 ;
	END wen[75]

	PIN wen[76]
		USE SIGNAL ;
		DIRECTION INPUT ;
		SHAPE ABUTMENT ;
		PORT
			LAYER	M1 ;
			RECT	0 131.57 0.25 131.67 ;
			LAYER	M2 ;
			RECT	0 131.57 0.25 131.67 ;
			LAYER	M3 ;
			RECT	0 131.57 0.25 131.67 ;
		END

		ANTENNAGATEAREA 0.014 ;
		ANTENNADIFFAREA 0.018 ;
		ANTENNAPARTIALMETALAREA 0.025 ;
	END wen[76]

	PIN wen[77]
		USE SIGNAL ;
		DIRECTION INPUT ;
		SHAPE ABUTMENT ;
		PORT
			LAYER	M1 ;
			RECT	0 133.76 0.25 133.86 ;
			LAYER	M2 ;
			RECT	0 133.76 0.25 133.86 ;
			LAYER	M3 ;
			RECT	0 133.76 0.25 133.86 ;
		END

		ANTENNAGATEAREA 0.014 ;
		ANTENNADIFFAREA 0.018 ;
		ANTENNAPARTIALMETALAREA 0.025 ;
	END wen[77]

	PIN wen[78]
		USE SIGNAL ;
		DIRECTION INPUT ;
		SHAPE ABUTMENT ;
		PORT
			LAYER	M1 ;
			RECT	0 134.41 0.25 134.51 ;
			LAYER	M2 ;
			RECT	0 134.41 0.25 134.51 ;
			LAYER	M3 ;
			RECT	0 134.41 0.25 134.51 ;
		END

		ANTENNAGATEAREA 0.014 ;
		ANTENNADIFFAREA 0.018 ;
		ANTENNAPARTIALMETALAREA 0.025 ;
	END wen[78]

	PIN wen[79]
		USE SIGNAL ;
		DIRECTION INPUT ;
		SHAPE ABUTMENT ;
		PORT
			LAYER	M1 ;
			RECT	0 136.6 0.25 136.7 ;
			LAYER	M2 ;
			RECT	0 136.6 0.25 136.7 ;
			LAYER	M3 ;
			RECT	0 136.6 0.25 136.7 ;
		END

		ANTENNAGATEAREA 0.014 ;
		ANTENNADIFFAREA 0.018 ;
		ANTENNAPARTIALMETALAREA 0.025 ;
	END wen[79]

	PIN wen[7]
		USE SIGNAL ;
		DIRECTION INPUT ;
		SHAPE ABUTMENT ;
		PORT
			LAYER	M1 ;
			RECT	0 11.875 0.25 11.975 ;
			LAYER	M2 ;
			RECT	0 11.875 0.25 11.975 ;
			LAYER	M3 ;
			RECT	0 11.875 0.25 11.975 ;
		END

		ANTENNAGATEAREA 0.014 ;
		ANTENNADIFFAREA 0.018 ;
		ANTENNAPARTIALMETALAREA 0.025 ;
	END wen[7]

	PIN wen[80]
		USE SIGNAL ;
		DIRECTION INPUT ;
		SHAPE ABUTMENT ;
		PORT
			LAYER	M1 ;
			RECT	0 137.25 0.25 137.35 ;
			LAYER	M2 ;
			RECT	0 137.25 0.25 137.35 ;
			LAYER	M3 ;
			RECT	0 137.25 0.25 137.35 ;
		END

		ANTENNAGATEAREA 0.014 ;
		ANTENNADIFFAREA 0.018 ;
		ANTENNAPARTIALMETALAREA 0.025 ;
	END wen[80]

	PIN wen[81]
		USE SIGNAL ;
		DIRECTION INPUT ;
		SHAPE ABUTMENT ;
		PORT
			LAYER	M1 ;
			RECT	0 139.44 0.25 139.54 ;
			LAYER	M2 ;
			RECT	0 139.44 0.25 139.54 ;
			LAYER	M3 ;
			RECT	0 139.44 0.25 139.54 ;
		END

		ANTENNAGATEAREA 0.014 ;
		ANTENNADIFFAREA 0.018 ;
		ANTENNAPARTIALMETALAREA 0.025 ;
	END wen[81]

	PIN wen[82]
		USE SIGNAL ;
		DIRECTION INPUT ;
		SHAPE ABUTMENT ;
		PORT
			LAYER	M1 ;
			RECT	0 140.09 0.25 140.19 ;
			LAYER	M2 ;
			RECT	0 140.09 0.25 140.19 ;
			LAYER	M3 ;
			RECT	0 140.09 0.25 140.19 ;
		END

		ANTENNAGATEAREA 0.014 ;
		ANTENNADIFFAREA 0.018 ;
		ANTENNAPARTIALMETALAREA 0.025 ;
	END wen[82]

	PIN wen[83]
		USE SIGNAL ;
		DIRECTION INPUT ;
		SHAPE ABUTMENT ;
		PORT
			LAYER	M1 ;
			RECT	0 142.28 0.25 142.38 ;
			LAYER	M2 ;
			RECT	0 142.28 0.25 142.38 ;
			LAYER	M3 ;
			RECT	0 142.28 0.25 142.38 ;
		END

		ANTENNAGATEAREA 0.014 ;
		ANTENNADIFFAREA 0.018 ;
		ANTENNAPARTIALMETALAREA 0.025 ;
	END wen[83]

	PIN wen[84]
		USE SIGNAL ;
		DIRECTION INPUT ;
		SHAPE ABUTMENT ;
		PORT
			LAYER	M1 ;
			RECT	0 142.93 0.25 143.03 ;
			LAYER	M2 ;
			RECT	0 142.93 0.25 143.03 ;
			LAYER	M3 ;
			RECT	0 142.93 0.25 143.03 ;
		END

		ANTENNAGATEAREA 0.014 ;
		ANTENNADIFFAREA 0.018 ;
		ANTENNAPARTIALMETALAREA 0.025 ;
	END wen[84]

	PIN wen[85]
		USE SIGNAL ;
		DIRECTION INPUT ;
		SHAPE ABUTMENT ;
		PORT
			LAYER	M1 ;
			RECT	0 145.12 0.25 145.22 ;
			LAYER	M2 ;
			RECT	0 145.12 0.25 145.22 ;
			LAYER	M3 ;
			RECT	0 145.12 0.25 145.22 ;
		END

		ANTENNAGATEAREA 0.014 ;
		ANTENNADIFFAREA 0.018 ;
		ANTENNAPARTIALMETALAREA 0.025 ;
	END wen[85]

	PIN wen[86]
		USE SIGNAL ;
		DIRECTION INPUT ;
		SHAPE ABUTMENT ;
		PORT
			LAYER	M1 ;
			RECT	0 145.77 0.25 145.87 ;
			LAYER	M2 ;
			RECT	0 145.77 0.25 145.87 ;
			LAYER	M3 ;
			RECT	0 145.77 0.25 145.87 ;
		END

		ANTENNAGATEAREA 0.014 ;
		ANTENNADIFFAREA 0.018 ;
		ANTENNAPARTIALMETALAREA 0.025 ;
	END wen[86]

	PIN wen[87]
		USE SIGNAL ;
		DIRECTION INPUT ;
		SHAPE ABUTMENT ;
		PORT
			LAYER	M1 ;
			RECT	0 147.96 0.25 148.06 ;
			LAYER	M2 ;
			RECT	0 147.96 0.25 148.06 ;
			LAYER	M3 ;
			RECT	0 147.96 0.25 148.06 ;
		END

		ANTENNAGATEAREA 0.014 ;
		ANTENNADIFFAREA 0.018 ;
		ANTENNAPARTIALMETALAREA 0.025 ;
	END wen[87]

	PIN wen[88]
		USE SIGNAL ;
		DIRECTION INPUT ;
		SHAPE ABUTMENT ;
		PORT
			LAYER	M1 ;
			RECT	0 148.61 0.25 148.71 ;
			LAYER	M2 ;
			RECT	0 148.61 0.25 148.71 ;
			LAYER	M3 ;
			RECT	0 148.61 0.25 148.71 ;
		END

		ANTENNAGATEAREA 0.014 ;
		ANTENNADIFFAREA 0.018 ;
		ANTENNAPARTIALMETALAREA 0.025 ;
	END wen[88]

	PIN wen[89]
		USE SIGNAL ;
		DIRECTION INPUT ;
		SHAPE ABUTMENT ;
		PORT
			LAYER	M1 ;
			RECT	0 150.8 0.25 150.9 ;
			LAYER	M2 ;
			RECT	0 150.8 0.25 150.9 ;
			LAYER	M3 ;
			RECT	0 150.8 0.25 150.9 ;
		END

		ANTENNAGATEAREA 0.014 ;
		ANTENNADIFFAREA 0.018 ;
		ANTENNAPARTIALMETALAREA 0.025 ;
	END wen[89]

	PIN wen[8]
		USE SIGNAL ;
		DIRECTION INPUT ;
		SHAPE ABUTMENT ;
		PORT
			LAYER	M1 ;
			RECT	0 12.525 0.25 12.625 ;
			LAYER	M2 ;
			RECT	0 12.525 0.25 12.625 ;
			LAYER	M3 ;
			RECT	0 12.525 0.25 12.625 ;
		END

		ANTENNAGATEAREA 0.014 ;
		ANTENNADIFFAREA 0.018 ;
		ANTENNAPARTIALMETALAREA 0.025 ;
	END wen[8]

	PIN wen[90]
		USE SIGNAL ;
		DIRECTION INPUT ;
		SHAPE ABUTMENT ;
		PORT
			LAYER	M1 ;
			RECT	0 151.45 0.25 151.55 ;
			LAYER	M2 ;
			RECT	0 151.45 0.25 151.55 ;
			LAYER	M3 ;
			RECT	0 151.45 0.25 151.55 ;
		END

		ANTENNAGATEAREA 0.014 ;
		ANTENNADIFFAREA 0.018 ;
		ANTENNAPARTIALMETALAREA 0.025 ;
	END wen[90]

	PIN wen[91]
		USE SIGNAL ;
		DIRECTION INPUT ;
		SHAPE ABUTMENT ;
		PORT
			LAYER	M1 ;
			RECT	0 153.64 0.25 153.74 ;
			LAYER	M2 ;
			RECT	0 153.64 0.25 153.74 ;
			LAYER	M3 ;
			RECT	0 153.64 0.25 153.74 ;
		END

		ANTENNAGATEAREA 0.014 ;
		ANTENNADIFFAREA 0.018 ;
		ANTENNAPARTIALMETALAREA 0.025 ;
	END wen[91]

	PIN wen[92]
		USE SIGNAL ;
		DIRECTION INPUT ;
		SHAPE ABUTMENT ;
		PORT
			LAYER	M1 ;
			RECT	0 154.29 0.25 154.39 ;
			LAYER	M2 ;
			RECT	0 154.29 0.25 154.39 ;
			LAYER	M3 ;
			RECT	0 154.29 0.25 154.39 ;
		END

		ANTENNAGATEAREA 0.014 ;
		ANTENNADIFFAREA 0.018 ;
		ANTENNAPARTIALMETALAREA 0.025 ;
	END wen[92]

	PIN wen[93]
		USE SIGNAL ;
		DIRECTION INPUT ;
		SHAPE ABUTMENT ;
		PORT
			LAYER	M1 ;
			RECT	0 156.48 0.25 156.58 ;
			LAYER	M2 ;
			RECT	0 156.48 0.25 156.58 ;
			LAYER	M3 ;
			RECT	0 156.48 0.25 156.58 ;
		END

		ANTENNAGATEAREA 0.014 ;
		ANTENNADIFFAREA 0.018 ;
		ANTENNAPARTIALMETALAREA 0.025 ;
	END wen[93]

	PIN wen[94]
		USE SIGNAL ;
		DIRECTION INPUT ;
		SHAPE ABUTMENT ;
		PORT
			LAYER	M1 ;
			RECT	0 157.13 0.25 157.23 ;
			LAYER	M2 ;
			RECT	0 157.13 0.25 157.23 ;
			LAYER	M3 ;
			RECT	0 157.13 0.25 157.23 ;
		END

		ANTENNAGATEAREA 0.014 ;
		ANTENNADIFFAREA 0.018 ;
		ANTENNAPARTIALMETALAREA 0.025 ;
	END wen[94]

	PIN wen[95]
		USE SIGNAL ;
		DIRECTION INPUT ;
		SHAPE ABUTMENT ;
		PORT
			LAYER	M1 ;
			RECT	0 159.32 0.25 159.42 ;
			LAYER	M2 ;
			RECT	0 159.32 0.25 159.42 ;
			LAYER	M3 ;
			RECT	0 159.32 0.25 159.42 ;
		END

		ANTENNAGATEAREA 0.014 ;
		ANTENNADIFFAREA 0.018 ;
		ANTENNAPARTIALMETALAREA 0.025 ;
	END wen[95]

	PIN wen[96]
		USE SIGNAL ;
		DIRECTION INPUT ;
		SHAPE ABUTMENT ;
		PORT
			LAYER	M1 ;
			RECT	0 159.97 0.25 160.07 ;
			LAYER	M2 ;
			RECT	0 159.97 0.25 160.07 ;
			LAYER	M3 ;
			RECT	0 159.97 0.25 160.07 ;
		END

		ANTENNAGATEAREA 0.014 ;
		ANTENNADIFFAREA 0.018 ;
		ANTENNAPARTIALMETALAREA 0.025 ;
	END wen[96]

	PIN wen[97]
		USE SIGNAL ;
		DIRECTION INPUT ;
		SHAPE ABUTMENT ;
		PORT
			LAYER	M1 ;
			RECT	0 162.16 0.25 162.26 ;
			LAYER	M2 ;
			RECT	0 162.16 0.25 162.26 ;
			LAYER	M3 ;
			RECT	0 162.16 0.25 162.26 ;
		END

		ANTENNAGATEAREA 0.014 ;
		ANTENNADIFFAREA 0.018 ;
		ANTENNAPARTIALMETALAREA 0.025 ;
	END wen[97]

	PIN wen[98]
		USE SIGNAL ;
		DIRECTION INPUT ;
		SHAPE ABUTMENT ;
		PORT
			LAYER	M1 ;
			RECT	0 162.81 0.25 162.91 ;
			LAYER	M2 ;
			RECT	0 162.81 0.25 162.91 ;
			LAYER	M3 ;
			RECT	0 162.81 0.25 162.91 ;
		END

		ANTENNAGATEAREA 0.014 ;
		ANTENNADIFFAREA 0.018 ;
		ANTENNAPARTIALMETALAREA 0.025 ;
	END wen[98]

	PIN wen[99]
		USE SIGNAL ;
		DIRECTION INPUT ;
		SHAPE ABUTMENT ;
		PORT
			LAYER	M1 ;
			RECT	0 165 0.25 165.1 ;
			LAYER	M2 ;
			RECT	0 165 0.25 165.1 ;
			LAYER	M3 ;
			RECT	0 165 0.25 165.1 ;
		END

		ANTENNAGATEAREA 0.014 ;
		ANTENNADIFFAREA 0.018 ;
		ANTENNAPARTIALMETALAREA 0.025 ;
	END wen[99]

	PIN wen[9]
		USE SIGNAL ;
		DIRECTION INPUT ;
		SHAPE ABUTMENT ;
		PORT
			LAYER	M1 ;
			RECT	0 14.715 0.25 14.815 ;
			LAYER	M2 ;
			RECT	0 14.715 0.25 14.815 ;
			LAYER	M3 ;
			RECT	0 14.715 0.25 14.815 ;
		END

		ANTENNAGATEAREA 0.014 ;
		ANTENNADIFFAREA 0.018 ;
		ANTENNAPARTIALMETALAREA 0.025 ;
	END wen[9]

	OBS
		LAYER	M1 DESIGNRULEWIDTH 0.165 ;
		RECT	0.32 0.3 34.64 205.725 ;
		RECT	0 0 0.32 1.115 ;
		RECT	0 1.515 0.32 1.945 ;
		RECT	0 2.145 0.32 2.475 ;
		RECT	0 2.675 0.32 3.105 ;
		RECT	0 3.505 0.32 3.955 ;
		RECT	0 4.355 0.32 4.785 ;
		RECT	0 4.985 0.32 5.315 ;
		RECT	0 5.515 0.32 5.945 ;
		RECT	0 6.345 0.32 6.795 ;
		RECT	0 7.195 0.32 7.625 ;
		RECT	0 7.825 0.32 8.155 ;
		RECT	0 8.355 0.32 8.785 ;
		RECT	0 9.185 0.32 9.635 ;
		RECT	0 10.035 0.32 10.465 ;
		RECT	0 10.665 0.32 10.995 ;
		RECT	0 11.195 0.32 11.625 ;
		RECT	0 12.025 0.32 12.475 ;
		RECT	0 12.875 0.32 13.305 ;
		RECT	0 13.505 0.32 13.835 ;
		RECT	0 14.035 0.32 14.465 ;
		RECT	0 14.865 0.32 15.315 ;
		RECT	0 15.715 0.32 16.145 ;
		RECT	0 16.345 0.32 16.675 ;
		RECT	0 16.875 0.32 17.305 ;
		RECT	0 17.705 0.32 18.155 ;
		RECT	0 18.555 0.32 18.985 ;
		RECT	0 19.185 0.32 19.515 ;
		RECT	0 19.715 0.32 20.145 ;
		RECT	0 20.545 0.32 20.995 ;
		RECT	0 21.395 0.32 21.825 ;
		RECT	0 22.025 0.32 22.355 ;
		RECT	0 22.555 0.32 22.985 ;
		RECT	0 23.385 0.32 23.835 ;
		RECT	0 24.235 0.32 24.665 ;
		RECT	0 24.865 0.32 25.195 ;
		RECT	0 25.395 0.32 25.825 ;
		RECT	0 26.225 0.32 26.675 ;
		RECT	0 27.075 0.32 27.505 ;
		RECT	0 27.705 0.32 28.035 ;
		RECT	0 28.235 0.32 28.665 ;
		RECT	0 29.065 0.32 29.515 ;
		RECT	0 29.915 0.32 30.345 ;
		RECT	0 30.545 0.32 30.875 ;
		RECT	0 31.075 0.32 31.505 ;
		RECT	0 31.905 0.32 32.355 ;
		RECT	0 32.755 0.32 33.185 ;
		RECT	0 33.385 0.32 33.715 ;
		RECT	0 33.915 0.32 34.345 ;
		RECT	0 34.745 0.32 35.195 ;
		RECT	0 35.595 0.32 36.025 ;
		RECT	0 36.225 0.32 36.555 ;
		RECT	0 36.755 0.32 37.185 ;
		RECT	0 37.585 0.32 38.035 ;
		RECT	0 38.435 0.32 38.865 ;
		RECT	0 39.065 0.32 39.395 ;
		RECT	0 39.595 0.32 40.025 ;
		RECT	0 40.425 0.32 40.875 ;
		RECT	0 41.275 0.32 41.705 ;
		RECT	0 41.905 0.32 42.235 ;
		RECT	0 42.435 0.32 42.865 ;
		RECT	0 43.265 0.32 43.715 ;
		RECT	0 44.115 0.32 44.545 ;
		RECT	0 44.745 0.32 45.075 ;
		RECT	0 45.275 0.32 45.705 ;
		RECT	0 46.105 0.32 46.555 ;
		RECT	0 46.955 0.32 47.385 ;
		RECT	0 47.585 0.32 47.915 ;
		RECT	0 48.115 0.32 48.545 ;
		RECT	0 48.945 0.32 49.395 ;
		RECT	0 49.795 0.32 50.225 ;
		RECT	0 50.425 0.32 50.755 ;
		RECT	0 50.955 0.32 51.385 ;
		RECT	0 51.785 0.32 52.235 ;
		RECT	0 52.635 0.32 53.065 ;
		RECT	0 53.265 0.32 53.595 ;
		RECT	0 53.795 0.32 54.225 ;
		RECT	0 54.625 0.32 55.075 ;
		RECT	0 55.475 0.32 55.905 ;
		RECT	0 56.105 0.32 56.435 ;
		RECT	0 56.635 0.32 57.065 ;
		RECT	0 57.465 0.32 57.915 ;
		RECT	0 58.315 0.32 58.745 ;
		RECT	0 58.945 0.32 59.275 ;
		RECT	0 59.475 0.32 59.905 ;
		RECT	0 60.305 0.32 60.755 ;
		RECT	0 61.155 0.32 61.585 ;
		RECT	0 61.785 0.32 62.115 ;
		RECT	0 62.315 0.32 62.745 ;
		RECT	0 63.145 0.32 63.595 ;
		RECT	0 63.995 0.32 64.425 ;
		RECT	0 64.625 0.32 64.955 ;
		RECT	0 65.155 0.32 65.585 ;
		RECT	0 65.985 0.32 66.435 ;
		RECT	0 66.835 0.32 67.265 ;
		RECT	0 67.465 0.32 67.795 ;
		RECT	0 67.995 0.32 68.425 ;
		RECT	0 68.825 0.32 69.275 ;
		RECT	0 69.675 0.32 70.105 ;
		RECT	0 70.305 0.32 70.635 ;
		RECT	0 70.835 0.32 71.265 ;
		RECT	0 71.665 0.32 72.115 ;
		RECT	0 72.515 0.32 72.945 ;
		RECT	0 73.145 0.32 73.475 ;
		RECT	0 73.675 0.32 74.105 ;
		RECT	0 74.505 0.32 74.955 ;
		RECT	0 75.355 0.32 75.785 ;
		RECT	0 75.985 0.32 76.315 ;
		RECT	0 76.515 0.32 76.945 ;
		RECT	0 77.345 0.32 77.795 ;
		RECT	0 78.195 0.32 78.625 ;
		RECT	0 78.825 0.32 79.155 ;
		RECT	0 79.355 0.32 79.785 ;
		RECT	0 80.185 0.32 80.635 ;
		RECT	0 81.035 0.32 81.465 ;
		RECT	0 81.665 0.32 81.995 ;
		RECT	0 82.195 0.32 82.625 ;
		RECT	0 83.025 0.32 83.475 ;
		RECT	0 83.875 0.32 84.305 ;
		RECT	0 84.505 0.32 84.835 ;
		RECT	0 85.035 0.32 85.465 ;
		RECT	0 85.865 0.32 86.315 ;
		RECT	0 86.715 0.32 87.145 ;
		RECT	0 87.345 0.32 87.675 ;
		RECT	0 87.875 0.32 88.305 ;
		RECT	0 88.705 0.32 89.155 ;
		RECT	0 89.555 0.32 89.985 ;
		RECT	0 90.185 0.32 90.515 ;
		RECT	0 90.715 0.32 91.145 ;
		RECT	0 91.545 0.32 94.015 ;
		RECT	0 94.215 0.32 96.46 ;
		RECT	0 96.66 0.32 96.85 ;
		RECT	0 97.05 0.32 97.975 ;
		RECT	0 98.175 0.32 99.84 ;
		RECT	0 100.04 0.32 100.44 ;
		RECT	0 100.64 0.32 100.84 ;
		RECT	0 101.04 0.32 102.75 ;
		RECT	0 102.95 0.32 103.08 ;
		RECT	0 103.28 0.32 105.185 ;
		RECT	0 105.385 0.32 105.655 ;
		RECT	0 106.255 0.32 106.455 ;
		RECT	0 106.655 0.32 112.335 ;
		RECT	0 112.535 0.32 112.71 ;
		RECT	0 112.91 0.32 114.48 ;
		RECT	0 114.88 0.32 115.31 ;
		RECT	0 115.51 0.32 115.84 ;
		RECT	0 116.04 0.32 116.47 ;
		RECT	0 116.87 0.32 117.32 ;
		RECT	0 117.72 0.32 118.15 ;
		RECT	0 118.35 0.32 118.68 ;
		RECT	0 118.88 0.32 119.31 ;
		RECT	0 119.71 0.32 120.16 ;
		RECT	0 120.56 0.32 120.99 ;
		RECT	0 121.19 0.32 121.52 ;
		RECT	0 121.72 0.32 122.15 ;
		RECT	0 122.55 0.32 123 ;
		RECT	0 123.4 0.32 123.83 ;
		RECT	0 124.03 0.32 124.36 ;
		RECT	0 124.56 0.32 124.99 ;
		RECT	0 125.39 0.32 125.84 ;
		RECT	0 126.24 0.32 126.67 ;
		RECT	0 126.87 0.32 127.2 ;
		RECT	0 127.4 0.32 127.83 ;
		RECT	0 128.23 0.32 128.68 ;
		RECT	0 129.08 0.32 129.51 ;
		RECT	0 129.71 0.32 130.04 ;
		RECT	0 130.24 0.32 130.67 ;
		RECT	0 131.07 0.32 131.52 ;
		RECT	0 131.92 0.32 132.35 ;
		RECT	0 132.55 0.32 132.88 ;
		RECT	0 133.08 0.32 133.51 ;
		RECT	0 133.91 0.32 134.36 ;
		RECT	0 134.76 0.32 135.19 ;
		RECT	0 135.39 0.32 135.72 ;
		RECT	0 135.92 0.32 136.35 ;
		RECT	0 136.75 0.32 137.2 ;
		RECT	0 137.6 0.32 138.03 ;
		RECT	0 138.23 0.32 138.56 ;
		RECT	0 138.76 0.32 139.19 ;
		RECT	0 139.59 0.32 140.04 ;
		RECT	0 140.44 0.32 140.87 ;
		RECT	0 141.07 0.32 141.4 ;
		RECT	0 141.6 0.32 142.03 ;
		RECT	0 142.43 0.32 142.88 ;
		RECT	0 143.28 0.32 143.71 ;
		RECT	0 143.91 0.32 144.24 ;
		RECT	0 144.44 0.32 144.87 ;
		RECT	0 145.27 0.32 145.72 ;
		RECT	0 146.12 0.32 146.55 ;
		RECT	0 146.75 0.32 147.08 ;
		RECT	0 147.28 0.32 147.71 ;
		RECT	0 148.11 0.32 148.56 ;
		RECT	0 148.96 0.32 149.39 ;
		RECT	0 149.59 0.32 149.92 ;
		RECT	0 150.12 0.32 150.55 ;
		RECT	0 150.95 0.32 151.4 ;
		RECT	0 151.8 0.32 152.23 ;
		RECT	0 152.43 0.32 152.76 ;
		RECT	0 152.96 0.32 153.39 ;
		RECT	0 153.79 0.32 154.24 ;
		RECT	0 154.64 0.32 155.07 ;
		RECT	0 155.27 0.32 155.6 ;
		RECT	0 155.8 0.32 156.23 ;
		RECT	0 156.63 0.32 157.08 ;
		RECT	0 157.48 0.32 157.91 ;
		RECT	0 158.11 0.32 158.44 ;
		RECT	0 158.64 0.32 159.07 ;
		RECT	0 159.47 0.32 159.92 ;
		RECT	0 160.32 0.32 160.75 ;
		RECT	0 160.95 0.32 161.28 ;
		RECT	0 161.48 0.32 161.91 ;
		RECT	0 162.31 0.32 162.76 ;
		RECT	0 163.16 0.32 163.59 ;
		RECT	0 163.79 0.32 164.12 ;
		RECT	0 164.32 0.32 164.75 ;
		RECT	0 165.15 0.32 165.6 ;
		RECT	0 166 0.32 166.43 ;
		RECT	0 166.63 0.32 166.96 ;
		RECT	0 167.16 0.32 167.59 ;
		RECT	0 167.99 0.32 168.44 ;
		RECT	0 168.84 0.32 169.27 ;
		RECT	0 169.47 0.32 169.8 ;
		RECT	0 170 0.32 170.43 ;
		RECT	0 170.83 0.32 171.28 ;
		RECT	0 171.68 0.32 172.11 ;
		RECT	0 172.31 0.32 172.64 ;
		RECT	0 172.84 0.32 173.27 ;
		RECT	0 173.67 0.32 174.12 ;
		RECT	0 174.52 0.32 174.95 ;
		RECT	0 175.15 0.32 175.48 ;
		RECT	0 175.68 0.32 176.11 ;
		RECT	0 176.51 0.32 176.96 ;
		RECT	0 177.36 0.32 177.79 ;
		RECT	0 177.99 0.32 178.32 ;
		RECT	0 178.52 0.32 178.95 ;
		RECT	0 179.35 0.32 179.8 ;
		RECT	0 180.2 0.32 180.63 ;
		RECT	0 180.83 0.32 181.16 ;
		RECT	0 181.36 0.32 181.79 ;
		RECT	0 182.19 0.32 182.64 ;
		RECT	0 183.04 0.32 183.47 ;
		RECT	0 183.67 0.32 184 ;
		RECT	0 184.2 0.32 184.63 ;
		RECT	0 185.03 0.32 185.48 ;
		RECT	0 185.88 0.32 186.31 ;
		RECT	0 186.51 0.32 186.84 ;
		RECT	0 187.04 0.32 187.47 ;
		RECT	0 187.87 0.32 188.32 ;
		RECT	0 188.72 0.32 189.15 ;
		RECT	0 189.35 0.32 189.68 ;
		RECT	0 189.88 0.32 190.31 ;
		RECT	0 190.71 0.32 191.16 ;
		RECT	0 191.56 0.32 191.99 ;
		RECT	0 192.19 0.32 192.52 ;
		RECT	0 192.72 0.32 193.15 ;
		RECT	0 193.55 0.32 194 ;
		RECT	0 194.4 0.32 194.83 ;
		RECT	0 195.03 0.32 195.36 ;
		RECT	0 195.56 0.32 195.99 ;
		RECT	0 196.39 0.32 196.84 ;
		RECT	0 197.24 0.32 197.67 ;
		RECT	0 197.87 0.32 198.2 ;
		RECT	0 198.4 0.32 198.83 ;
		RECT	0 199.23 0.32 199.68 ;
		RECT	0 200.08 0.32 200.51 ;
		RECT	0 200.71 0.32 201.04 ;
		RECT	0 201.24 0.32 201.67 ;
		RECT	0 202.07 0.32 202.52 ;
		RECT	0 202.92 0.32 203.35 ;
		RECT	0 203.55 0.32 203.88 ;
		RECT	0 204.08 0.32 204.51 ;
		RECT	0 204.91 0.32 206.025 ;
		RECT	34.64 0 34.96 206.025 ;
		RECT	0.32 0 34.64 0.3 ;
		RECT	0.32 205.725 34.64 206.025 ;
		LAYER	M2 DESIGNRULEWIDTH 0.165 ;
		RECT	0.32 0.3 34.64 205.725 ;
		RECT	0 0 0.32 1.115 ;
		RECT	0 1.515 0.32 1.945 ;
		RECT	0 2.145 0.32 2.475 ;
		RECT	0 2.675 0.32 3.105 ;
		RECT	0 3.505 0.32 3.955 ;
		RECT	0 4.355 0.32 4.785 ;
		RECT	0 4.985 0.32 5.315 ;
		RECT	0 5.515 0.32 5.945 ;
		RECT	0 6.345 0.32 6.795 ;
		RECT	0 7.195 0.32 7.625 ;
		RECT	0 7.825 0.32 8.155 ;
		RECT	0 8.355 0.32 8.785 ;
		RECT	0 9.185 0.32 9.635 ;
		RECT	0 10.035 0.32 10.465 ;
		RECT	0 10.665 0.32 10.995 ;
		RECT	0 11.195 0.32 11.625 ;
		RECT	0 12.025 0.32 12.475 ;
		RECT	0 12.875 0.32 13.305 ;
		RECT	0 13.505 0.32 13.835 ;
		RECT	0 14.035 0.32 14.465 ;
		RECT	0 14.865 0.32 15.315 ;
		RECT	0 15.715 0.32 16.145 ;
		RECT	0 16.345 0.32 16.675 ;
		RECT	0 16.875 0.32 17.305 ;
		RECT	0 17.705 0.32 18.155 ;
		RECT	0 18.555 0.32 18.985 ;
		RECT	0 19.185 0.32 19.515 ;
		RECT	0 19.715 0.32 20.145 ;
		RECT	0 20.545 0.32 20.995 ;
		RECT	0 21.395 0.32 21.825 ;
		RECT	0 22.025 0.32 22.355 ;
		RECT	0 22.555 0.32 22.985 ;
		RECT	0 23.385 0.32 23.835 ;
		RECT	0 24.235 0.32 24.665 ;
		RECT	0 24.865 0.32 25.195 ;
		RECT	0 25.395 0.32 25.825 ;
		RECT	0 26.225 0.32 26.675 ;
		RECT	0 27.075 0.32 27.505 ;
		RECT	0 27.705 0.32 28.035 ;
		RECT	0 28.235 0.32 28.665 ;
		RECT	0 29.065 0.32 29.515 ;
		RECT	0 29.915 0.32 30.345 ;
		RECT	0 30.545 0.32 30.875 ;
		RECT	0 31.075 0.32 31.505 ;
		RECT	0 31.905 0.32 32.355 ;
		RECT	0 32.755 0.32 33.185 ;
		RECT	0 33.385 0.32 33.715 ;
		RECT	0 33.915 0.32 34.345 ;
		RECT	0 34.745 0.32 35.195 ;
		RECT	0 35.595 0.32 36.025 ;
		RECT	0 36.225 0.32 36.555 ;
		RECT	0 36.755 0.32 37.185 ;
		RECT	0 37.585 0.32 38.035 ;
		RECT	0 38.435 0.32 38.865 ;
		RECT	0 39.065 0.32 39.395 ;
		RECT	0 39.595 0.32 40.025 ;
		RECT	0 40.425 0.32 40.875 ;
		RECT	0 41.275 0.32 41.705 ;
		RECT	0 41.905 0.32 42.235 ;
		RECT	0 42.435 0.32 42.865 ;
		RECT	0 43.265 0.32 43.715 ;
		RECT	0 44.115 0.32 44.545 ;
		RECT	0 44.745 0.32 45.075 ;
		RECT	0 45.275 0.32 45.705 ;
		RECT	0 46.105 0.32 46.555 ;
		RECT	0 46.955 0.32 47.385 ;
		RECT	0 47.585 0.32 47.915 ;
		RECT	0 48.115 0.32 48.545 ;
		RECT	0 48.945 0.32 49.395 ;
		RECT	0 49.795 0.32 50.225 ;
		RECT	0 50.425 0.32 50.755 ;
		RECT	0 50.955 0.32 51.385 ;
		RECT	0 51.785 0.32 52.235 ;
		RECT	0 52.635 0.32 53.065 ;
		RECT	0 53.265 0.32 53.595 ;
		RECT	0 53.795 0.32 54.225 ;
		RECT	0 54.625 0.32 55.075 ;
		RECT	0 55.475 0.32 55.905 ;
		RECT	0 56.105 0.32 56.435 ;
		RECT	0 56.635 0.32 57.065 ;
		RECT	0 57.465 0.32 57.915 ;
		RECT	0 58.315 0.32 58.745 ;
		RECT	0 58.945 0.32 59.275 ;
		RECT	0 59.475 0.32 59.905 ;
		RECT	0 60.305 0.32 60.755 ;
		RECT	0 61.155 0.32 61.585 ;
		RECT	0 61.785 0.32 62.115 ;
		RECT	0 62.315 0.32 62.745 ;
		RECT	0 63.145 0.32 63.595 ;
		RECT	0 63.995 0.32 64.425 ;
		RECT	0 64.625 0.32 64.955 ;
		RECT	0 65.155 0.32 65.585 ;
		RECT	0 65.985 0.32 66.435 ;
		RECT	0 66.835 0.32 67.265 ;
		RECT	0 67.465 0.32 67.795 ;
		RECT	0 67.995 0.32 68.425 ;
		RECT	0 68.825 0.32 69.275 ;
		RECT	0 69.675 0.32 70.105 ;
		RECT	0 70.305 0.32 70.635 ;
		RECT	0 70.835 0.32 71.265 ;
		RECT	0 71.665 0.32 72.115 ;
		RECT	0 72.515 0.32 72.945 ;
		RECT	0 73.145 0.32 73.475 ;
		RECT	0 73.675 0.32 74.105 ;
		RECT	0 74.505 0.32 74.955 ;
		RECT	0 75.355 0.32 75.785 ;
		RECT	0 75.985 0.32 76.315 ;
		RECT	0 76.515 0.32 76.945 ;
		RECT	0 77.345 0.32 77.795 ;
		RECT	0 78.195 0.32 78.625 ;
		RECT	0 78.825 0.32 79.155 ;
		RECT	0 79.355 0.32 79.785 ;
		RECT	0 80.185 0.32 80.635 ;
		RECT	0 81.035 0.32 81.465 ;
		RECT	0 81.665 0.32 81.995 ;
		RECT	0 82.195 0.32 82.625 ;
		RECT	0 83.025 0.32 83.475 ;
		RECT	0 83.875 0.32 84.305 ;
		RECT	0 84.505 0.32 84.835 ;
		RECT	0 85.035 0.32 85.465 ;
		RECT	0 85.865 0.32 86.315 ;
		RECT	0 86.715 0.32 87.145 ;
		RECT	0 87.345 0.32 87.675 ;
		RECT	0 87.875 0.32 88.305 ;
		RECT	0 88.705 0.32 89.155 ;
		RECT	0 89.555 0.32 89.985 ;
		RECT	0 90.185 0.32 90.515 ;
		RECT	0 90.715 0.32 91.145 ;
		RECT	0 91.545 0.32 94.015 ;
		RECT	0 94.215 0.32 96.46 ;
		RECT	0 96.66 0.32 96.85 ;
		RECT	0 97.05 0.32 97.975 ;
		RECT	0 98.175 0.32 99.645 ;
		RECT	0 100.04 0.32 100.44 ;
		RECT	0 100.64 0.32 100.84 ;
		RECT	0 101.04 0.32 102.75 ;
		RECT	0 102.95 0.32 103.08 ;
		RECT	0 103.28 0.32 105.185 ;
		RECT	0 105.385 0.32 105.655 ;
		RECT	0 106.255 0.32 106.455 ;
		RECT	0 106.655 0.32 112.335 ;
		RECT	0 112.535 0.32 112.71 ;
		RECT	0 112.91 0.32 114.48 ;
		RECT	0 114.88 0.32 115.31 ;
		RECT	0 115.51 0.32 115.84 ;
		RECT	0 116.04 0.32 116.47 ;
		RECT	0 116.87 0.32 117.32 ;
		RECT	0 117.72 0.32 118.15 ;
		RECT	0 118.35 0.32 118.68 ;
		RECT	0 118.88 0.32 119.31 ;
		RECT	0 119.71 0.32 120.16 ;
		RECT	0 120.56 0.32 120.99 ;
		RECT	0 121.19 0.32 121.52 ;
		RECT	0 121.72 0.32 122.15 ;
		RECT	0 122.55 0.32 123 ;
		RECT	0 123.4 0.32 123.83 ;
		RECT	0 124.03 0.32 124.36 ;
		RECT	0 124.56 0.32 124.99 ;
		RECT	0 125.39 0.32 125.84 ;
		RECT	0 126.24 0.32 126.67 ;
		RECT	0 126.87 0.32 127.2 ;
		RECT	0 127.4 0.32 127.83 ;
		RECT	0 128.23 0.32 128.68 ;
		RECT	0 129.08 0.32 129.51 ;
		RECT	0 129.71 0.32 130.04 ;
		RECT	0 130.24 0.32 130.67 ;
		RECT	0 131.07 0.32 131.52 ;
		RECT	0 131.92 0.32 132.35 ;
		RECT	0 132.55 0.32 132.88 ;
		RECT	0 133.08 0.32 133.51 ;
		RECT	0 133.91 0.32 134.36 ;
		RECT	0 134.76 0.32 135.19 ;
		RECT	0 135.39 0.32 135.72 ;
		RECT	0 135.92 0.32 136.35 ;
		RECT	0 136.75 0.32 137.2 ;
		RECT	0 137.6 0.32 138.03 ;
		RECT	0 138.23 0.32 138.56 ;
		RECT	0 138.76 0.32 139.19 ;
		RECT	0 139.59 0.32 140.04 ;
		RECT	0 140.44 0.32 140.87 ;
		RECT	0 141.07 0.32 141.4 ;
		RECT	0 141.6 0.32 142.03 ;
		RECT	0 142.43 0.32 142.88 ;
		RECT	0 143.28 0.32 143.71 ;
		RECT	0 143.91 0.32 144.24 ;
		RECT	0 144.44 0.32 144.87 ;
		RECT	0 145.27 0.32 145.72 ;
		RECT	0 146.12 0.32 146.55 ;
		RECT	0 146.75 0.32 147.08 ;
		RECT	0 147.28 0.32 147.71 ;
		RECT	0 148.11 0.32 148.56 ;
		RECT	0 148.96 0.32 149.39 ;
		RECT	0 149.59 0.32 149.92 ;
		RECT	0 150.12 0.32 150.55 ;
		RECT	0 150.95 0.32 151.4 ;
		RECT	0 151.8 0.32 152.23 ;
		RECT	0 152.43 0.32 152.76 ;
		RECT	0 152.96 0.32 153.39 ;
		RECT	0 153.79 0.32 154.24 ;
		RECT	0 154.64 0.32 155.07 ;
		RECT	0 155.27 0.32 155.6 ;
		RECT	0 155.8 0.32 156.23 ;
		RECT	0 156.63 0.32 157.08 ;
		RECT	0 157.48 0.32 157.91 ;
		RECT	0 158.11 0.32 158.44 ;
		RECT	0 158.64 0.32 159.07 ;
		RECT	0 159.47 0.32 159.92 ;
		RECT	0 160.32 0.32 160.75 ;
		RECT	0 160.95 0.32 161.28 ;
		RECT	0 161.48 0.32 161.91 ;
		RECT	0 162.31 0.32 162.76 ;
		RECT	0 163.16 0.32 163.59 ;
		RECT	0 163.79 0.32 164.12 ;
		RECT	0 164.32 0.32 164.75 ;
		RECT	0 165.15 0.32 165.6 ;
		RECT	0 166 0.32 166.43 ;
		RECT	0 166.63 0.32 166.96 ;
		RECT	0 167.16 0.32 167.59 ;
		RECT	0 167.99 0.32 168.44 ;
		RECT	0 168.84 0.32 169.27 ;
		RECT	0 169.47 0.32 169.8 ;
		RECT	0 170 0.32 170.43 ;
		RECT	0 170.83 0.32 171.28 ;
		RECT	0 171.68 0.32 172.11 ;
		RECT	0 172.31 0.32 172.64 ;
		RECT	0 172.84 0.32 173.27 ;
		RECT	0 173.67 0.32 174.12 ;
		RECT	0 174.52 0.32 174.95 ;
		RECT	0 175.15 0.32 175.48 ;
		RECT	0 175.68 0.32 176.11 ;
		RECT	0 176.51 0.32 176.96 ;
		RECT	0 177.36 0.32 177.79 ;
		RECT	0 177.99 0.32 178.32 ;
		RECT	0 178.52 0.32 178.95 ;
		RECT	0 179.35 0.32 179.8 ;
		RECT	0 180.2 0.32 180.63 ;
		RECT	0 180.83 0.32 181.16 ;
		RECT	0 181.36 0.32 181.79 ;
		RECT	0 182.19 0.32 182.64 ;
		RECT	0 183.04 0.32 183.47 ;
		RECT	0 183.67 0.32 184 ;
		RECT	0 184.2 0.32 184.63 ;
		RECT	0 185.03 0.32 185.48 ;
		RECT	0 185.88 0.32 186.31 ;
		RECT	0 186.51 0.32 186.84 ;
		RECT	0 187.04 0.32 187.47 ;
		RECT	0 187.87 0.32 188.32 ;
		RECT	0 188.72 0.32 189.15 ;
		RECT	0 189.35 0.32 189.68 ;
		RECT	0 189.88 0.32 190.31 ;
		RECT	0 190.71 0.32 191.16 ;
		RECT	0 191.56 0.32 191.99 ;
		RECT	0 192.19 0.32 192.52 ;
		RECT	0 192.72 0.32 193.15 ;
		RECT	0 193.55 0.32 194 ;
		RECT	0 194.4 0.32 194.83 ;
		RECT	0 195.03 0.32 195.36 ;
		RECT	0 195.56 0.32 195.99 ;
		RECT	0 196.39 0.32 196.84 ;
		RECT	0 197.24 0.32 197.67 ;
		RECT	0 197.87 0.32 198.2 ;
		RECT	0 198.4 0.32 198.83 ;
		RECT	0 199.23 0.32 199.68 ;
		RECT	0 200.08 0.32 200.51 ;
		RECT	0 200.71 0.32 201.04 ;
		RECT	0 201.24 0.32 201.67 ;
		RECT	0 202.07 0.32 202.52 ;
		RECT	0 202.92 0.32 203.35 ;
		RECT	0 203.55 0.32 203.88 ;
		RECT	0 204.08 0.32 204.51 ;
		RECT	0 204.91 0.32 206.025 ;
		RECT	34.64 0 34.96 206.025 ;
		RECT	0.32 0 34.64 0.3 ;
		RECT	0.32 205.725 34.64 206.025 ;
		LAYER	M3 DESIGNRULEWIDTH 0.165 ;
		RECT	0.32 0.3 34.64 205.725 ;
		RECT	0 0 0.32 1.115 ;
		RECT	0 1.515 0.32 1.945 ;
		RECT	0 2.145 0.32 2.475 ;
		RECT	0 2.675 0.32 3.105 ;
		RECT	0 3.505 0.32 3.955 ;
		RECT	0 4.355 0.32 4.785 ;
		RECT	0 4.985 0.32 5.315 ;
		RECT	0 5.515 0.32 5.945 ;
		RECT	0 6.345 0.32 6.795 ;
		RECT	0 7.195 0.32 7.625 ;
		RECT	0 7.825 0.32 8.155 ;
		RECT	0 8.355 0.32 8.785 ;
		RECT	0 9.185 0.32 9.635 ;
		RECT	0 10.035 0.32 10.465 ;
		RECT	0 10.665 0.32 10.995 ;
		RECT	0 11.195 0.32 11.625 ;
		RECT	0 12.025 0.32 12.475 ;
		RECT	0 12.875 0.32 13.305 ;
		RECT	0 13.505 0.32 13.835 ;
		RECT	0 14.035 0.32 14.465 ;
		RECT	0 14.865 0.32 15.315 ;
		RECT	0 15.715 0.32 16.145 ;
		RECT	0 16.345 0.32 16.675 ;
		RECT	0 16.875 0.32 17.305 ;
		RECT	0 17.705 0.32 18.155 ;
		RECT	0 18.555 0.32 18.985 ;
		RECT	0 19.185 0.32 19.515 ;
		RECT	0 19.715 0.32 20.145 ;
		RECT	0 20.545 0.32 20.995 ;
		RECT	0 21.395 0.32 21.825 ;
		RECT	0 22.025 0.32 22.355 ;
		RECT	0 22.555 0.32 22.985 ;
		RECT	0 23.385 0.32 23.835 ;
		RECT	0 24.235 0.32 24.665 ;
		RECT	0 24.865 0.32 25.195 ;
		RECT	0 25.395 0.32 25.825 ;
		RECT	0 26.225 0.32 26.675 ;
		RECT	0 27.075 0.32 27.505 ;
		RECT	0 27.705 0.32 28.035 ;
		RECT	0 28.235 0.32 28.665 ;
		RECT	0 29.065 0.32 29.515 ;
		RECT	0 29.915 0.32 30.345 ;
		RECT	0 30.545 0.32 30.875 ;
		RECT	0 31.075 0.32 31.505 ;
		RECT	0 31.905 0.32 32.355 ;
		RECT	0 32.755 0.32 33.185 ;
		RECT	0 33.385 0.32 33.715 ;
		RECT	0 33.915 0.32 34.345 ;
		RECT	0 34.745 0.32 35.195 ;
		RECT	0 35.595 0.32 36.025 ;
		RECT	0 36.225 0.32 36.555 ;
		RECT	0 36.755 0.32 37.185 ;
		RECT	0 37.585 0.32 38.035 ;
		RECT	0 38.435 0.32 38.865 ;
		RECT	0 39.065 0.32 39.395 ;
		RECT	0 39.595 0.32 40.025 ;
		RECT	0 40.425 0.32 40.875 ;
		RECT	0 41.275 0.32 41.705 ;
		RECT	0 41.905 0.32 42.235 ;
		RECT	0 42.435 0.32 42.865 ;
		RECT	0 43.265 0.32 43.715 ;
		RECT	0 44.115 0.32 44.545 ;
		RECT	0 44.745 0.32 45.075 ;
		RECT	0 45.275 0.32 45.705 ;
		RECT	0 46.105 0.32 46.555 ;
		RECT	0 46.955 0.32 47.385 ;
		RECT	0 47.585 0.32 47.915 ;
		RECT	0 48.115 0.32 48.545 ;
		RECT	0 48.945 0.32 49.395 ;
		RECT	0 49.795 0.32 50.225 ;
		RECT	0 50.425 0.32 50.755 ;
		RECT	0 50.955 0.32 51.385 ;
		RECT	0 51.785 0.32 52.235 ;
		RECT	0 52.635 0.32 53.065 ;
		RECT	0 53.265 0.32 53.595 ;
		RECT	0 53.795 0.32 54.225 ;
		RECT	0 54.625 0.32 55.075 ;
		RECT	0 55.475 0.32 55.905 ;
		RECT	0 56.105 0.32 56.435 ;
		RECT	0 56.635 0.32 57.065 ;
		RECT	0 57.465 0.32 57.915 ;
		RECT	0 58.315 0.32 58.745 ;
		RECT	0 58.945 0.32 59.275 ;
		RECT	0 59.475 0.32 59.905 ;
		RECT	0 60.305 0.32 60.755 ;
		RECT	0 61.155 0.32 61.585 ;
		RECT	0 61.785 0.32 62.115 ;
		RECT	0 62.315 0.32 62.745 ;
		RECT	0 63.145 0.32 63.595 ;
		RECT	0 63.995 0.32 64.425 ;
		RECT	0 64.625 0.32 64.955 ;
		RECT	0 65.155 0.32 65.585 ;
		RECT	0 65.985 0.32 66.435 ;
		RECT	0 66.835 0.32 67.265 ;
		RECT	0 67.465 0.32 67.795 ;
		RECT	0 67.995 0.32 68.425 ;
		RECT	0 68.825 0.32 69.275 ;
		RECT	0 69.675 0.32 70.105 ;
		RECT	0 70.305 0.32 70.635 ;
		RECT	0 70.835 0.32 71.265 ;
		RECT	0 71.665 0.32 72.115 ;
		RECT	0 72.515 0.32 72.945 ;
		RECT	0 73.145 0.32 73.475 ;
		RECT	0 73.675 0.32 74.105 ;
		RECT	0 74.505 0.32 74.955 ;
		RECT	0 75.355 0.32 75.785 ;
		RECT	0 75.985 0.32 76.315 ;
		RECT	0 76.515 0.32 76.945 ;
		RECT	0 77.345 0.32 77.795 ;
		RECT	0 78.195 0.32 78.625 ;
		RECT	0 78.825 0.32 79.155 ;
		RECT	0 79.355 0.32 79.785 ;
		RECT	0 80.185 0.32 80.635 ;
		RECT	0 81.035 0.32 81.465 ;
		RECT	0 81.665 0.32 81.995 ;
		RECT	0 82.195 0.32 82.625 ;
		RECT	0 83.025 0.32 83.475 ;
		RECT	0 83.875 0.32 84.305 ;
		RECT	0 84.505 0.32 84.835 ;
		RECT	0 85.035 0.32 85.465 ;
		RECT	0 85.865 0.32 86.315 ;
		RECT	0 86.715 0.32 87.145 ;
		RECT	0 87.345 0.32 87.675 ;
		RECT	0 87.875 0.32 88.305 ;
		RECT	0 88.705 0.32 89.155 ;
		RECT	0 89.555 0.32 89.985 ;
		RECT	0 90.185 0.32 90.515 ;
		RECT	0 90.715 0.32 91.145 ;
		RECT	0 91.545 0.32 94.015 ;
		RECT	0 94.215 0.32 96.46 ;
		RECT	0 96.66 0.32 96.85 ;
		RECT	0 97.05 0.32 97.975 ;
		RECT	0 98.175 0.32 99.645 ;
		RECT	0 100.04 0.32 100.44 ;
		RECT	0 100.64 0.32 100.84 ;
		RECT	0 101.04 0.32 102.75 ;
		RECT	0 102.95 0.32 103.08 ;
		RECT	0 103.28 0.32 105.185 ;
		RECT	0 105.385 0.32 105.655 ;
		RECT	0 106.255 0.32 106.455 ;
		RECT	0 106.655 0.32 112.335 ;
		RECT	0 112.535 0.32 112.71 ;
		RECT	0 112.91 0.32 114.48 ;
		RECT	0 114.88 0.32 115.31 ;
		RECT	0 115.51 0.32 115.84 ;
		RECT	0 116.04 0.32 116.47 ;
		RECT	0 116.87 0.32 117.32 ;
		RECT	0 117.72 0.32 118.15 ;
		RECT	0 118.35 0.32 118.68 ;
		RECT	0 118.88 0.32 119.31 ;
		RECT	0 119.71 0.32 120.16 ;
		RECT	0 120.56 0.32 120.99 ;
		RECT	0 121.19 0.32 121.52 ;
		RECT	0 121.72 0.32 122.15 ;
		RECT	0 122.55 0.32 123 ;
		RECT	0 123.4 0.32 123.83 ;
		RECT	0 124.03 0.32 124.36 ;
		RECT	0 124.56 0.32 124.99 ;
		RECT	0 125.39 0.32 125.84 ;
		RECT	0 126.24 0.32 126.67 ;
		RECT	0 126.87 0.32 127.2 ;
		RECT	0 127.4 0.32 127.83 ;
		RECT	0 128.23 0.32 128.68 ;
		RECT	0 129.08 0.32 129.51 ;
		RECT	0 129.71 0.32 130.04 ;
		RECT	0 130.24 0.32 130.67 ;
		RECT	0 131.07 0.32 131.52 ;
		RECT	0 131.92 0.32 132.35 ;
		RECT	0 132.55 0.32 132.88 ;
		RECT	0 133.08 0.32 133.51 ;
		RECT	0 133.91 0.32 134.36 ;
		RECT	0 134.76 0.32 135.19 ;
		RECT	0 135.39 0.32 135.72 ;
		RECT	0 135.92 0.32 136.35 ;
		RECT	0 136.75 0.32 137.2 ;
		RECT	0 137.6 0.32 138.03 ;
		RECT	0 138.23 0.32 138.56 ;
		RECT	0 138.76 0.32 139.19 ;
		RECT	0 139.59 0.32 140.04 ;
		RECT	0 140.44 0.32 140.87 ;
		RECT	0 141.07 0.32 141.4 ;
		RECT	0 141.6 0.32 142.03 ;
		RECT	0 142.43 0.32 142.88 ;
		RECT	0 143.28 0.32 143.71 ;
		RECT	0 143.91 0.32 144.24 ;
		RECT	0 144.44 0.32 144.87 ;
		RECT	0 145.27 0.32 145.72 ;
		RECT	0 146.12 0.32 146.55 ;
		RECT	0 146.75 0.32 147.08 ;
		RECT	0 147.28 0.32 147.71 ;
		RECT	0 148.11 0.32 148.56 ;
		RECT	0 148.96 0.32 149.39 ;
		RECT	0 149.59 0.32 149.92 ;
		RECT	0 150.12 0.32 150.55 ;
		RECT	0 150.95 0.32 151.4 ;
		RECT	0 151.8 0.32 152.23 ;
		RECT	0 152.43 0.32 152.76 ;
		RECT	0 152.96 0.32 153.39 ;
		RECT	0 153.79 0.32 154.24 ;
		RECT	0 154.64 0.32 155.07 ;
		RECT	0 155.27 0.32 155.6 ;
		RECT	0 155.8 0.32 156.23 ;
		RECT	0 156.63 0.32 157.08 ;
		RECT	0 157.48 0.32 157.91 ;
		RECT	0 158.11 0.32 158.44 ;
		RECT	0 158.64 0.32 159.07 ;
		RECT	0 159.47 0.32 159.92 ;
		RECT	0 160.32 0.32 160.75 ;
		RECT	0 160.95 0.32 161.28 ;
		RECT	0 161.48 0.32 161.91 ;
		RECT	0 162.31 0.32 162.76 ;
		RECT	0 163.16 0.32 163.59 ;
		RECT	0 163.79 0.32 164.12 ;
		RECT	0 164.32 0.32 164.75 ;
		RECT	0 165.15 0.32 165.6 ;
		RECT	0 166 0.32 166.43 ;
		RECT	0 166.63 0.32 166.96 ;
		RECT	0 167.16 0.32 167.59 ;
		RECT	0 167.99 0.32 168.44 ;
		RECT	0 168.84 0.32 169.27 ;
		RECT	0 169.47 0.32 169.8 ;
		RECT	0 170 0.32 170.43 ;
		RECT	0 170.83 0.32 171.28 ;
		RECT	0 171.68 0.32 172.11 ;
		RECT	0 172.31 0.32 172.64 ;
		RECT	0 172.84 0.32 173.27 ;
		RECT	0 173.67 0.32 174.12 ;
		RECT	0 174.52 0.32 174.95 ;
		RECT	0 175.15 0.32 175.48 ;
		RECT	0 175.68 0.32 176.11 ;
		RECT	0 176.51 0.32 176.96 ;
		RECT	0 177.36 0.32 177.79 ;
		RECT	0 177.99 0.32 178.32 ;
		RECT	0 178.52 0.32 178.95 ;
		RECT	0 179.35 0.32 179.8 ;
		RECT	0 180.2 0.32 180.63 ;
		RECT	0 180.83 0.32 181.16 ;
		RECT	0 181.36 0.32 181.79 ;
		RECT	0 182.19 0.32 182.64 ;
		RECT	0 183.04 0.32 183.47 ;
		RECT	0 183.67 0.32 184 ;
		RECT	0 184.2 0.32 184.63 ;
		RECT	0 185.03 0.32 185.48 ;
		RECT	0 185.88 0.32 186.31 ;
		RECT	0 186.51 0.32 186.84 ;
		RECT	0 187.04 0.32 187.47 ;
		RECT	0 187.87 0.32 188.32 ;
		RECT	0 188.72 0.32 189.15 ;
		RECT	0 189.35 0.32 189.68 ;
		RECT	0 189.88 0.32 190.31 ;
		RECT	0 190.71 0.32 191.16 ;
		RECT	0 191.56 0.32 191.99 ;
		RECT	0 192.19 0.32 192.52 ;
		RECT	0 192.72 0.32 193.15 ;
		RECT	0 193.55 0.32 194 ;
		RECT	0 194.4 0.32 194.83 ;
		RECT	0 195.03 0.32 195.36 ;
		RECT	0 195.56 0.32 195.99 ;
		RECT	0 196.39 0.32 196.84 ;
		RECT	0 197.24 0.32 197.67 ;
		RECT	0 197.87 0.32 198.2 ;
		RECT	0 198.4 0.32 198.83 ;
		RECT	0 199.23 0.32 199.68 ;
		RECT	0 200.08 0.32 200.51 ;
		RECT	0 200.71 0.32 201.04 ;
		RECT	0 201.24 0.32 201.67 ;
		RECT	0 202.07 0.32 202.52 ;
		RECT	0 202.92 0.32 203.35 ;
		RECT	0 203.55 0.32 203.88 ;
		RECT	0 204.08 0.32 204.51 ;
		RECT	0 204.91 0.32 206.025 ;
		RECT	34.64 0 34.96 206.025 ;
		RECT	0.32 0 34.64 0.3 ;
		RECT	0.32 205.725 34.64 206.025 ;
		LAYER	M4 DESIGNRULEWIDTH 0.165 ;
		RECT	0.32 0 34.64 0.09 ;
		RECT	0 0 0.32 0.09 ;
		RECT	34.64 0 34.96 0.09 ;
		RECT	0.32 0.9 34.64 1.48 ;
		RECT	0 0.9 0.32 1.48 ;
		RECT	34.64 0.9 34.96 1.48 ;
		RECT	0.32 2.2 34.64 2.37 ;
		RECT	0 2.2 0.32 2.37 ;
		RECT	34.64 2.2 34.96 2.37 ;
		RECT	0.32 2.78 34.64 2.83 ;
		RECT	0 2.78 0.32 2.83 ;
		RECT	34.64 2.78 34.96 2.83 ;
		RECT	0.32 3.63 34.64 4.32 ;
		RECT	0 3.63 0.32 4.32 ;
		RECT	34.64 3.63 34.96 4.32 ;
		RECT	0.32 5.04 34.64 5.21 ;
		RECT	0 5.04 0.32 5.21 ;
		RECT	34.64 5.04 34.96 5.21 ;
		RECT	0.32 5.62 34.64 5.67 ;
		RECT	0 5.62 0.32 5.67 ;
		RECT	34.64 5.62 34.96 5.67 ;
		RECT	0.32 6.47 34.64 7.16 ;
		RECT	0 6.47 0.32 7.16 ;
		RECT	34.64 6.47 34.96 7.16 ;
		RECT	0.32 7.88 34.64 8.05 ;
		RECT	0 7.88 0.32 8.05 ;
		RECT	34.64 7.88 34.96 8.05 ;
		RECT	0.32 8.46 34.64 8.51 ;
		RECT	0 8.46 0.32 8.51 ;
		RECT	34.64 8.46 34.96 8.51 ;
		RECT	0.32 9.31 34.64 10 ;
		RECT	0 9.31 0.32 10 ;
		RECT	34.64 9.31 34.96 10 ;
		RECT	0.32 10.72 34.64 10.89 ;
		RECT	0 10.72 0.32 10.89 ;
		RECT	34.64 10.72 34.96 10.89 ;
		RECT	0.32 11.3 34.64 11.35 ;
		RECT	0 11.3 0.32 11.35 ;
		RECT	34.64 11.3 34.96 11.35 ;
		RECT	0.32 12.15 34.64 12.84 ;
		RECT	0 12.15 0.32 12.84 ;
		RECT	34.64 12.15 34.96 12.84 ;
		RECT	0.32 13.56 34.64 13.73 ;
		RECT	0 13.56 0.32 13.73 ;
		RECT	34.64 13.56 34.96 13.73 ;
		RECT	0.32 14.14 34.64 14.19 ;
		RECT	0 14.14 0.32 14.19 ;
		RECT	34.64 14.14 34.96 14.19 ;
		RECT	0.32 14.99 34.64 15.68 ;
		RECT	0 14.99 0.32 15.68 ;
		RECT	34.64 14.99 34.96 15.68 ;
		RECT	0.32 16.4 34.64 16.57 ;
		RECT	0 16.4 0.32 16.57 ;
		RECT	34.64 16.4 34.96 16.57 ;
		RECT	0.32 16.98 34.64 17.03 ;
		RECT	0 16.98 0.32 17.03 ;
		RECT	34.64 16.98 34.96 17.03 ;
		RECT	0.32 17.83 34.64 18.52 ;
		RECT	0 17.83 0.32 18.52 ;
		RECT	34.64 17.83 34.96 18.52 ;
		RECT	0.32 19.24 34.64 19.41 ;
		RECT	0 19.24 0.32 19.41 ;
		RECT	34.64 19.24 34.96 19.41 ;
		RECT	0.32 19.82 34.64 19.87 ;
		RECT	0 19.82 0.32 19.87 ;
		RECT	34.64 19.82 34.96 19.87 ;
		RECT	0.32 20.67 34.64 21.36 ;
		RECT	0 20.67 0.32 21.36 ;
		RECT	34.64 20.67 34.96 21.36 ;
		RECT	0.32 22.08 34.64 22.25 ;
		RECT	0 22.08 0.32 22.25 ;
		RECT	34.64 22.08 34.96 22.25 ;
		RECT	0.32 22.66 34.64 22.71 ;
		RECT	0 22.66 0.32 22.71 ;
		RECT	34.64 22.66 34.96 22.71 ;
		RECT	0.32 23.51 34.64 24.2 ;
		RECT	0 23.51 0.32 24.2 ;
		RECT	34.64 23.51 34.96 24.2 ;
		RECT	0.32 24.92 34.64 25.09 ;
		RECT	0 24.92 0.32 25.09 ;
		RECT	34.64 24.92 34.96 25.09 ;
		RECT	0.32 25.5 34.64 25.55 ;
		RECT	0 25.5 0.32 25.55 ;
		RECT	34.64 25.5 34.96 25.55 ;
		RECT	0.32 26.35 34.64 27.04 ;
		RECT	0 26.35 0.32 27.04 ;
		RECT	34.64 26.35 34.96 27.04 ;
		RECT	0.32 27.76 34.64 27.93 ;
		RECT	0 27.76 0.32 27.93 ;
		RECT	34.64 27.76 34.96 27.93 ;
		RECT	0.32 28.34 34.64 28.39 ;
		RECT	0 28.34 0.32 28.39 ;
		RECT	34.64 28.34 34.96 28.39 ;
		RECT	0.32 29.19 34.64 29.88 ;
		RECT	0 29.19 0.32 29.88 ;
		RECT	34.64 29.19 34.96 29.88 ;
		RECT	0.32 30.6 34.64 30.77 ;
		RECT	0 30.6 0.32 30.77 ;
		RECT	34.64 30.6 34.96 30.77 ;
		RECT	0.32 31.18 34.64 31.23 ;
		RECT	0 31.18 0.32 31.23 ;
		RECT	34.64 31.18 34.96 31.23 ;
		RECT	0.32 32.03 34.64 32.72 ;
		RECT	0 32.03 0.32 32.72 ;
		RECT	34.64 32.03 34.96 32.72 ;
		RECT	0.32 33.44 34.64 33.61 ;
		RECT	0 33.44 0.32 33.61 ;
		RECT	34.64 33.44 34.96 33.61 ;
		RECT	0.32 34.02 34.64 34.07 ;
		RECT	0 34.02 0.32 34.07 ;
		RECT	34.64 34.02 34.96 34.07 ;
		RECT	0.32 34.87 34.64 35.56 ;
		RECT	0 34.87 0.32 35.56 ;
		RECT	34.64 34.87 34.96 35.56 ;
		RECT	0.32 36.28 34.64 36.45 ;
		RECT	0 36.28 0.32 36.45 ;
		RECT	34.64 36.28 34.96 36.45 ;
		RECT	0.32 36.86 34.64 36.91 ;
		RECT	0 36.86 0.32 36.91 ;
		RECT	34.64 36.86 34.96 36.91 ;
		RECT	0.32 37.71 34.64 38.4 ;
		RECT	0 37.71 0.32 38.4 ;
		RECT	34.64 37.71 34.96 38.4 ;
		RECT	0.32 39.12 34.64 39.29 ;
		RECT	0 39.12 0.32 39.29 ;
		RECT	34.64 39.12 34.96 39.29 ;
		RECT	0.32 39.7 34.64 39.75 ;
		RECT	0 39.7 0.32 39.75 ;
		RECT	34.64 39.7 34.96 39.75 ;
		RECT	0.32 40.55 34.64 41.24 ;
		RECT	0 40.55 0.32 41.24 ;
		RECT	34.64 40.55 34.96 41.24 ;
		RECT	0.32 41.96 34.64 42.13 ;
		RECT	0 41.96 0.32 42.13 ;
		RECT	34.64 41.96 34.96 42.13 ;
		RECT	0.32 42.54 34.64 42.59 ;
		RECT	0 42.54 0.32 42.59 ;
		RECT	34.64 42.54 34.96 42.59 ;
		RECT	0.32 43.39 34.64 44.08 ;
		RECT	0 43.39 0.32 44.08 ;
		RECT	34.64 43.39 34.96 44.08 ;
		RECT	0.32 44.8 34.64 44.97 ;
		RECT	0 44.8 0.32 44.97 ;
		RECT	34.64 44.8 34.96 44.97 ;
		RECT	0.32 45.38 34.64 45.43 ;
		RECT	0 45.38 0.32 45.43 ;
		RECT	34.64 45.38 34.96 45.43 ;
		RECT	0.32 46.23 34.64 46.92 ;
		RECT	0 46.23 0.32 46.92 ;
		RECT	34.64 46.23 34.96 46.92 ;
		RECT	0.32 47.64 34.64 47.81 ;
		RECT	0 47.64 0.32 47.81 ;
		RECT	34.64 47.64 34.96 47.81 ;
		RECT	0.32 48.22 34.64 48.27 ;
		RECT	0 48.22 0.32 48.27 ;
		RECT	34.64 48.22 34.96 48.27 ;
		RECT	0.32 49.07 34.64 49.76 ;
		RECT	0 49.07 0.32 49.76 ;
		RECT	34.64 49.07 34.96 49.76 ;
		RECT	0.32 50.48 34.64 50.65 ;
		RECT	0 50.48 0.32 50.65 ;
		RECT	34.64 50.48 34.96 50.65 ;
		RECT	0.32 51.06 34.64 51.11 ;
		RECT	0 51.06 0.32 51.11 ;
		RECT	34.64 51.06 34.96 51.11 ;
		RECT	0.32 51.91 34.64 52.6 ;
		RECT	0 51.91 0.32 52.6 ;
		RECT	34.64 51.91 34.96 52.6 ;
		RECT	0.32 53.32 34.64 53.49 ;
		RECT	0 53.32 0.32 53.49 ;
		RECT	34.64 53.32 34.96 53.49 ;
		RECT	0.32 53.9 34.64 53.95 ;
		RECT	0 53.9 0.32 53.95 ;
		RECT	34.64 53.9 34.96 53.95 ;
		RECT	0.32 54.75 34.64 55.44 ;
		RECT	0 54.75 0.32 55.44 ;
		RECT	34.64 54.75 34.96 55.44 ;
		RECT	0.32 56.16 34.64 56.33 ;
		RECT	0 56.16 0.32 56.33 ;
		RECT	34.64 56.16 34.96 56.33 ;
		RECT	0.32 56.74 34.64 56.79 ;
		RECT	0 56.74 0.32 56.79 ;
		RECT	34.64 56.74 34.96 56.79 ;
		RECT	0.32 57.59 34.64 58.28 ;
		RECT	0 57.59 0.32 58.28 ;
		RECT	34.64 57.59 34.96 58.28 ;
		RECT	0.32 59 34.64 59.17 ;
		RECT	0 59 0.32 59.17 ;
		RECT	34.64 59 34.96 59.17 ;
		RECT	0.32 59.58 34.64 59.63 ;
		RECT	0 59.58 0.32 59.63 ;
		RECT	34.64 59.58 34.96 59.63 ;
		RECT	0.32 60.43 34.64 61.12 ;
		RECT	0 60.43 0.32 61.12 ;
		RECT	34.64 60.43 34.96 61.12 ;
		RECT	0.32 61.84 34.64 62.01 ;
		RECT	0 61.84 0.32 62.01 ;
		RECT	34.64 61.84 34.96 62.01 ;
		RECT	0.32 62.42 34.64 62.47 ;
		RECT	0 62.42 0.32 62.47 ;
		RECT	34.64 62.42 34.96 62.47 ;
		RECT	0.32 63.27 34.64 63.96 ;
		RECT	0 63.27 0.32 63.96 ;
		RECT	34.64 63.27 34.96 63.96 ;
		RECT	0.32 64.68 34.64 64.85 ;
		RECT	0 64.68 0.32 64.85 ;
		RECT	34.64 64.68 34.96 64.85 ;
		RECT	0.32 65.26 34.64 65.31 ;
		RECT	0 65.26 0.32 65.31 ;
		RECT	34.64 65.26 34.96 65.31 ;
		RECT	0.32 66.11 34.64 66.8 ;
		RECT	0 66.11 0.32 66.8 ;
		RECT	34.64 66.11 34.96 66.8 ;
		RECT	0.32 67.52 34.64 67.69 ;
		RECT	0 67.52 0.32 67.69 ;
		RECT	34.64 67.52 34.96 67.69 ;
		RECT	0.32 68.1 34.64 68.15 ;
		RECT	0 68.1 0.32 68.15 ;
		RECT	34.64 68.1 34.96 68.15 ;
		RECT	0.32 68.95 34.64 69.64 ;
		RECT	0 68.95 0.32 69.64 ;
		RECT	34.64 68.95 34.96 69.64 ;
		RECT	0.32 70.36 34.64 70.53 ;
		RECT	0 70.36 0.32 70.53 ;
		RECT	34.64 70.36 34.96 70.53 ;
		RECT	0.32 70.94 34.64 70.99 ;
		RECT	0 70.94 0.32 70.99 ;
		RECT	34.64 70.94 34.96 70.99 ;
		RECT	0.32 71.79 34.64 72.48 ;
		RECT	0 71.79 0.32 72.48 ;
		RECT	34.64 71.79 34.96 72.48 ;
		RECT	0.32 73.2 34.64 73.37 ;
		RECT	0 73.2 0.32 73.37 ;
		RECT	34.64 73.2 34.96 73.37 ;
		RECT	0.32 73.78 34.64 73.83 ;
		RECT	0 73.78 0.32 73.83 ;
		RECT	34.64 73.78 34.96 73.83 ;
		RECT	0.32 74.63 34.64 75.32 ;
		RECT	0 74.63 0.32 75.32 ;
		RECT	34.64 74.63 34.96 75.32 ;
		RECT	0.32 76.04 34.64 76.21 ;
		RECT	0 76.04 0.32 76.21 ;
		RECT	34.64 76.04 34.96 76.21 ;
		RECT	0.32 76.62 34.64 76.67 ;
		RECT	0 76.62 0.32 76.67 ;
		RECT	34.64 76.62 34.96 76.67 ;
		RECT	0.32 77.47 34.64 78.16 ;
		RECT	0 77.47 0.32 78.16 ;
		RECT	34.64 77.47 34.96 78.16 ;
		RECT	0.32 78.88 34.64 79.05 ;
		RECT	0 78.88 0.32 79.05 ;
		RECT	34.64 78.88 34.96 79.05 ;
		RECT	0.32 79.46 34.64 79.51 ;
		RECT	0 79.46 0.32 79.51 ;
		RECT	34.64 79.46 34.96 79.51 ;
		RECT	0.32 80.31 34.64 81 ;
		RECT	0 80.31 0.32 81 ;
		RECT	34.64 80.31 34.96 81 ;
		RECT	0.32 81.72 34.64 81.89 ;
		RECT	0 81.72 0.32 81.89 ;
		RECT	34.64 81.72 34.96 81.89 ;
		RECT	0.32 82.3 34.64 82.35 ;
		RECT	0 82.3 0.32 82.35 ;
		RECT	34.64 82.3 34.96 82.35 ;
		RECT	0.32 83.15 34.64 83.84 ;
		RECT	0 83.15 0.32 83.84 ;
		RECT	34.64 83.15 34.96 83.84 ;
		RECT	0.32 84.56 34.64 84.73 ;
		RECT	0 84.56 0.32 84.73 ;
		RECT	34.64 84.56 34.96 84.73 ;
		RECT	0.32 85.14 34.64 85.19 ;
		RECT	0 85.14 0.32 85.19 ;
		RECT	34.64 85.14 34.96 85.19 ;
		RECT	0.32 85.99 34.64 86.68 ;
		RECT	0 85.99 0.32 86.68 ;
		RECT	34.64 85.99 34.96 86.68 ;
		RECT	0.32 87.4 34.64 87.57 ;
		RECT	0 87.4 0.32 87.57 ;
		RECT	34.64 87.4 34.96 87.57 ;
		RECT	0.32 87.98 34.64 88.03 ;
		RECT	0 87.98 0.32 88.03 ;
		RECT	34.64 87.98 34.96 88.03 ;
		RECT	0.32 88.83 34.64 89.52 ;
		RECT	0 88.83 0.32 89.52 ;
		RECT	34.64 88.83 34.96 89.52 ;
		RECT	0.32 90.24 34.64 90.41 ;
		RECT	0 90.24 0.32 90.41 ;
		RECT	34.64 90.24 34.96 90.41 ;
		RECT	0.32 90.82 34.64 90.87 ;
		RECT	0 90.82 0.32 90.87 ;
		RECT	34.64 90.82 34.96 90.87 ;
		RECT	0.32 91.67 34.64 92.185 ;
		RECT	0 91.67 0.32 92.185 ;
		RECT	34.64 91.67 34.96 92.185 ;
		RECT	0.32 92.835 34.64 92.93 ;
		RECT	0 92.835 0.32 92.93 ;
		RECT	34.64 92.835 34.96 92.93 ;
		RECT	0.32 93.16 34.64 93.29 ;
		RECT	0 93.16 0.32 93.29 ;
		RECT	34.64 93.16 34.96 93.29 ;
		RECT	0.32 93.7 34.64 94.175 ;
		RECT	0 93.7 0.32 94.175 ;
		RECT	34.64 93.7 34.96 94.175 ;
		RECT	0.32 95.28 34.64 95.615 ;
		RECT	0 95.28 0.32 95.615 ;
		RECT	34.64 95.28 34.96 95.615 ;
		RECT	0.32 96.275 34.64 96.68 ;
		RECT	0 96.275 0.32 96.46 ;
		RECT	34.64 96.275 34.96 96.68 ;
		RECT	0.32 96.99 34.64 97.075 ;
		RECT	0 96.99 0.32 97.075 ;
		RECT	34.64 96.99 34.96 97.075 ;
		RECT	0.32 97.305 34.64 97.785 ;
		RECT	0 97.305 0.32 97.785 ;
		RECT	34.64 97.305 34.96 97.785 ;
		RECT	0.32 98.46 34.64 98.525 ;
		RECT	0 98.46 0.32 98.525 ;
		RECT	34.64 98.46 34.96 98.525 ;
		RECT	0.32 98.935 34.64 99.375 ;
		RECT	0 98.935 0.32 99.375 ;
		RECT	34.64 98.935 34.96 99.375 ;
		RECT	0.32 99.605 34.64 99.94 ;
		RECT	0 99.605 0.32 99.94 ;
		RECT	34.64 99.605 34.96 99.94 ;
		RECT	0.32 100.35 34.64 100.495 ;
		RECT	0 100.35 0.32 100.495 ;
		RECT	34.64 100.35 34.96 100.495 ;
		RECT	0.32 101.415 34.64 102.53 ;
		RECT	0 101.415 0.32 102.53 ;
		RECT	34.64 101.415 34.96 102.53 ;
		RECT	0.32 102.94 34.64 103.5 ;
		RECT	0 102.94 0.32 103.5 ;
		RECT	34.64 102.94 34.96 103.5 ;
		RECT	0.32 103.91 34.64 105.06 ;
		RECT	0 103.91 0.32 105.06 ;
		RECT	34.64 103.91 34.96 105.06 ;
		RECT	0.32 105.68 34.64 105.92 ;
		RECT	0 105.68 0.32 105.92 ;
		RECT	34.64 105.68 34.96 105.92 ;
		RECT	0.32 106.33 34.64 106.64 ;
		RECT	0 106.33 0.32 106.64 ;
		RECT	34.64 106.33 34.96 106.64 ;
		RECT	0.32 106.87 34.64 106.95 ;
		RECT	0 106.87 0.32 106.95 ;
		RECT	34.64 106.87 34.96 106.95 ;
		RECT	0.32 107.36 34.64 107.715 ;
		RECT	0 107.36 0.32 107.715 ;
		RECT	34.64 107.36 34.96 107.715 ;
		RECT	0.32 108.375 34.64 108.555 ;
		RECT	0 108.375 0.32 108.555 ;
		RECT	34.64 108.375 34.96 108.555 ;
		RECT	0.32 108.965 34.64 109.03 ;
		RECT	0 108.965 0.32 109.03 ;
		RECT	34.64 108.965 34.96 109.03 ;
		RECT	0.32 109.44 34.64 109.595 ;
		RECT	0 109.44 0.32 109.595 ;
		RECT	34.64 109.44 34.96 109.595 ;
		RECT	0.32 109.905 34.64 110.295 ;
		RECT	0 109.905 0.32 110.295 ;
		RECT	34.64 109.905 34.96 110.295 ;
		RECT	0.32 110.705 34.64 110.835 ;
		RECT	0 110.705 0.32 110.835 ;
		RECT	34.64 110.705 34.96 110.835 ;
		RECT	0.32 111.065 34.64 111.49 ;
		RECT	0 111.065 0.32 111.49 ;
		RECT	34.64 111.065 34.96 111.49 ;
		RECT	0.32 111.9 34.64 112.01 ;
		RECT	0 111.9 0.32 112.01 ;
		RECT	34.64 111.9 34.96 112.01 ;
		RECT	0.32 112.795 34.64 112.855 ;
		RECT	0 112.795 0.32 112.855 ;
		RECT	34.64 112.795 34.96 112.855 ;
		RECT	0.32 113.51 34.64 113.6 ;
		RECT	0 113.51 0.32 113.6 ;
		RECT	34.64 113.51 34.96 113.6 ;
		RECT	0.32 114.25 34.64 114.355 ;
		RECT	0 114.25 0.32 114.355 ;
		RECT	34.64 114.25 34.96 114.355 ;
		RECT	0.32 115.155 34.64 115.205 ;
		RECT	0 115.155 0.32 115.205 ;
		RECT	34.64 115.155 34.96 115.205 ;
		RECT	0.32 115.615 34.64 115.785 ;
		RECT	0 115.615 0.32 115.785 ;
		RECT	34.64 115.615 34.96 115.785 ;
		RECT	0.32 116.505 34.64 117.195 ;
		RECT	0 116.505 0.32 117.195 ;
		RECT	34.64 116.505 34.96 117.195 ;
		RECT	0.32 117.995 34.64 118.045 ;
		RECT	0 117.995 0.32 118.045 ;
		RECT	34.64 117.995 34.96 118.045 ;
		RECT	0.32 118.455 34.64 118.625 ;
		RECT	0 118.455 0.32 118.625 ;
		RECT	34.64 118.455 34.96 118.625 ;
		RECT	0.32 119.345 34.64 120.035 ;
		RECT	0 119.345 0.32 120.035 ;
		RECT	34.64 119.345 34.96 120.035 ;
		RECT	0.32 120.835 34.64 120.885 ;
		RECT	0 120.835 0.32 120.885 ;
		RECT	34.64 120.835 34.96 120.885 ;
		RECT	0.32 121.295 34.64 121.465 ;
		RECT	0 121.295 0.32 121.465 ;
		RECT	34.64 121.295 34.96 121.465 ;
		RECT	0.32 122.185 34.64 122.875 ;
		RECT	0 122.185 0.32 122.875 ;
		RECT	34.64 122.185 34.96 122.875 ;
		RECT	0.32 123.675 34.64 123.725 ;
		RECT	0 123.675 0.32 123.725 ;
		RECT	34.64 123.675 34.96 123.725 ;
		RECT	0.32 124.135 34.64 124.305 ;
		RECT	0 124.135 0.32 124.305 ;
		RECT	34.64 124.135 34.96 124.305 ;
		RECT	0.32 125.025 34.64 125.715 ;
		RECT	0 125.025 0.32 125.715 ;
		RECT	34.64 125.025 34.96 125.715 ;
		RECT	0.32 126.515 34.64 126.565 ;
		RECT	0 126.515 0.32 126.565 ;
		RECT	34.64 126.515 34.96 126.565 ;
		RECT	0.32 126.975 34.64 127.145 ;
		RECT	0 126.975 0.32 127.145 ;
		RECT	34.64 126.975 34.96 127.145 ;
		RECT	0.32 127.865 34.64 128.555 ;
		RECT	0 127.865 0.32 128.555 ;
		RECT	34.64 127.865 34.96 128.555 ;
		RECT	0.32 129.355 34.64 129.405 ;
		RECT	0 129.355 0.32 129.405 ;
		RECT	34.64 129.355 34.96 129.405 ;
		RECT	0.32 129.815 34.64 129.985 ;
		RECT	0 129.815 0.32 129.985 ;
		RECT	34.64 129.815 34.96 129.985 ;
		RECT	0.32 130.705 34.64 131.395 ;
		RECT	0 130.705 0.32 131.395 ;
		RECT	34.64 130.705 34.96 131.395 ;
		RECT	0.32 132.195 34.64 132.245 ;
		RECT	0 132.195 0.32 132.245 ;
		RECT	34.64 132.195 34.96 132.245 ;
		RECT	0.32 132.655 34.64 132.825 ;
		RECT	0 132.655 0.32 132.825 ;
		RECT	34.64 132.655 34.96 132.825 ;
		RECT	0.32 133.545 34.64 134.235 ;
		RECT	0 133.545 0.32 134.235 ;
		RECT	34.64 133.545 34.96 134.235 ;
		RECT	0.32 135.035 34.64 135.085 ;
		RECT	0 135.035 0.32 135.085 ;
		RECT	34.64 135.035 34.96 135.085 ;
		RECT	0.32 135.495 34.64 135.665 ;
		RECT	0 135.495 0.32 135.665 ;
		RECT	34.64 135.495 34.96 135.665 ;
		RECT	0.32 136.385 34.64 137.075 ;
		RECT	0 136.385 0.32 137.075 ;
		RECT	34.64 136.385 34.96 137.075 ;
		RECT	0.32 137.875 34.64 137.925 ;
		RECT	0 137.875 0.32 137.925 ;
		RECT	34.64 137.875 34.96 137.925 ;
		RECT	0.32 138.335 34.64 138.505 ;
		RECT	0 138.335 0.32 138.505 ;
		RECT	34.64 138.335 34.96 138.505 ;
		RECT	0.32 139.225 34.64 139.915 ;
		RECT	0 139.225 0.32 139.915 ;
		RECT	34.64 139.225 34.96 139.915 ;
		RECT	0.32 140.715 34.64 140.765 ;
		RECT	0 140.715 0.32 140.765 ;
		RECT	34.64 140.715 34.96 140.765 ;
		RECT	0.32 141.175 34.64 141.345 ;
		RECT	0 141.175 0.32 141.345 ;
		RECT	34.64 141.175 34.96 141.345 ;
		RECT	0.32 142.065 34.64 142.755 ;
		RECT	0 142.065 0.32 142.755 ;
		RECT	34.64 142.065 34.96 142.755 ;
		RECT	0.32 143.555 34.64 143.605 ;
		RECT	0 143.555 0.32 143.605 ;
		RECT	34.64 143.555 34.96 143.605 ;
		RECT	0.32 144.015 34.64 144.185 ;
		RECT	0 144.015 0.32 144.185 ;
		RECT	34.64 144.015 34.96 144.185 ;
		RECT	0.32 144.905 34.64 145.595 ;
		RECT	0 144.905 0.32 145.595 ;
		RECT	34.64 144.905 34.96 145.595 ;
		RECT	0.32 146.395 34.64 146.445 ;
		RECT	0 146.395 0.32 146.445 ;
		RECT	34.64 146.395 34.96 146.445 ;
		RECT	0.32 146.855 34.64 147.025 ;
		RECT	0 146.855 0.32 147.025 ;
		RECT	34.64 146.855 34.96 147.025 ;
		RECT	0.32 147.745 34.64 148.435 ;
		RECT	0 147.745 0.32 148.435 ;
		RECT	34.64 147.745 34.96 148.435 ;
		RECT	0.32 149.235 34.64 149.285 ;
		RECT	0 149.235 0.32 149.285 ;
		RECT	34.64 149.235 34.96 149.285 ;
		RECT	0.32 149.695 34.64 149.865 ;
		RECT	0 149.695 0.32 149.865 ;
		RECT	34.64 149.695 34.96 149.865 ;
		RECT	0.32 150.585 34.64 151.275 ;
		RECT	0 150.585 0.32 151.275 ;
		RECT	34.64 150.585 34.96 151.275 ;
		RECT	0.32 152.075 34.64 152.125 ;
		RECT	0 152.075 0.32 152.125 ;
		RECT	34.64 152.075 34.96 152.125 ;
		RECT	0.32 152.535 34.64 152.705 ;
		RECT	0 152.535 0.32 152.705 ;
		RECT	34.64 152.535 34.96 152.705 ;
		RECT	0.32 153.425 34.64 154.115 ;
		RECT	0 153.425 0.32 154.115 ;
		RECT	34.64 153.425 34.96 154.115 ;
		RECT	0.32 154.915 34.64 154.965 ;
		RECT	0 154.915 0.32 154.965 ;
		RECT	34.64 154.915 34.96 154.965 ;
		RECT	0.32 155.375 34.64 155.545 ;
		RECT	0 155.375 0.32 155.545 ;
		RECT	34.64 155.375 34.96 155.545 ;
		RECT	0.32 156.265 34.64 156.955 ;
		RECT	0 156.265 0.32 156.955 ;
		RECT	34.64 156.265 34.96 156.955 ;
		RECT	0.32 157.755 34.64 157.805 ;
		RECT	0 157.755 0.32 157.805 ;
		RECT	34.64 157.755 34.96 157.805 ;
		RECT	0.32 158.215 34.64 158.385 ;
		RECT	0 158.215 0.32 158.385 ;
		RECT	34.64 158.215 34.96 158.385 ;
		RECT	0.32 159.105 34.64 159.795 ;
		RECT	0 159.105 0.32 159.795 ;
		RECT	34.64 159.105 34.96 159.795 ;
		RECT	0.32 160.595 34.64 160.645 ;
		RECT	0 160.595 0.32 160.645 ;
		RECT	34.64 160.595 34.96 160.645 ;
		RECT	0.32 161.055 34.64 161.225 ;
		RECT	0 161.055 0.32 161.225 ;
		RECT	34.64 161.055 34.96 161.225 ;
		RECT	0.32 161.945 34.64 162.635 ;
		RECT	0 161.945 0.32 162.635 ;
		RECT	34.64 161.945 34.96 162.635 ;
		RECT	0.32 163.435 34.64 163.485 ;
		RECT	0 163.435 0.32 163.485 ;
		RECT	34.64 163.435 34.96 163.485 ;
		RECT	0.32 163.895 34.64 164.065 ;
		RECT	0 163.895 0.32 164.065 ;
		RECT	34.64 163.895 34.96 164.065 ;
		RECT	0.32 164.785 34.64 165.475 ;
		RECT	0 164.785 0.32 165.475 ;
		RECT	34.64 164.785 34.96 165.475 ;
		RECT	0.32 166.275 34.64 166.325 ;
		RECT	0 166.275 0.32 166.325 ;
		RECT	34.64 166.275 34.96 166.325 ;
		RECT	0.32 166.735 34.64 166.905 ;
		RECT	0 166.735 0.32 166.905 ;
		RECT	34.64 166.735 34.96 166.905 ;
		RECT	0.32 167.625 34.64 168.315 ;
		RECT	0 167.625 0.32 168.315 ;
		RECT	34.64 167.625 34.96 168.315 ;
		RECT	0.32 169.115 34.64 169.165 ;
		RECT	0 169.115 0.32 169.165 ;
		RECT	34.64 169.115 34.96 169.165 ;
		RECT	0.32 169.575 34.64 169.745 ;
		RECT	0 169.575 0.32 169.745 ;
		RECT	34.64 169.575 34.96 169.745 ;
		RECT	0.32 170.465 34.64 171.155 ;
		RECT	0 170.465 0.32 171.155 ;
		RECT	34.64 170.465 34.96 171.155 ;
		RECT	0.32 171.955 34.64 172.005 ;
		RECT	0 171.955 0.32 172.005 ;
		RECT	34.64 171.955 34.96 172.005 ;
		RECT	0.32 172.415 34.64 172.585 ;
		RECT	0 172.415 0.32 172.585 ;
		RECT	34.64 172.415 34.96 172.585 ;
		RECT	0.32 173.305 34.64 173.995 ;
		RECT	0 173.305 0.32 173.995 ;
		RECT	34.64 173.305 34.96 173.995 ;
		RECT	0.32 174.795 34.64 174.845 ;
		RECT	0 174.795 0.32 174.845 ;
		RECT	34.64 174.795 34.96 174.845 ;
		RECT	0.32 175.255 34.64 175.425 ;
		RECT	0 175.255 0.32 175.425 ;
		RECT	34.64 175.255 34.96 175.425 ;
		RECT	0.32 176.145 34.64 176.835 ;
		RECT	0 176.145 0.32 176.835 ;
		RECT	34.64 176.145 34.96 176.835 ;
		RECT	0.32 177.635 34.64 177.685 ;
		RECT	0 177.635 0.32 177.685 ;
		RECT	34.64 177.635 34.96 177.685 ;
		RECT	0.32 178.095 34.64 178.265 ;
		RECT	0 178.095 0.32 178.265 ;
		RECT	34.64 178.095 34.96 178.265 ;
		RECT	0.32 178.985 34.64 179.675 ;
		RECT	0 178.985 0.32 179.675 ;
		RECT	34.64 178.985 34.96 179.675 ;
		RECT	0.32 180.475 34.64 180.525 ;
		RECT	0 180.475 0.32 180.525 ;
		RECT	34.64 180.475 34.96 180.525 ;
		RECT	0.32 180.935 34.64 181.105 ;
		RECT	0 180.935 0.32 181.105 ;
		RECT	34.64 180.935 34.96 181.105 ;
		RECT	0.32 181.825 34.64 182.515 ;
		RECT	0 181.825 0.32 182.515 ;
		RECT	34.64 181.825 34.96 182.515 ;
		RECT	0.32 183.315 34.64 183.365 ;
		RECT	0 183.315 0.32 183.365 ;
		RECT	34.64 183.315 34.96 183.365 ;
		RECT	0.32 183.775 34.64 183.945 ;
		RECT	0 183.775 0.32 183.945 ;
		RECT	34.64 183.775 34.96 183.945 ;
		RECT	0.32 184.665 34.64 185.355 ;
		RECT	0 184.665 0.32 185.355 ;
		RECT	34.64 184.665 34.96 185.355 ;
		RECT	0.32 186.155 34.64 186.205 ;
		RECT	0 186.155 0.32 186.205 ;
		RECT	34.64 186.155 34.96 186.205 ;
		RECT	0.32 186.615 34.64 186.785 ;
		RECT	0 186.615 0.32 186.785 ;
		RECT	34.64 186.615 34.96 186.785 ;
		RECT	0.32 187.505 34.64 188.195 ;
		RECT	0 187.505 0.32 188.195 ;
		RECT	34.64 187.505 34.96 188.195 ;
		RECT	0.32 188.995 34.64 189.045 ;
		RECT	0 188.995 0.32 189.045 ;
		RECT	34.64 188.995 34.96 189.045 ;
		RECT	0.32 189.455 34.64 189.625 ;
		RECT	0 189.455 0.32 189.625 ;
		RECT	34.64 189.455 34.96 189.625 ;
		RECT	0.32 190.345 34.64 191.035 ;
		RECT	0 190.345 0.32 191.035 ;
		RECT	34.64 190.345 34.96 191.035 ;
		RECT	0.32 191.835 34.64 191.885 ;
		RECT	0 191.835 0.32 191.885 ;
		RECT	34.64 191.835 34.96 191.885 ;
		RECT	0.32 192.295 34.64 192.465 ;
		RECT	0 192.295 0.32 192.465 ;
		RECT	34.64 192.295 34.96 192.465 ;
		RECT	0.32 193.185 34.64 193.875 ;
		RECT	0 193.185 0.32 193.875 ;
		RECT	34.64 193.185 34.96 193.875 ;
		RECT	0.32 194.675 34.64 194.725 ;
		RECT	0 194.675 0.32 194.725 ;
		RECT	34.64 194.675 34.96 194.725 ;
		RECT	0.32 195.135 34.64 195.305 ;
		RECT	0 195.135 0.32 195.305 ;
		RECT	34.64 195.135 34.96 195.305 ;
		RECT	0.32 196.025 34.64 196.715 ;
		RECT	0 196.025 0.32 196.715 ;
		RECT	34.64 196.025 34.96 196.715 ;
		RECT	0.32 197.515 34.64 197.565 ;
		RECT	0 197.515 0.32 197.565 ;
		RECT	34.64 197.515 34.96 197.565 ;
		RECT	0.32 197.975 34.64 198.145 ;
		RECT	0 197.975 0.32 198.145 ;
		RECT	34.64 197.975 34.96 198.145 ;
		RECT	0.32 198.865 34.64 199.555 ;
		RECT	0 198.865 0.32 199.555 ;
		RECT	34.64 198.865 34.96 199.555 ;
		RECT	0.32 200.355 34.64 200.405 ;
		RECT	0 200.355 0.32 200.405 ;
		RECT	34.64 200.355 34.96 200.405 ;
		RECT	0.32 200.815 34.64 200.985 ;
		RECT	0 200.815 0.32 200.985 ;
		RECT	34.64 200.815 34.96 200.985 ;
		RECT	0.32 201.705 34.64 202.395 ;
		RECT	0 201.705 0.32 202.395 ;
		RECT	34.64 201.705 34.96 202.395 ;
		RECT	0.32 203.195 34.64 203.245 ;
		RECT	0 203.195 0.32 203.245 ;
		RECT	34.64 203.195 34.96 203.245 ;
		RECT	0.32 203.655 34.64 203.825 ;
		RECT	0 203.655 0.32 203.825 ;
		RECT	34.64 203.655 34.96 203.825 ;
		RECT	0.32 204.545 34.64 205.125 ;
		RECT	0 204.545 0.32 205.125 ;
		RECT	34.64 204.545 34.96 205.125 ;
		RECT	0.32 205.935 34.64 206.025 ;
		RECT	0 205.935 0.32 206.025 ;
		RECT	34.64 205.935 34.96 206.025 ;
		LAYER	VIA1 DESIGNRULEWIDTH 0.07 ;
		RECT	0 0 34.96 206.025 ;
		LAYER	VIA2 DESIGNRULEWIDTH 0.07 ;
		RECT	0 0 34.96 206.025 ;
		LAYER	VIA3 DESIGNRULEWIDTH 0.07 ;
		RECT	0 0 34.96 206.025 ;
	END

END rf128x128

END LIBRARY

